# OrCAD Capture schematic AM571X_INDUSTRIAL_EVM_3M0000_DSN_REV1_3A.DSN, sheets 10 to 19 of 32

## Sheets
10 Pg22: JTAG Debug: size C
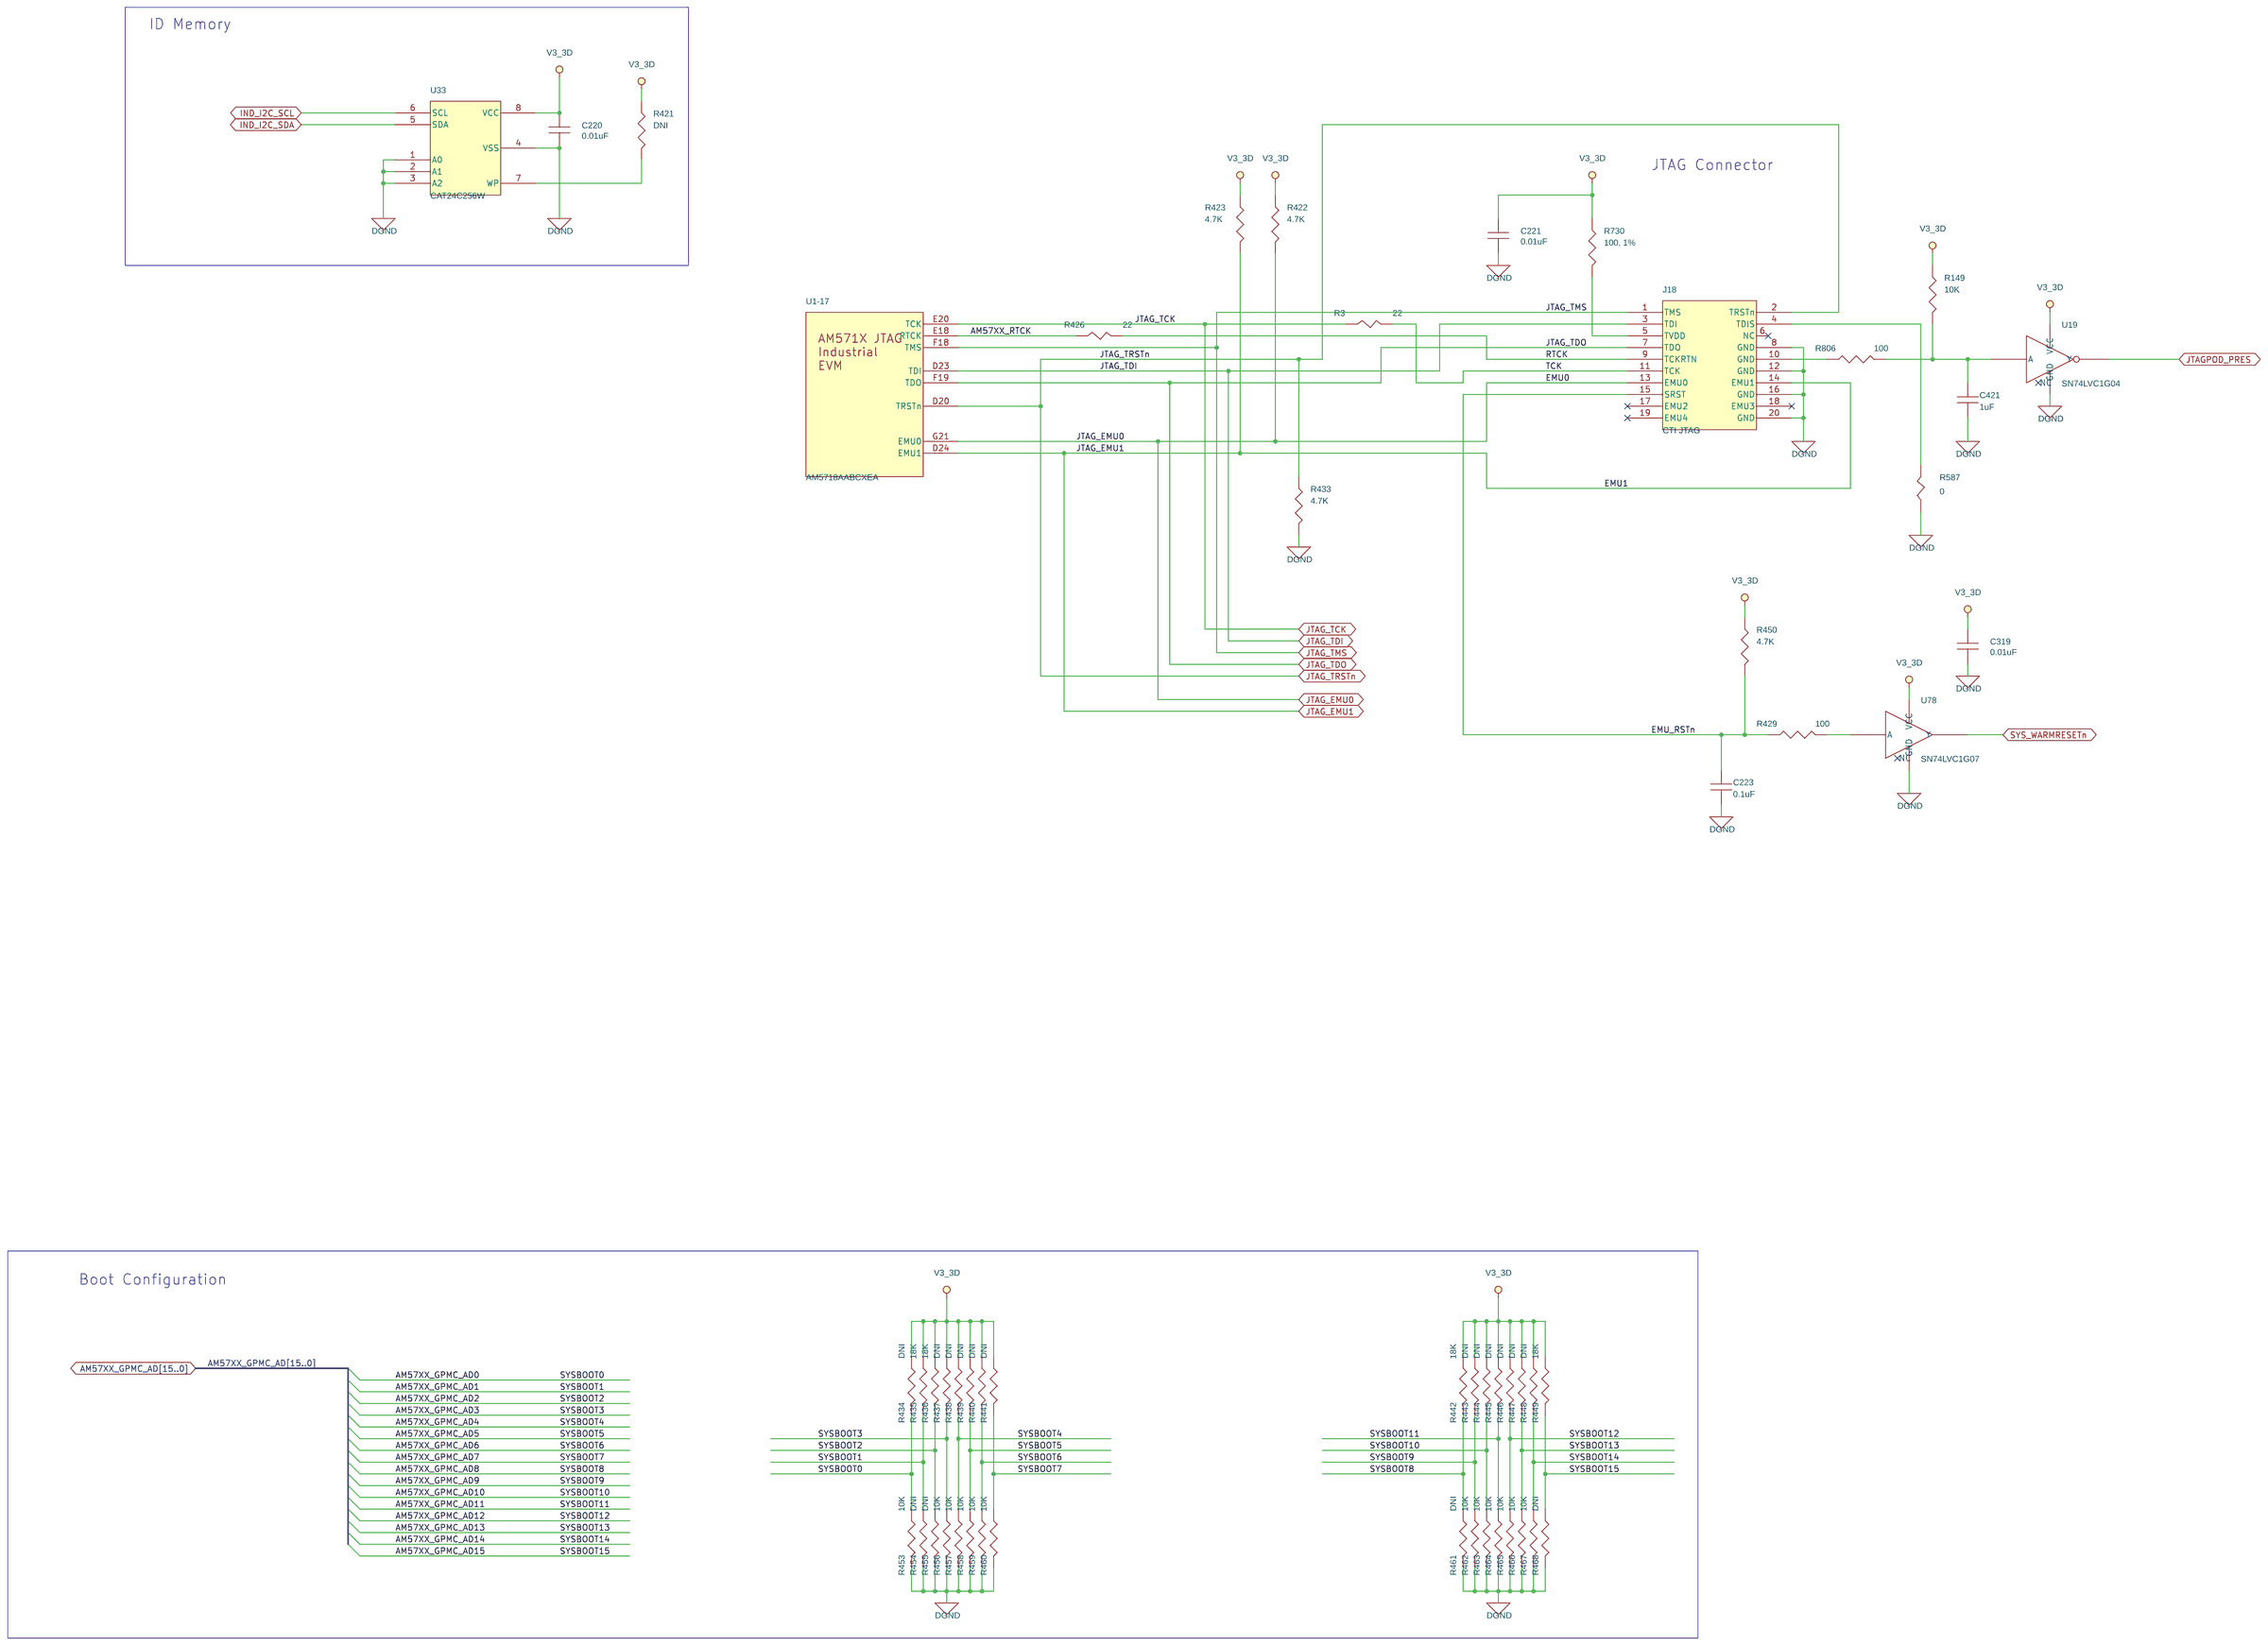
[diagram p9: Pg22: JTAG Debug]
11 Pg15: Camera #1: size C
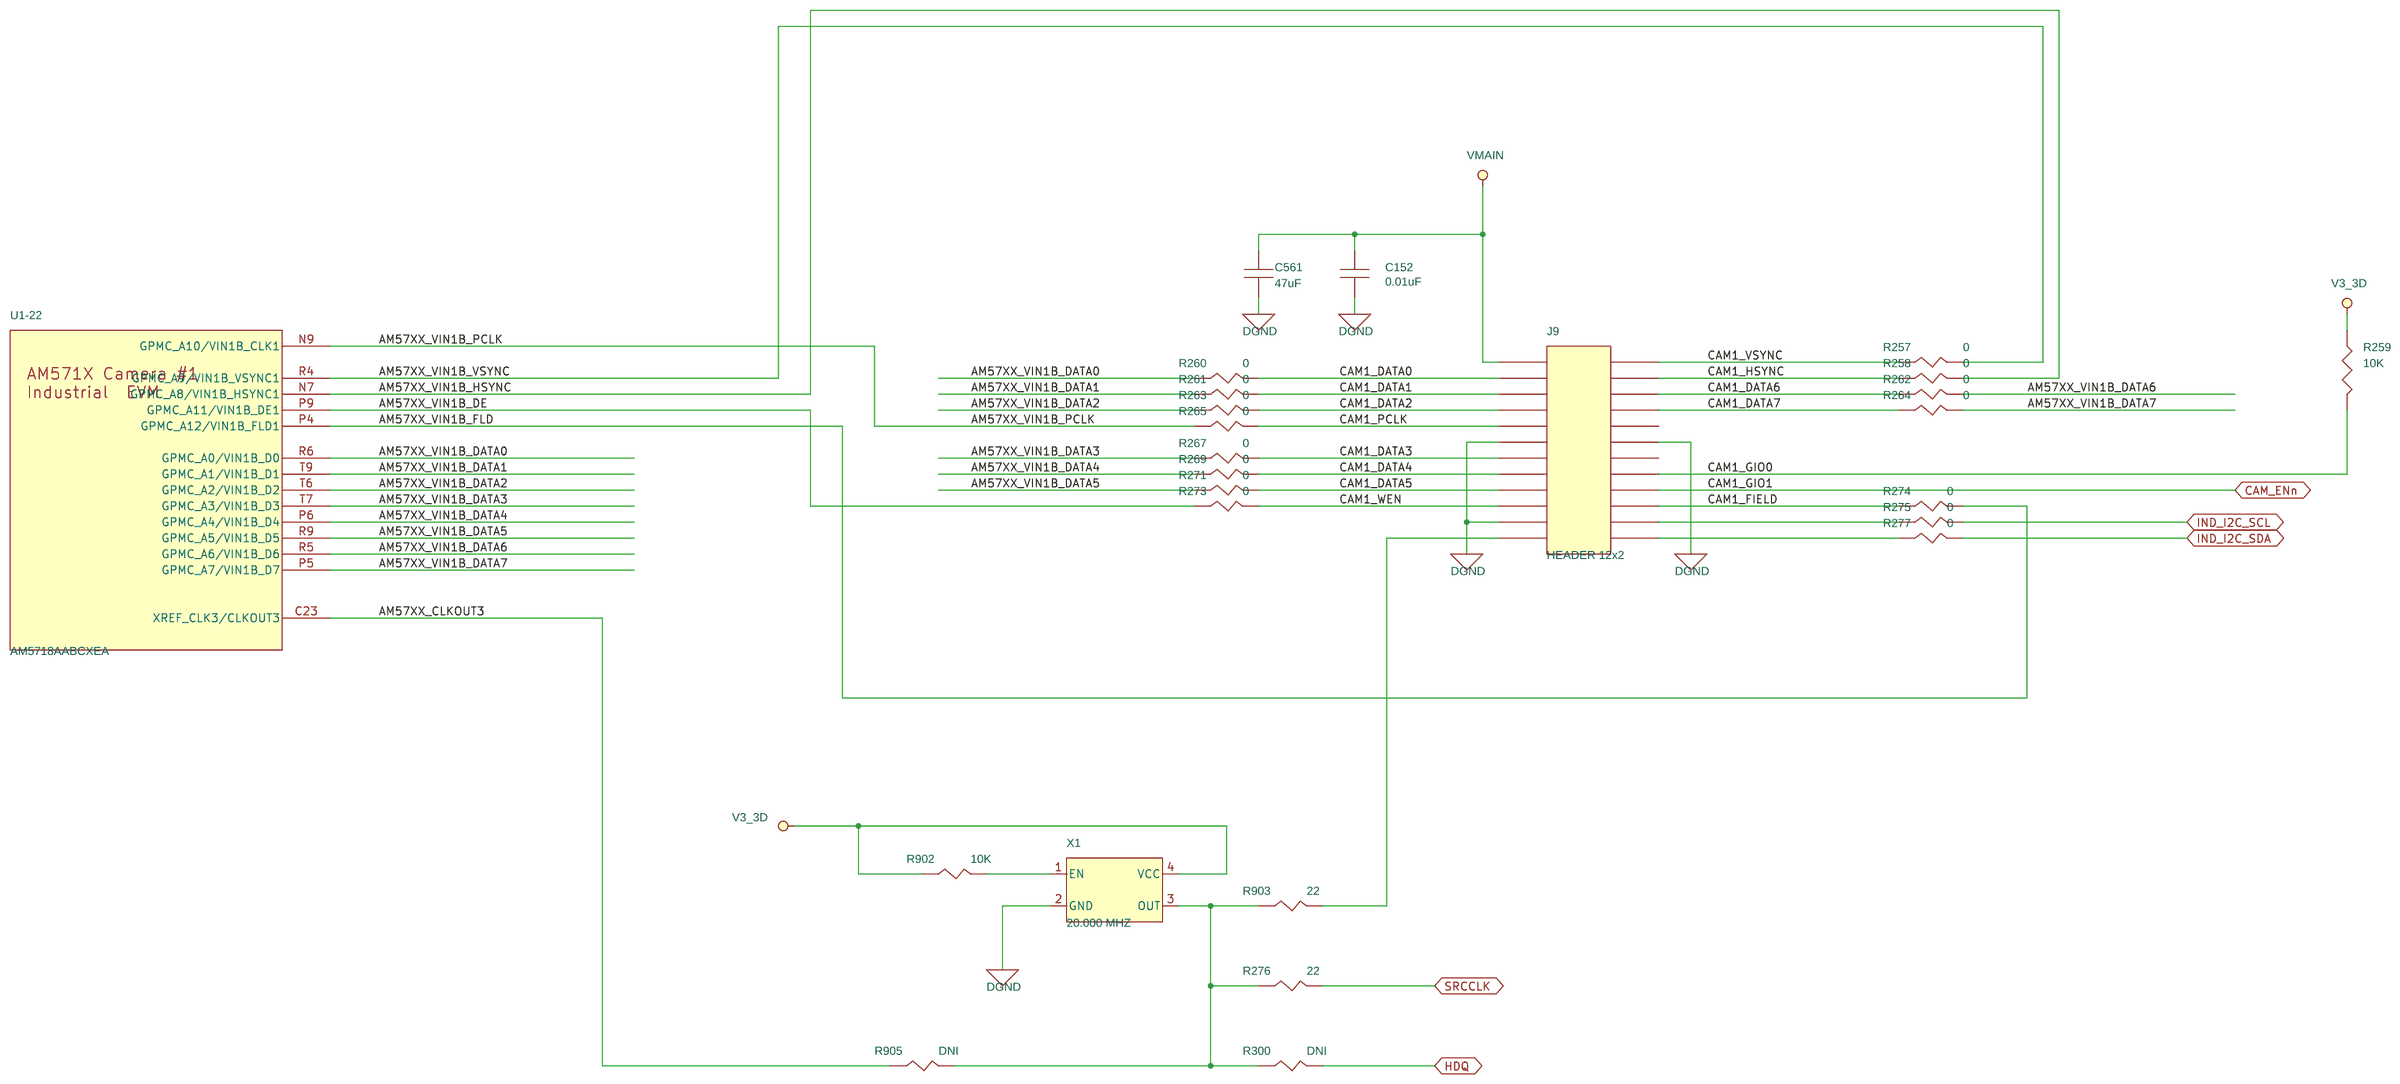
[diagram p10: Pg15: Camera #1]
12 Pg28: Profibus: size C
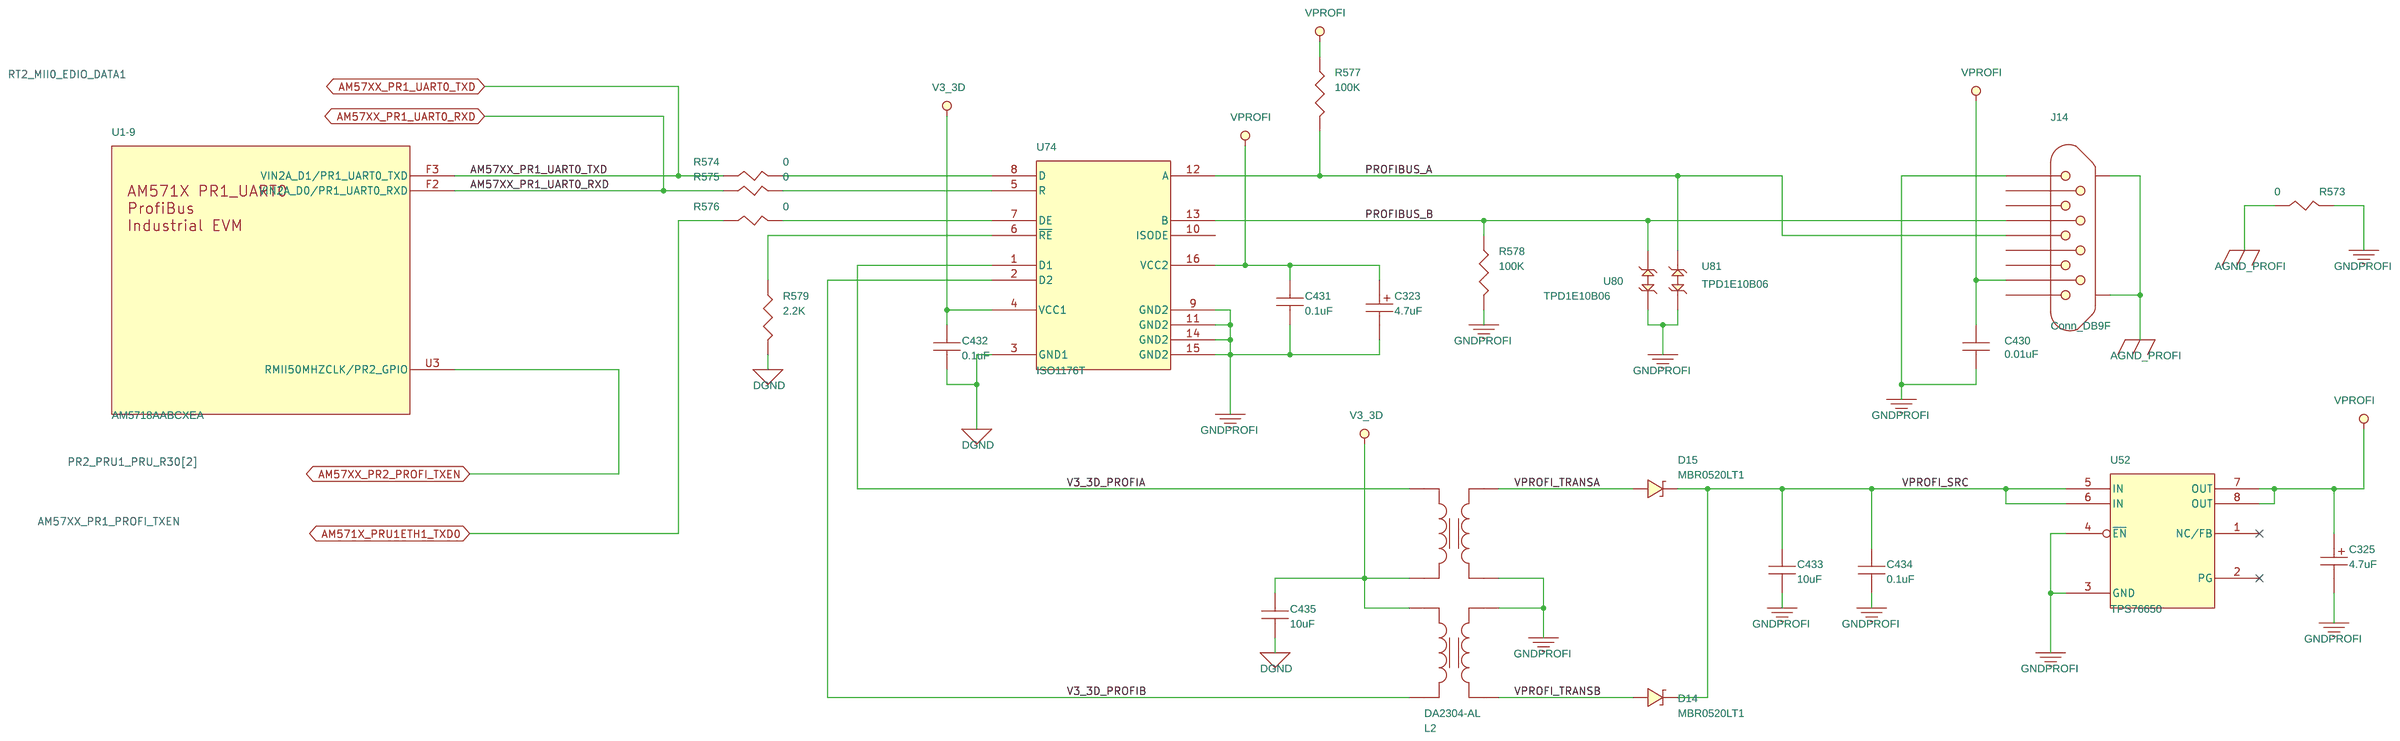
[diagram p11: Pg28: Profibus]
13 Pg01: Title Page
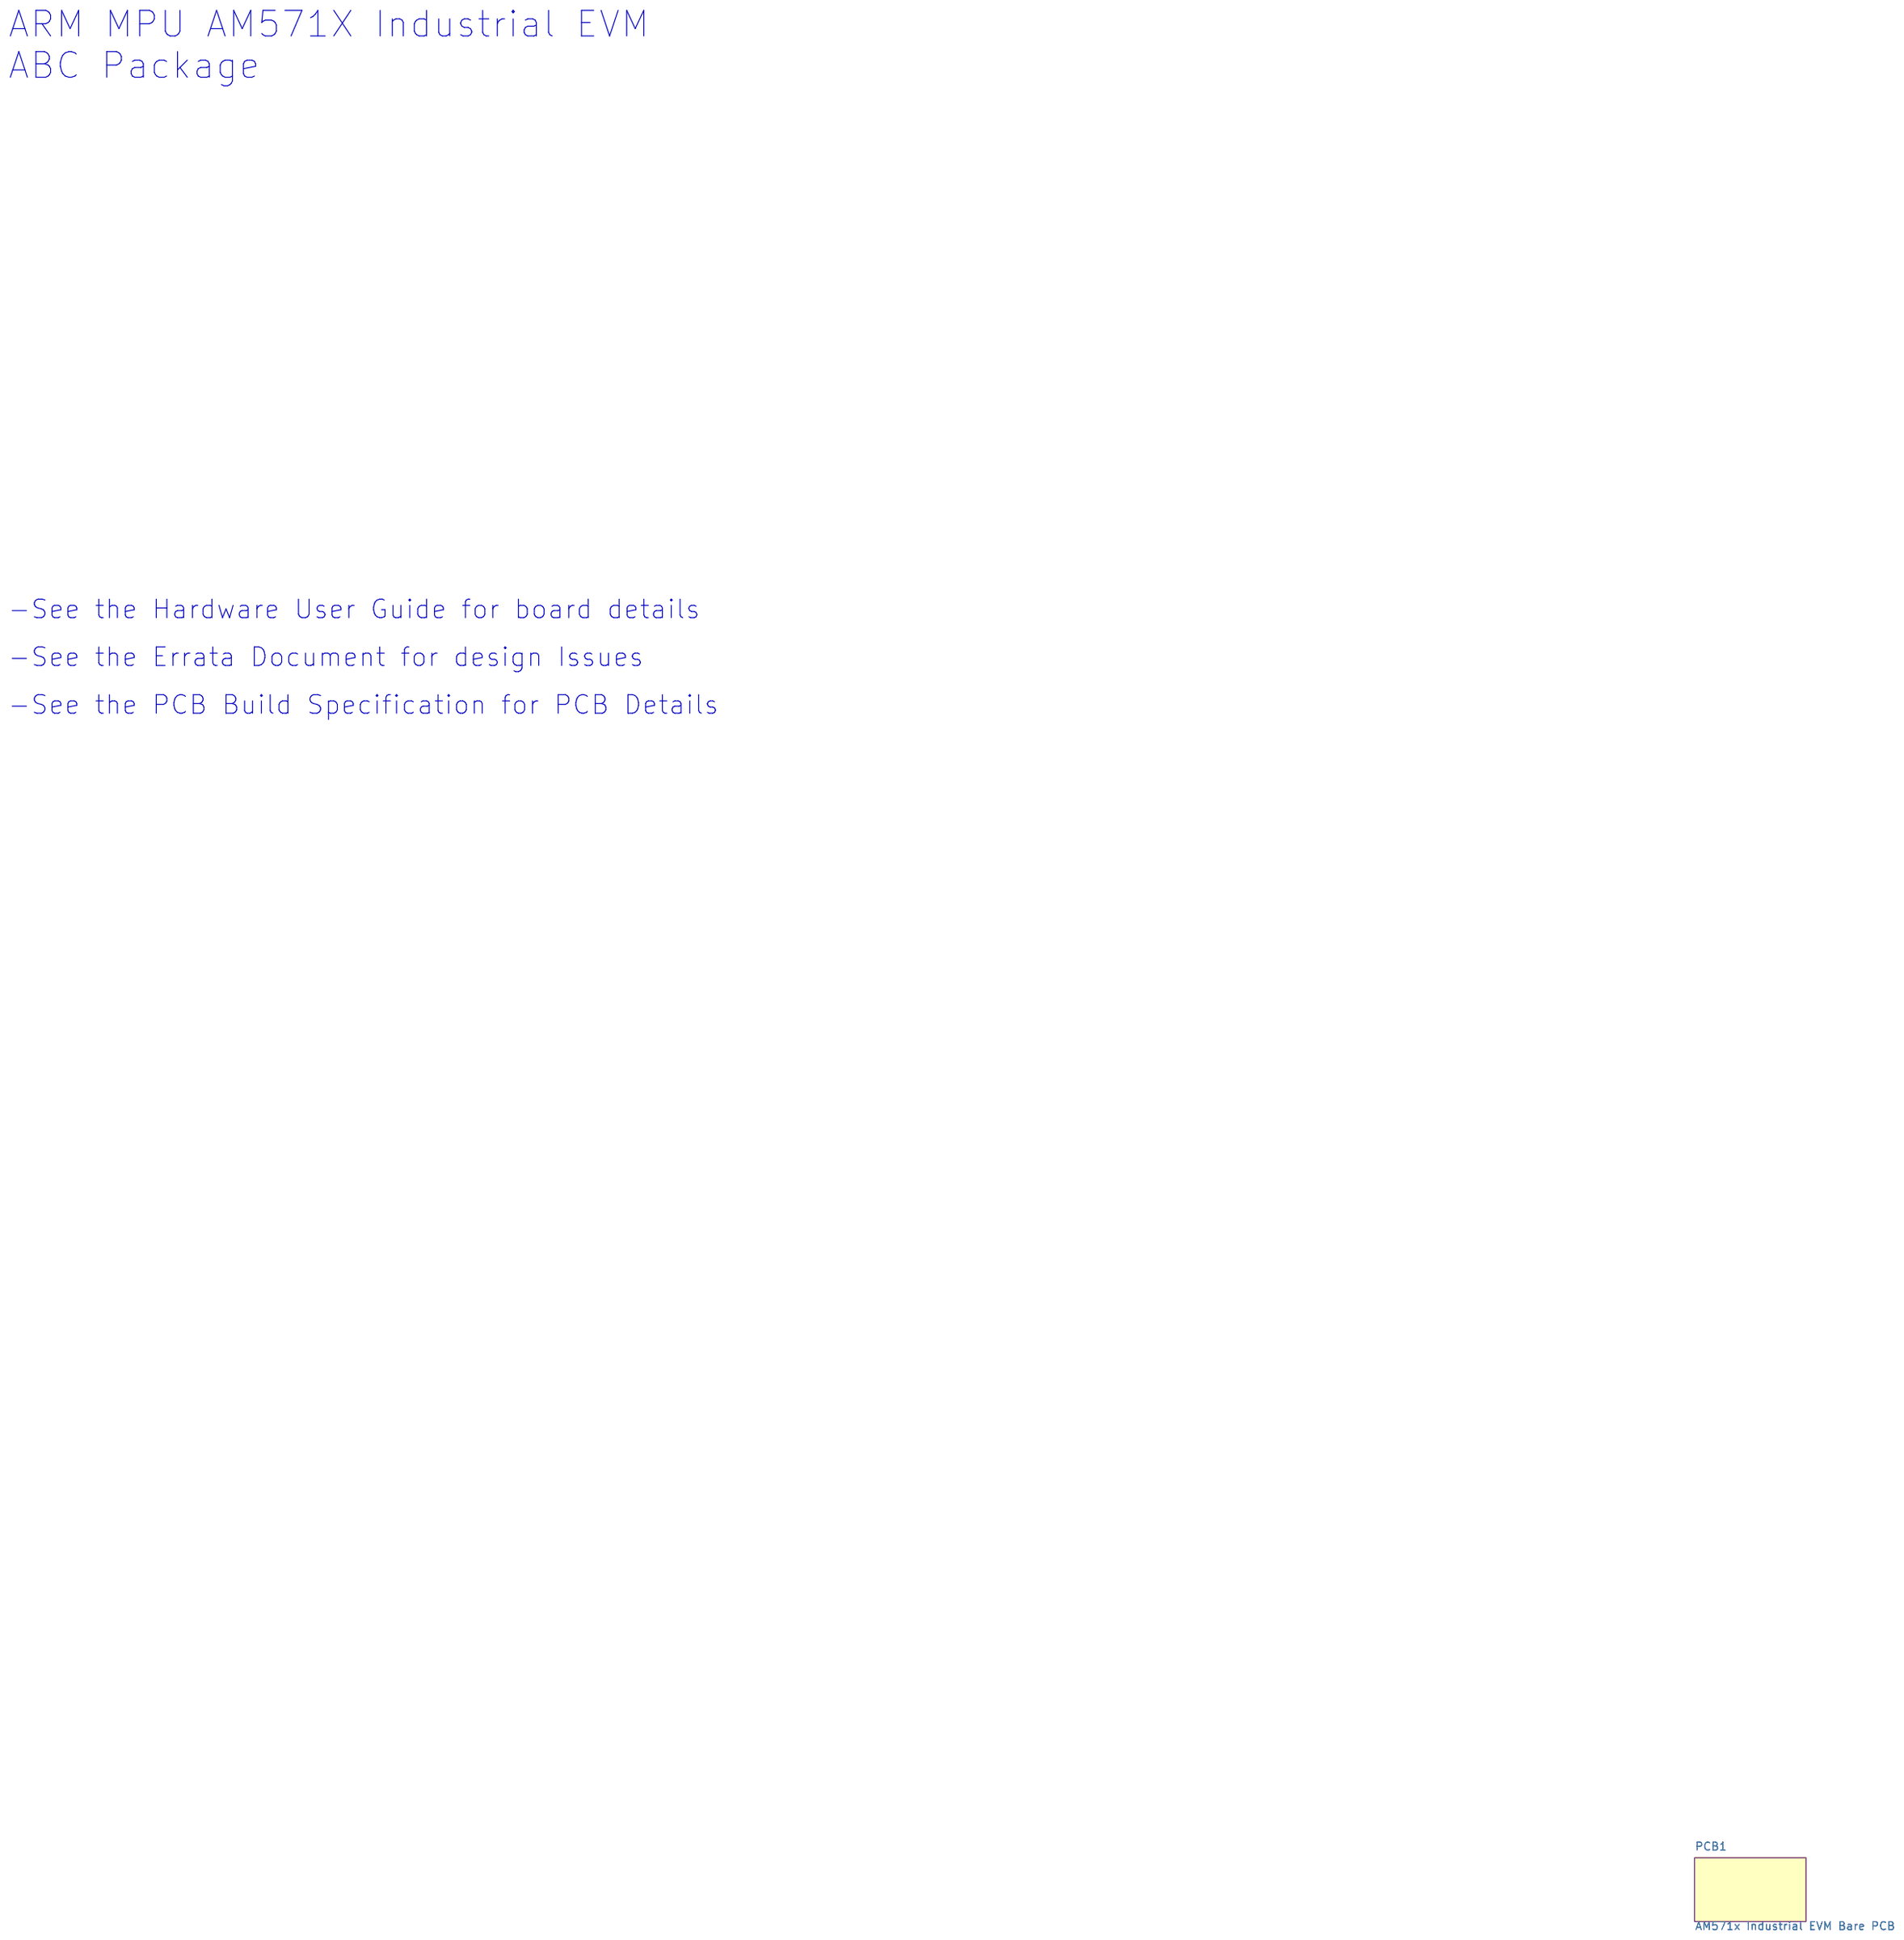
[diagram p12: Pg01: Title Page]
14 Pg26: USB #2 2.0: size C
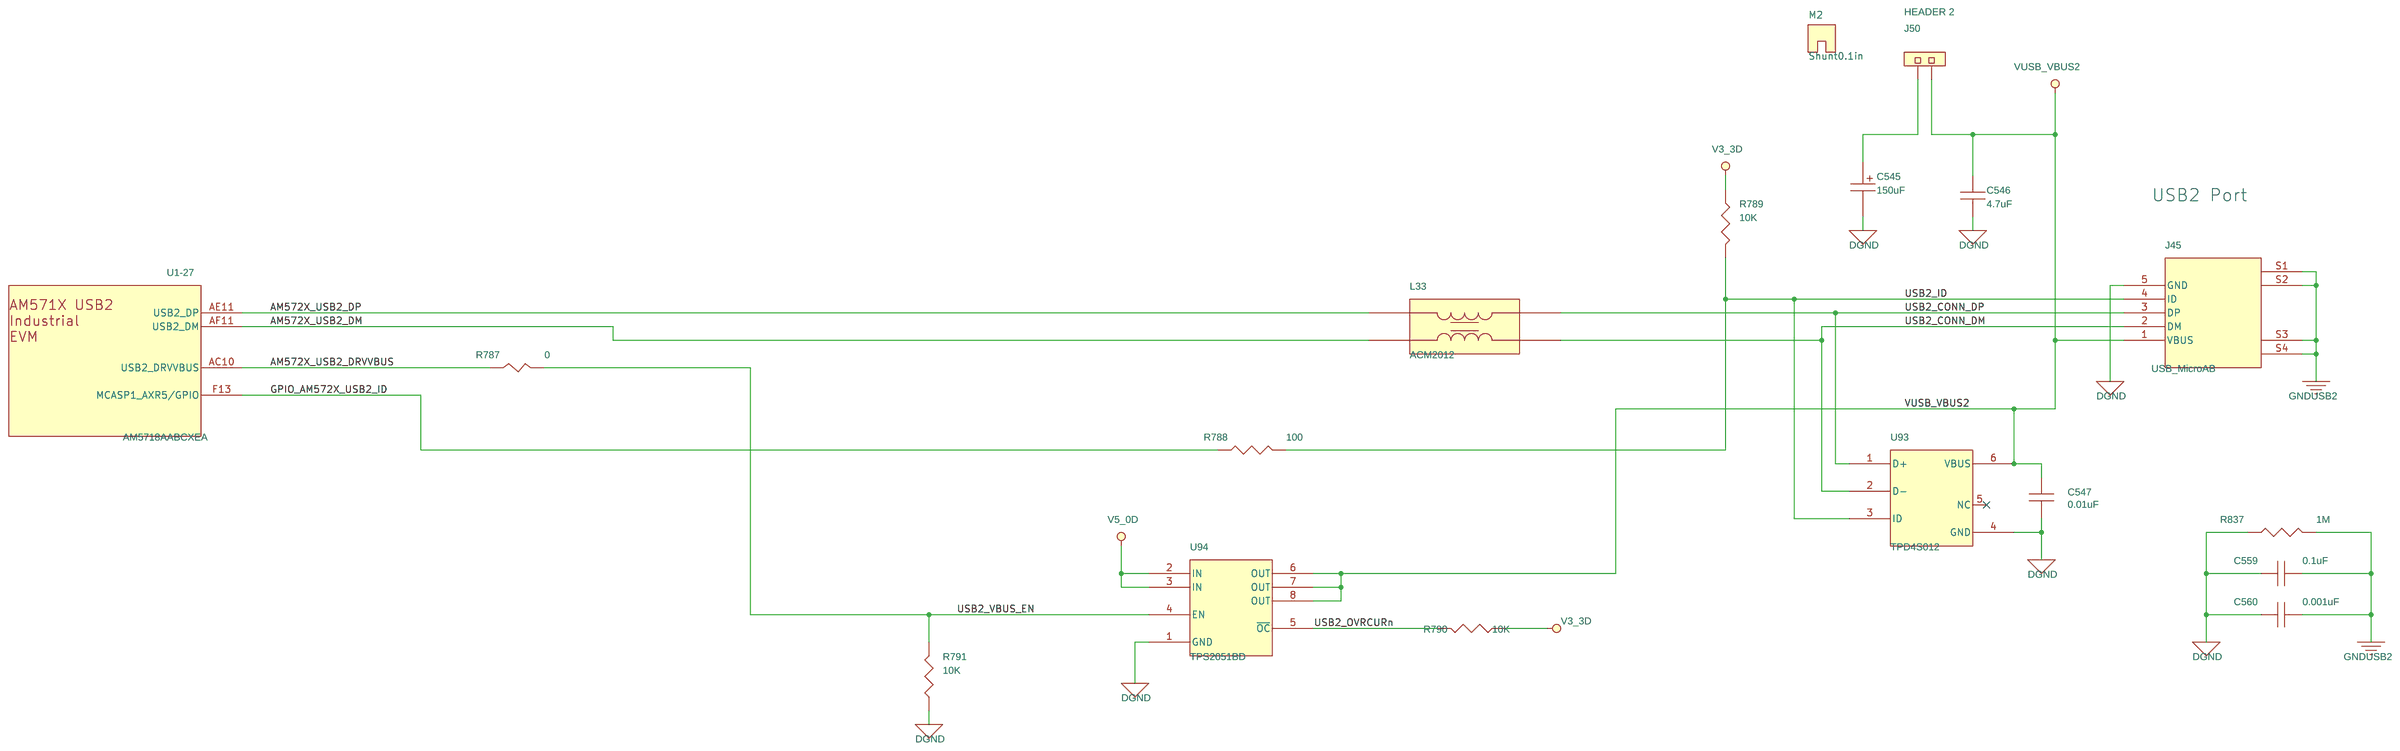
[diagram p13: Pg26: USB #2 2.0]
15 Pg25: USB #1 3.0: size C
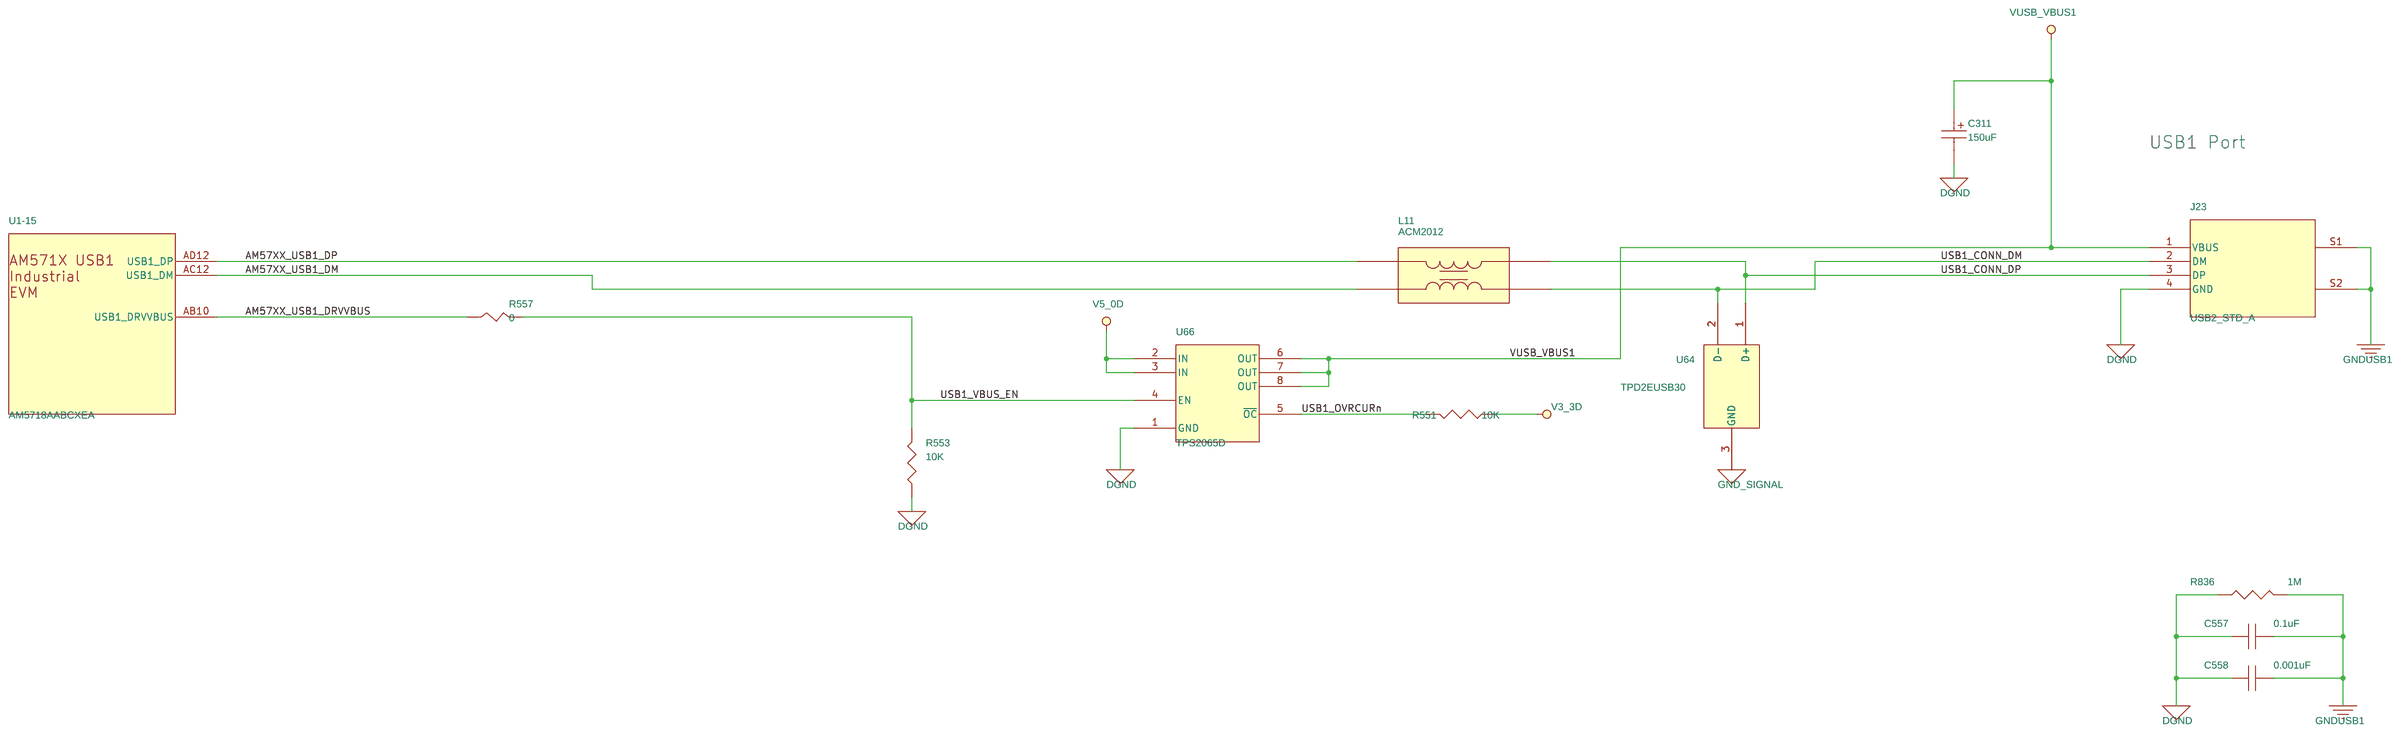
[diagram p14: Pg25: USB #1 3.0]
16 Pg08: DDR3 Memory 1: size C
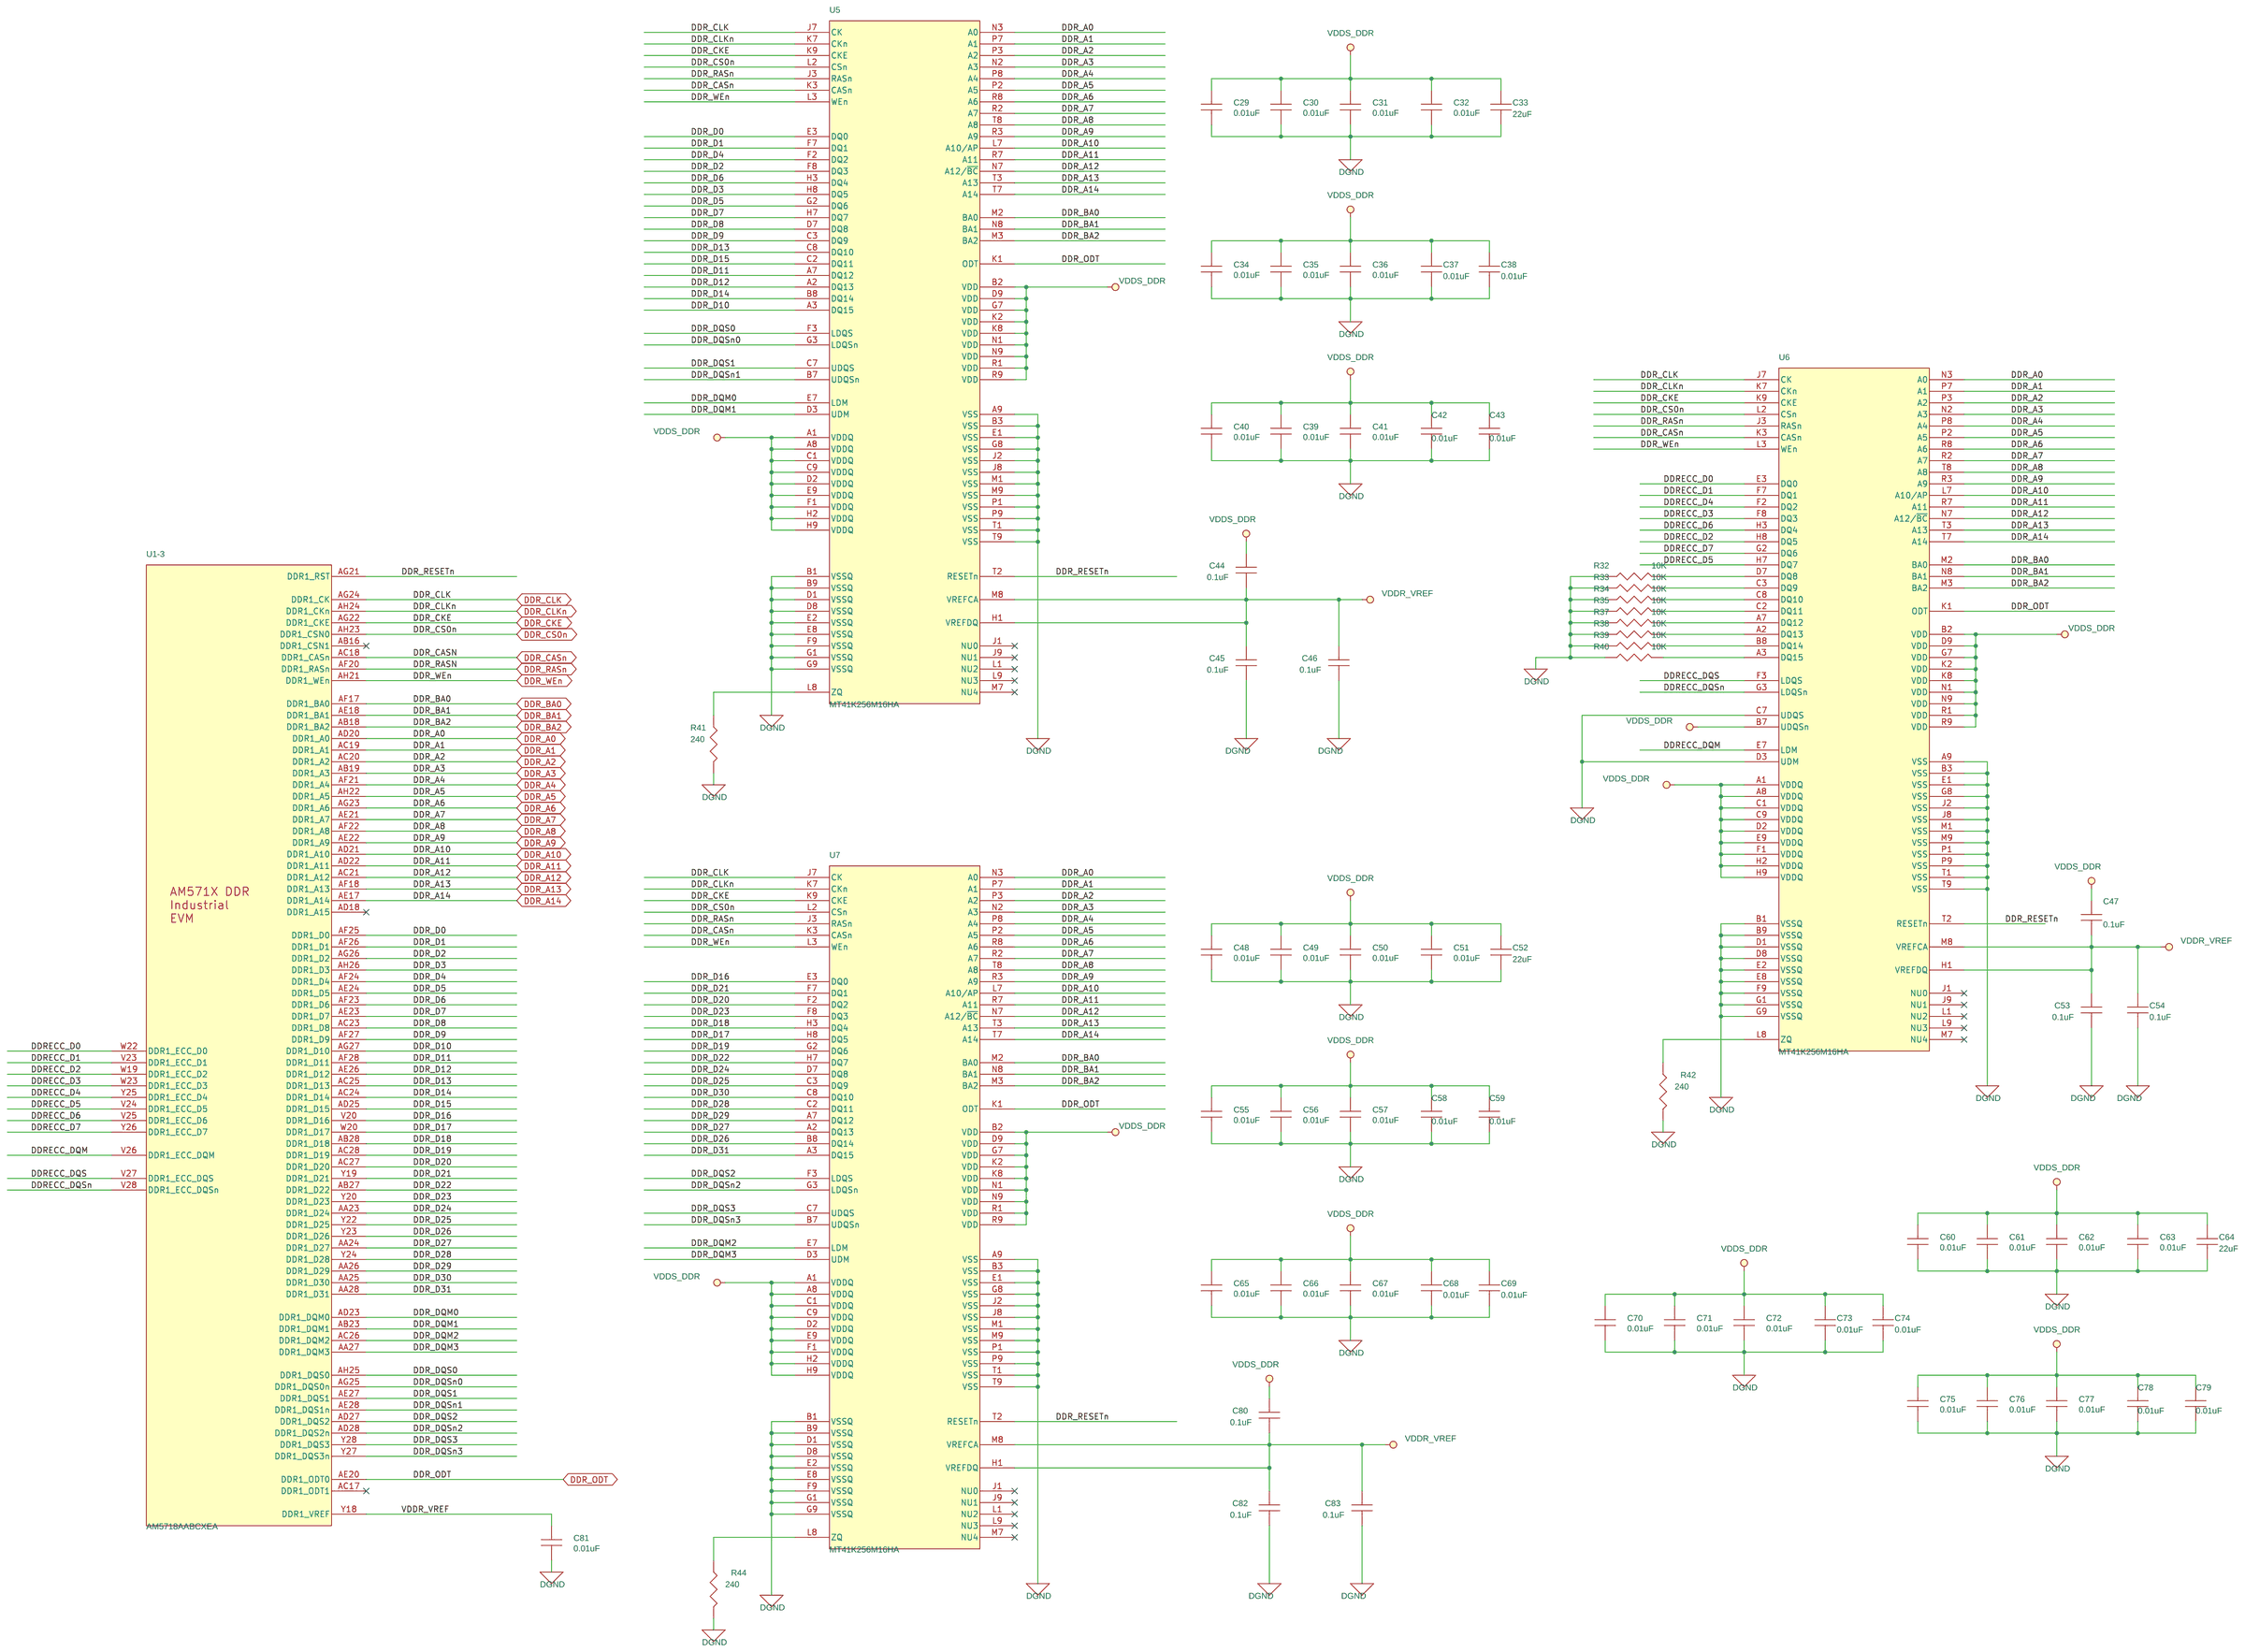
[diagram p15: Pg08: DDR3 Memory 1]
17 Pg03: Processor Power: size C
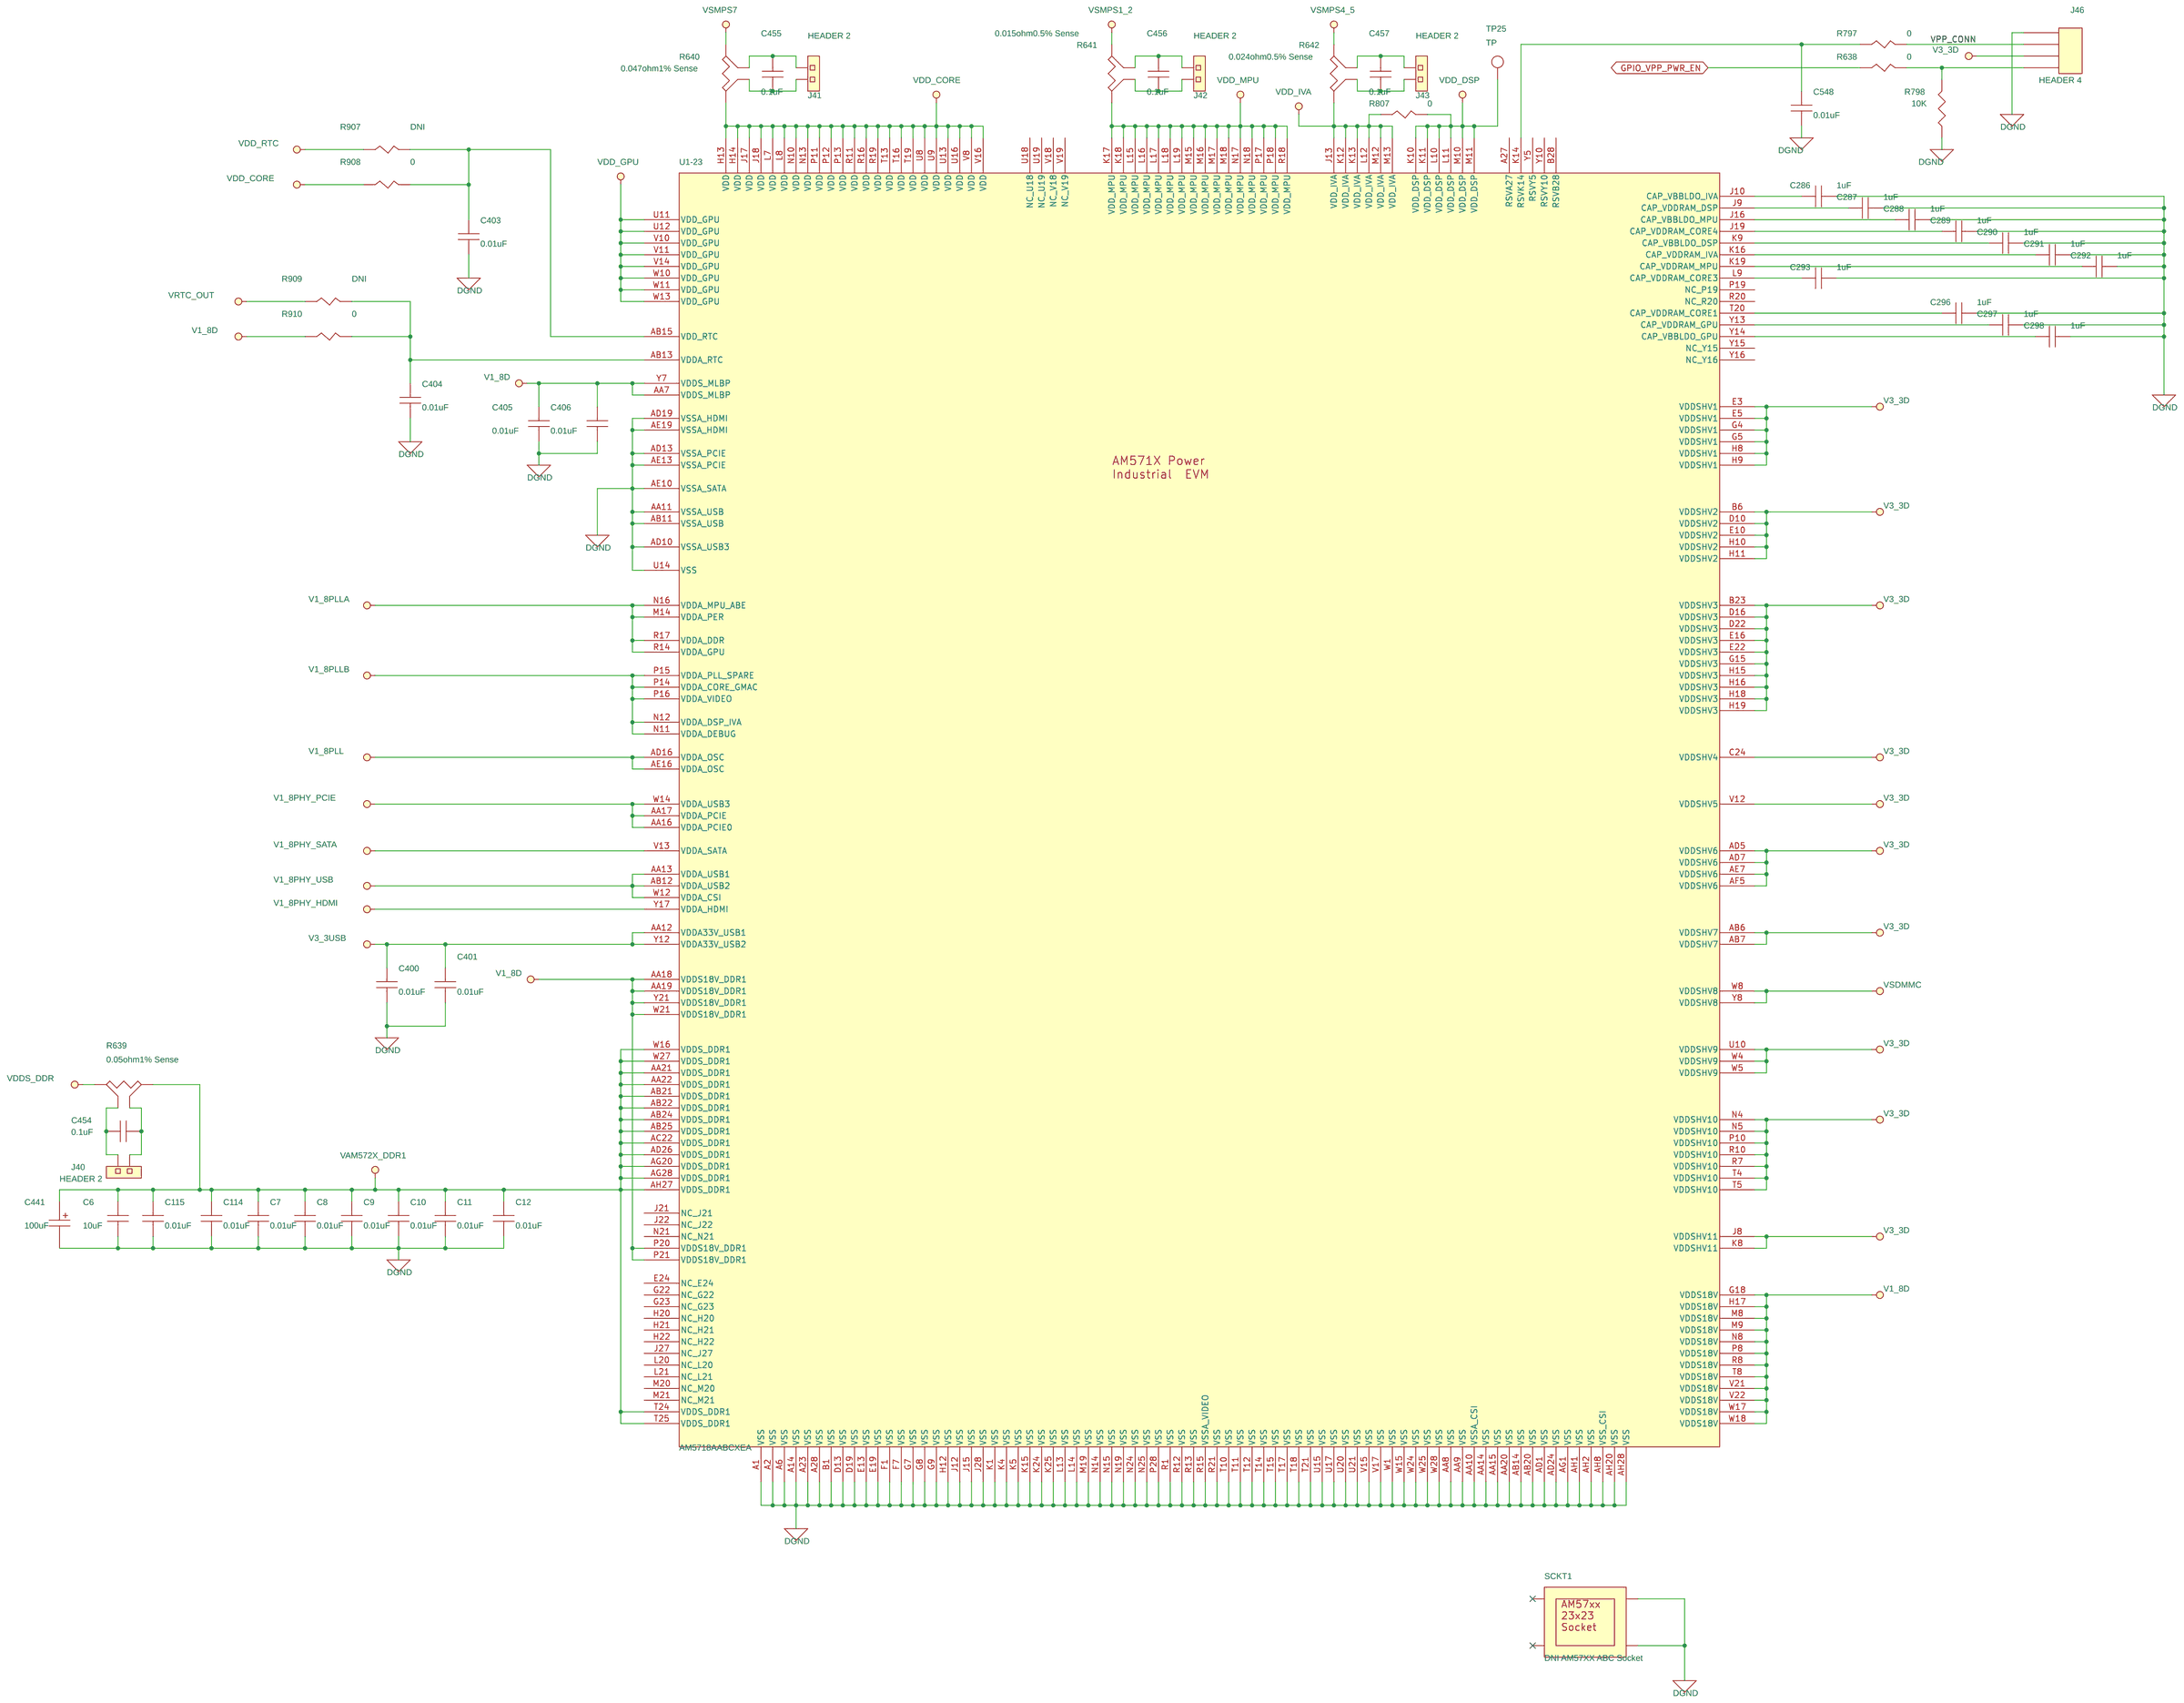
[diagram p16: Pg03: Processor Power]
18 Pg19: Industrial I/O: size C
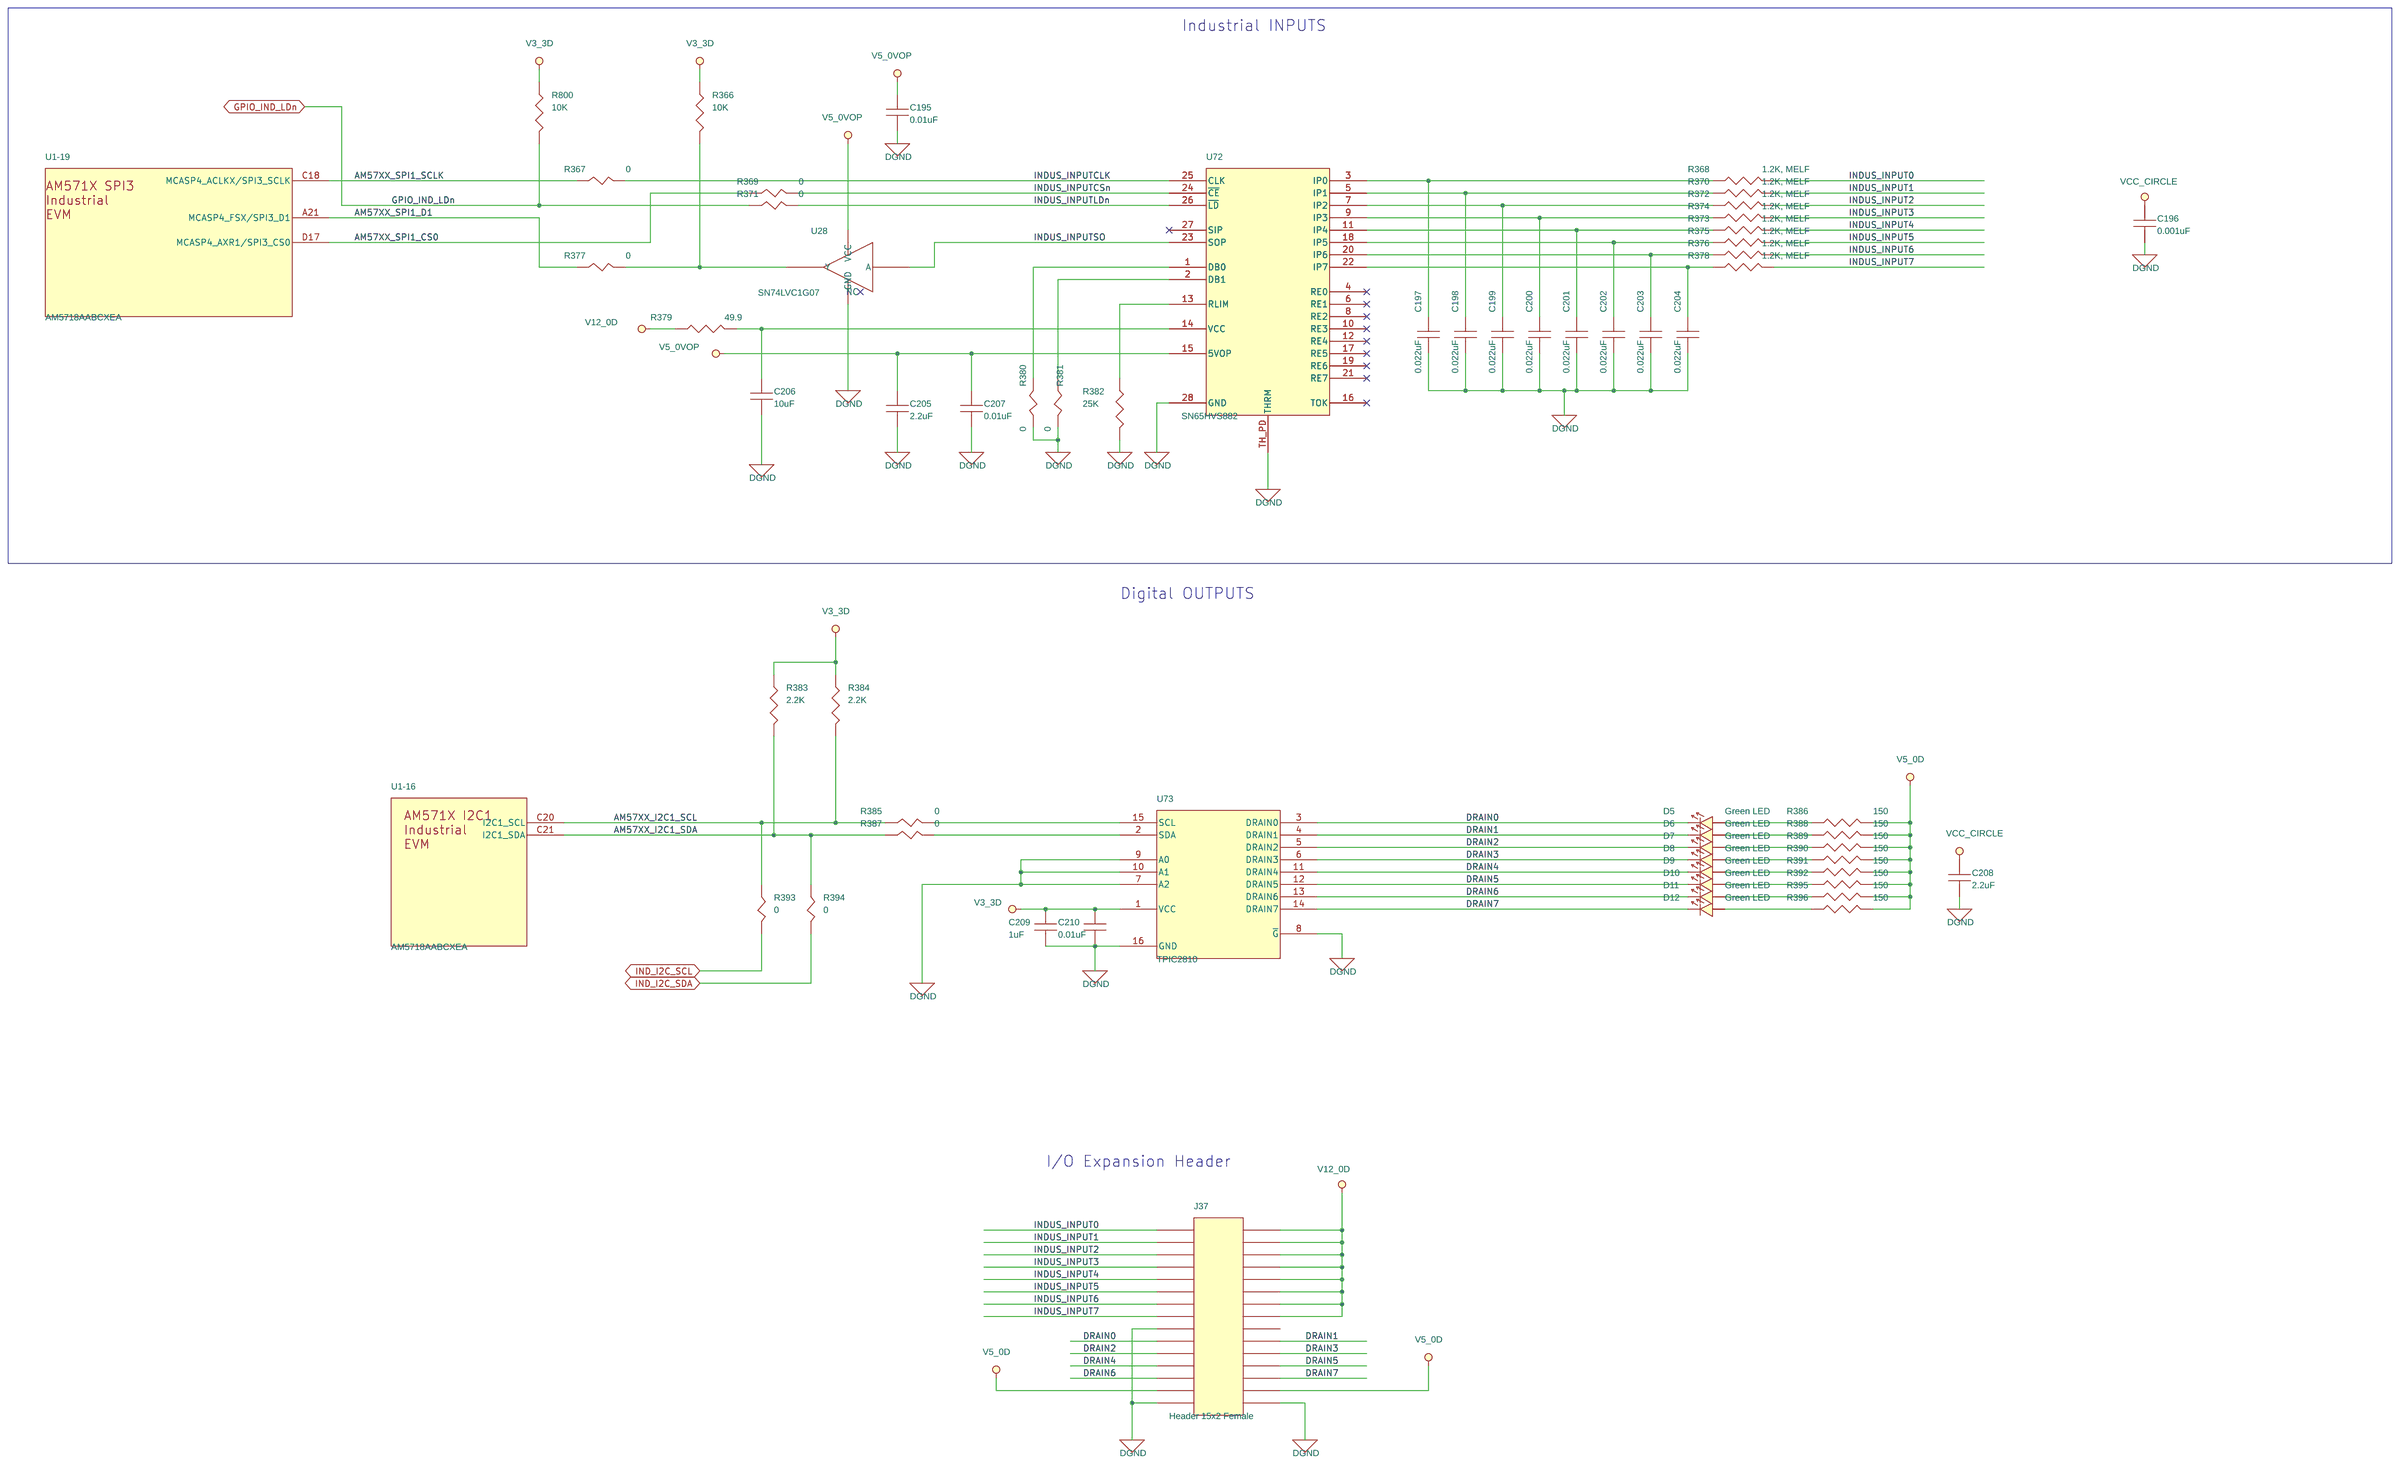
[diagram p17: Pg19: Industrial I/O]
19 Pg06: Power Supply 2: size C

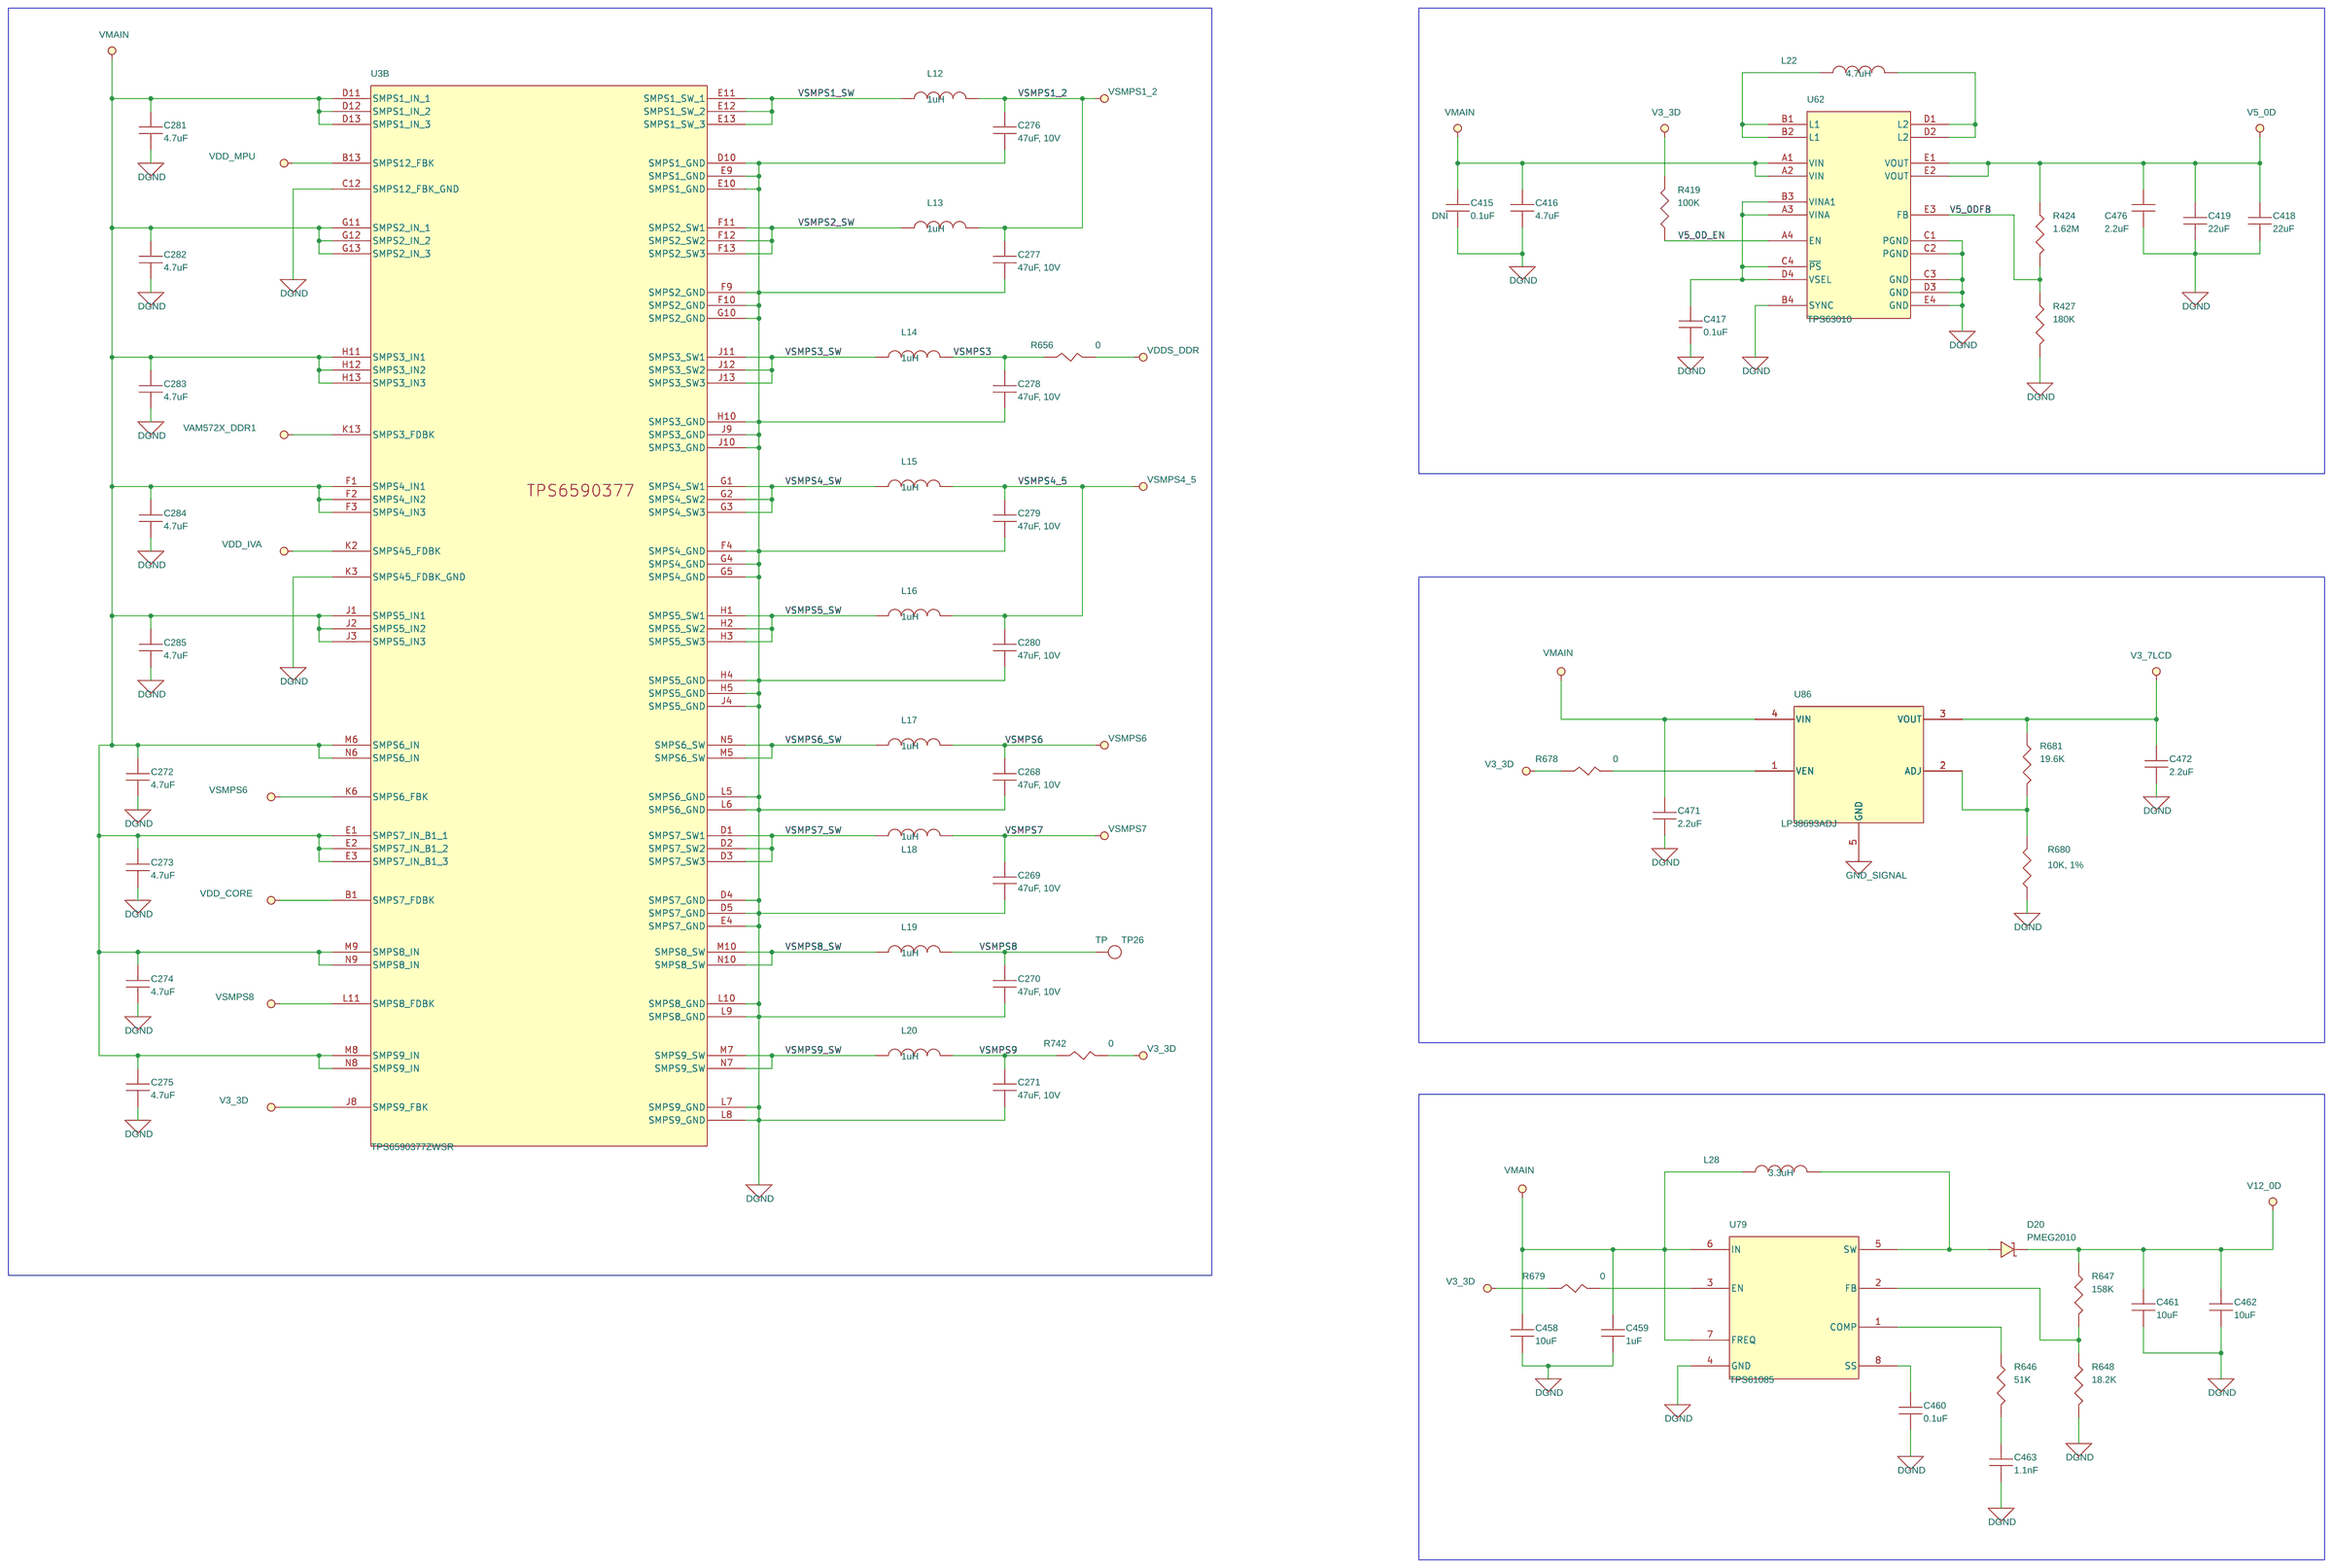
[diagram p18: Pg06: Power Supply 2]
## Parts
sheet Pg01: Title Page
PCB1  AM571x Industrial EVM Bare PCB  [DNP]
sheet Pg03: Processor Power
C6  10uF  [SM-7351-CAP-0805]
C7  0.01uF  [SM-7351-CAP-0402]
C8  0.01uF  [SM-7351-CAP-0402]
C9  0.01uF  [SM-7351-CAP-0402]
C10  0.01uF  [SM-7351-CAP-0402]
C11  0.01uF  [SM-7351-CAP-0402]
C12  0.01uF  [SM-7351-CAP-0402]
C114  0.01uF  [SM-7351-CAP-0402]
C115  0.01uF  [SM-7351-CAP-0402]
C286  1uF  [SM-7351-CAP-0402]
C287  1uF  [SM-7351-CAP-0402]
C288  1uF  [SM-7351-CAP-0402]
C289  1uF  [SM-7351-CAP-0402]
C290  1uF  [SM-7351-CAP-0402]
C291  1uF  [SM-7351-CAP-0402]
C292  1uF  [SM-7351-CAP-0402]
C293  1uF  [SM-7351-CAP-0402]
C296  1uF  [SM-7351-CAP-0402]
C297  1uF  [SM-7351-CAP-0402]
C298  1uF  [SM-7351-CAP-0402]
C400  0.01uF  [SM-7351-CAP-0402]
C401  0.01uF  [SM-7351-CAP-0402]
C403  0.01uF  [SM-7351-CAP-0402]
C404  0.01uF  [SM-7351-CAP-0402]
C405  0.01uF  [SM-7351-CAP-0402]
C406  0.01uF  [SM-7351-CAP-0402]
C441  100uF  [SM-7351-CAP-smdcan]
C454  0.1uF  [SM-7351-CAP-0402]
C455  0.1uF  [SM-7351-CAP-0402]
C456  0.1uF  [SM-7351-CAP-0402]
C457  0.1uF  [SM-7351-CAP-0402]
C548  0.01uF  [SM-7351-CAP-0402]
J40  HEADER 2  [header_2x1]
J41  HEADER 2  [header_2x1]
J42  HEADER 2  [header_2x1]
J43  HEADER 2  [header_2x1]
J46  HEADER 4  [HDR1x4-330M]
R638  0  [SM-7351-RES-0402]
R639  0.05ohm1% Sense  [SM_RES_LVK12]
R640  0.047ohm1% Sense  [SM_RES_LVK12]
R641  0.015ohm0.5% Sense  [SM_RES_LVK12]
R642  0.024ohm0.5% Sense  [SM_RES_LVK12]
R797  0  [SM-7351-RES-0402]
R798  10K  [SM-7351-RES-0402]
R807  0  [SM-7351-RES-0402]
R907  DNI  [SM-7351-RES-0402]
R908  0  [SM-7351-RES-0402]
R909  DNI  [SM-7351-RES-0402]
R910  0  [SM-7351-RES-0402]
SCKT1  DNI AM57XX ABC Socket  [SCK-SG-BGA-6334]
TP25  TP  [TH_TP_5002]
sheet Pg05: Power Supply 1
U3  TPS6590377ZWSR  [bga12x12-169-55m]  (sections A,B)
sheet Pg06: Power Supply 2
C268  47uF, 10V  [SM-7351-CAP-1206]
C269  47uF, 10V  [SM-7351-CAP-1206]
C270  47uF, 10V  [SM-7351-CAP-1206]
C271  47uF, 10V  [SM-7351-CAP-1206]
C272  4.7uF  [SM-7351-CAP-0603]
C273  4.7uF  [SM-7351-CAP-0603]
C274  4.7uF  [SM-7351-CAP-0603]
C275  4.7uF  [SM-7351-CAP-0603]
C276  47uF, 10V  [SM-7351-CAP-1206]
C277  47uF, 10V  [SM-7351-CAP-1206]
C278  47uF, 10V  [SM-7351-CAP-1206]
C279  47uF, 10V  [SM-7351-CAP-1206]
C280  47uF, 10V  [SM-7351-CAP-1206]
C281  4.7uF  [SM-7351-CAP-0603]
C282  4.7uF  [SM-7351-CAP-0603]
C283  4.7uF  [SM-7351-CAP-0603]
C284  4.7uF  [SM-7351-CAP-0603]
C285  4.7uF  [SM-7351-CAP-0603]
C415  0.1uF  [SM-7351-CAP-0402]
C416  4.7uF  [SM-7351-CAP-0603]
C417  0.1uF  [SM-7351-CAP-0402]
C418  22uF  [SM-7351-CAP-0805]
C419  22uF  [SM-7351-CAP-0805]
C458  10uF  [SM-7351-CAP-0805]
C459  1uF  [SM-7351-CAP-0603]
C460  0.1uF  [SM-7351-CAP-0402]
C461  10uF  [SM-7351-CAP-0805]
C462  10uF  [SM-7351-CAP-0805]
C463  1.1nF  [SM-7351-CAP-0603]
C471  2.2uF  [SM-7351-CAP-0805]
C472  2.2uF  [SM-7351-CAP-0805]
C476  2.2uF  [SM-7351-CAP-0402]
D20  PMEG2010  [DFN1006D-2]
L12  1uH  [ind_ihlp1616ab]
L13  1uH  [ind_ihlp1616ab]
L14  1uH  [ind_ihlp1616ab]
L15  1uH  [ind_ihlp1616ab]
L16  1uH  [ind_ihlp1616ab]
L17  1uH  [ind_ihlp1616ab]
L18  1uH  [ind_ihlp1616ab]
L19  1uH  [ind_ihlp1616ab]
L20  1uH  [ind_ihlp1616ab]
L22  4.7uH  [smd_slf7055t]
L28  3.3uH  [vlcf5020t]
R419  100K  [SM-7351-RES-0402]
R424  1.62M  [SM-7351-RES-0402]
R427  180K  [SM-7351-RES-0402]
R646  51K  [SM-7351-RES-0402]
R647  158K  [SM-7351-RES-0402]
R648  18.2K  [SM-7351-RES-0402]
R656  0  [SM-7351-RES-0603]
R678  0  [SM-7351-RES-0402]
R679  0  [SM-7351-RES-0402]
R680  10K, 1%  [SM-7351-RES-0402]
R681  19.6K  [SM-7351-RES-0402]
R742  0  [SM-7351-RES-0603]
TP26  TP  [TH_TP_5002]
U62  TPS63010  [u_20_dsbga]
U79  TPS61085  [MSOP3X3-8-43M]
U86  LP38693ADJ  [SOT-223-5]
sheet Pg08: DDR3 Memory 1
C29  0.01uF  [SM-7351-CAP-0402]
C30  0.01uF  [SM-7351-CAP-0402]
C31  0.01uF  [SM-7351-CAP-0402]
C32  0.01uF  [SM-7351-CAP-0402]
C33  22uF  [SM-7351-CAP-0805]
C34  0.01uF  [SM-7351-CAP-0402]
C35  0.01uF  [SM-7351-CAP-0402]
C36  0.01uF  [SM-7351-CAP-0402]
C37  0.01uF  [SM-7351-CAP-0402]
C38  0.01uF  [SM-7351-CAP-0402]
C39  0.01uF  [SM-7351-CAP-0402]
C40  0.01uF  [SM-7351-CAP-0402]
C41  0.01uF  [SM-7351-CAP-0402]
C42  0.01uF  [SM-7351-CAP-0402]
C43  0.01uF  [SM-7351-CAP-0402]
C44  0.1uF  [SM-7351-CAP-0402]
C45  0.1uF  [SM-7351-CAP-0402]
C46  0.1uF  [SM-7351-CAP-0402]
C47  0.1uF  [SM-7351-CAP-0402]
C48  0.01uF  [SM-7351-CAP-0402]
C49  0.01uF  [SM-7351-CAP-0402]
C50  0.01uF  [SM-7351-CAP-0402]
C51  0.01uF  [SM-7351-CAP-0402]
C52  22uF  [SM-7351-CAP-0805]
C53  0.1uF  [SM-7351-CAP-0402]
C54  0.1uF  [SM-7351-CAP-0402]
C55  0.01uF  [SM-7351-CAP-0402]
C56  0.01uF  [SM-7351-CAP-0402]
C57  0.01uF  [SM-7351-CAP-0402]
C58  0.01uF  [SM-7351-CAP-0402]
C59  0.01uF  [SM-7351-CAP-0402]
C60  0.01uF  [SM-7351-CAP-0402]
C61  0.01uF  [SM-7351-CAP-0402]
C62  0.01uF  [SM-7351-CAP-0402]
C63  0.01uF  [SM-7351-CAP-0402]
C64  22uF  [SM-7351-CAP-0805]
C65  0.01uF  [SM-7351-CAP-0402]
C66  0.01uF  [SM-7351-CAP-0402]
C67  0.01uF  [SM-7351-CAP-0402]
C68  0.01uF  [SM-7351-CAP-0402]
C69  0.01uF  [SM-7351-CAP-0402]
C70  0.01uF  [SM-7351-CAP-0402]
C71  0.01uF  [SM-7351-CAP-0402]
C72  0.01uF  [SM-7351-CAP-0402]
C73  0.01uF  [SM-7351-CAP-0402]
C74  0.01uF  [SM-7351-CAP-0402]
C75  0.01uF  [SM-7351-CAP-0402]
C76  0.01uF  [SM-7351-CAP-0402]
C77  0.01uF  [SM-7351-CAP-0402]
C78  0.01uF  [SM-7351-CAP-0402]
C79  0.01uF  [SM-7351-CAP-0402]
C80  0.1uF  [SM-7351-CAP-0402]
C81  0.01uF  [SM-7351-CAP-0402]
C82  0.1uF  [SM-7351-CAP-0402]
C83  0.1uF  [SM-7351-CAP-0402]
R32  10K  [SM-7351-RES-0402]
R33  10K  [SM-7351-RES-0402]
R34  10K  [SM-7351-RES-0402]
R35  10K  [SM-7351-RES-0402]
R37  10K  [SM-7351-RES-0402]
R38  10K  [SM-7351-RES-0402]
R39  10K  [SM-7351-RES-0402]
R40  10K  [SM-7351-RES-0402]
R41  240  [sm-7351-res-0402]
R42  240  [sm-7351-res-0402]
R44  240  [sm-7351-res-0402]
U5  MT41K256M16HA  [bga9x14-96]
U6  MT41K256M16HA  [bga9x14-96]
U7  MT41K256M16HA  [bga9x14-96]
sheet Pg15: Camera #1
C152  0.01uF  [SM-7351-CAP-0402]
C561  47uF  [SM-7351-CAP-1206]
J9  HEADER 12x2  [hdr2x12]
R257  0  [SM-7351-RES-0402]
R258  0  [SM-7351-RES-0402]
R259  10K  [SM-7351-RES-0402]
R260  0  [SM-7351-RES-0402]
R261  0  [SM-7351-RES-0402]
R262  0  [SM-7351-RES-0402]
R263  0  [SM-7351-RES-0402]
R264  0  [SM-7351-RES-0402]
R265  0  [SM-7351-RES-0402]
R267  0  [SM-7351-RES-0402]
R269  0  [SM-7351-RES-0402]
R271  0  [SM-7351-RES-0402]
R273  0  [SM-7351-RES-0402]
R274  0  [SM-7351-RES-0402]
R275  0  [SM-7351-RES-0402]
R276  22  [SM-7351-RES-0402]
R277  0  [SM-7351-RES-0402]
R300  DNI  [SM-7351-RES-0402]
R902  10K  [SM-7351-RES-0402]
R903  22  [SM-7351-RES-0402]
R905  DNI  [SM-7351-RES-0402]
X1  20.000 MHZ  [OSC7X5-71M]
sheet Pg19: Industrial I/O
C195  0.01uF  [SM-7351-CAP-0402]
C196  0.001uF  [SM-7351-CAP-0402]
C197  0.022uF  [SM-7351-CAP-0402]
C198  0.022uF  [SM-7351-CAP-0402]
C199  0.022uF  [SM-7351-CAP-0402]
C200  0.022uF  [SM-7351-CAP-0402]
C201  0.022uF  [SM-7351-CAP-0402]
C202  0.022uF  [SM-7351-CAP-0402]
C203  0.022uF  [SM-7351-CAP-0402]
C204  0.022uF  [SM-7351-CAP-0402]
C205  2.2uF  [SM-7351-CAP-0805]
C206  10uF  [SM-7351-CAP-1206]
C207  0.01uF  [SM-7351-CAP-0402]
C208  2.2uF  [SM-7351-CAP-0805]
C209  1uF  [SM-7351-CAP-0402]
C210  0.01uF  [SM-7351-CAP-0402]
D5  Green LED  [sm_led_0805]
D6  Green LED  [sm_led_0805]
D7  Green LED  [sm_led_0805]
D8  Green LED  [sm_led_0805]
D9  Green LED  [sm_led_0805]
D10  Green LED  [sm_led_0805]
D11  Green LED  [sm_led_0805]
D12  Green LED  [sm_led_0805]
J37  Header 15x2 Female  [HDR2X15-344M]
R366  10K  [SM-7351-RES-0402]
R367  0  [SM-7351-RES-0402]
R368  1.2K, MELF  [smd_melf0102]
R369  0  [SM-7351-RES-0402]
R370  1.2K, MELF  [smd_melf0102]
R371  0  [SM-7351-RES-0402]
R372  1.2K, MELF  [smd_melf0102]
R373  1.2K, MELF  [smd_melf0102]
R374  1.2K, MELF  [smd_melf0102]
R375  1.2K, MELF  [smd_melf0102]
R376  1.2K, MELF  [smd_melf0102]
R377  0  [SM-7351-RES-0402]
R378  1.2K, MELF  [smd_melf0102]
R379  49.9  [smd_melf0102]
R380  0  [SM-7351-RES-0402]
R381  0  [SM-7351-RES-0402]
R382  25K  [SM-7351-RES-0603]
R383  2.2K  [sm-7351-res-0402]
R384  2.2K  [sm-7351-res-0402]
R385  0  [SM-7351-RES-0402]
R386  150  [SM-7351-RES-0402]
R387  0  [SM-7351-RES-0402]
R388  150  [SM-7351-RES-0402]
R389  150  [SM-7351-RES-0402]
R390  150  [SM-7351-RES-0402]
R391  150  [SM-7351-RES-0402]
R392  150  [SM-7351-RES-0402]
R393  0  [SM-7351-RES-0402]
R394  0  [SM-7351-RES-0402]
R395  150  [SM-7351-RES-0402]
R396  150  [SM-7351-RES-0402]
R800  10K  [SM-7351-RES-0402]
U28  SN74LVC1G07  [SC70-5-43M]
U72  SN65HVS882  [u_28_pwp]
U73  TPIC2810  [u_16_d]
sheet Pg22: JTAG Debug
C220  0.01uF  [SM-7351-CAP-0402]
C221  0.01uF  [SM-7351-CAP-0402]
C223  0.1uF  [SM-7351-CAP-0402]
C319  0.01uF  [SM-7351-CAP-0402]
C421  1uF  [SM-7351-CAP-0603]
J18  CTI JTAG  [header10x2]
R3  22  [SM-7351-RES-0402]
R149  10K  [SM-7351-RES-0402]
R421  DNI  [SM-7351-RES-0402]
R422  4.7K  [SM-7351-RES-0402]
R423  4.7K  [SM-7351-RES-0402]
R426  22  [SM-7351-RES-0402]
R429  100  [SM-7351-RES-0402]
R433  4.7K  [SM-7351-RES-0402]
R434  DNI  [SM-7351-RES-0402]
R435  18K  [SM-7351-RES-0402]
R436  18K  [SM-7351-RES-0402]
R437  DNI  [SM-7351-RES-0402]
R438  DNI  [SM-7351-RES-0402]
R439  DNI  [SM-7351-RES-0402]
R440  DNI  [SM-7351-RES-0402]
R441  DNI  [SM-7351-RES-0402]
R442  18K  [SM-7351-RES-0402]
R443  DNI  [SM-7351-RES-0402]
R444  DNI  [SM-7351-RES-0402]
R445  DNI  [SM-7351-RES-0402]
R446  DNI  [SM-7351-RES-0402]
R447  DNI  [SM-7351-RES-0402]
R448  DNI  [SM-7351-RES-0402]
R449  18K  [SM-7351-RES-0402]
R450  4.7K  [SM-7351-RES-0402]
R453  10K  [SM-7351-RES-0402]
R454  DNI  [SM-7351-RES-0402]
R455  DNI  [SM-7351-RES-0402]
R456  10K  [SM-7351-RES-0402]
R457  10K  [SM-7351-RES-0402]
R458  10K  [SM-7351-RES-0402]
R459  10K  [SM-7351-RES-0402]
R460  10K  [SM-7351-RES-0402]
R461  DNI  [SM-7351-RES-0402]
R462  10K  [SM-7351-RES-0402]
R463  10K  [SM-7351-RES-0402]
R464  10K  [SM-7351-RES-0402]
R465  10K  [SM-7351-RES-0402]
R466  10K  [SM-7351-RES-0402]
R467  10K  [SM-7351-RES-0402]
R468  DNI  [SM-7351-RES-0402]
R587  0  [SM-7351-RES-0402]
R730  100, 1%  [SM-7351-RES-0402]
R806  100  [SM-7351-RES-0402]
U19  SN74LVC1G04  [SC70-5-43M]
U33  CAT24C256W  [SOIC_8]
U78  SN74LVC1G07  [SC70-5-43M]
sheet Pg25: USB #1 3.0
C311  150uF  [SM-7351-CAP-2917]
C557  0.1uF  [SM-7351-CAP-0402]
C558  0.001uF  [SM-7351-CAP-0402]
J23  USB2_STD_A  [USB_STD_A_TH]
L11  ACM2012  [ACM2012H]
R551  10K  [SM-7351-RES-0402]
R553  10K  [SM-7351-RES-0402]
R557  0  [SM-7351-RES-0402]
R836  1M  [SM-7351-RES-0402]
U64  TPD2EUSB30  [SOT1X1-3-20M]
U66  TPS2065D  [U_8_D]
sheet Pg26: USB #2 2.0
C545  150uF  [SM-7351-CAP-2917]
C546  4.7uF  [SM-7351-CAP-0603]
C547  0.01uF  [SM-7351-CAP-0402]
C559  0.1uF  [SM-7351-CAP-0402]
C560  0.001uF  [SM-7351-CAP-0402]
J45  USB_MicroAB  [ZX62-AB-5PA]
J50  HEADER 2  [header_2x1]
L33  ACM2012  [ACM2012H]
M2  Shunt0.1in  [DNP]
R787  0  [SM-7351-RES-0402]
R788  100  [SM-7351-RES-0402]
R789  10K  [SM-7351-RES-0402]
R790  10K  [SM-7351-RES-0402]
R791  10K  [SM-7351-RES-0402]
R837  1M  [SM-7351-RES-0402]
U93  TPD4S012  [U_6_DRY]
U94  TPS2051BD  [U_8_D]
sheet Pg28: Profibus
C323  4.7uF  [sm-7351-cap-0805]
C325  4.7uF  [sm-7351-cap-0805]
C430  0.01uF  [SM-7351-CAP-0402]
C431  0.1uF  [SM-7351-CAP-0402]
C432  0.1uF  [SM-7351-CAP-0402]
C433  10uF  [SM-7351-CAP-0805]
C434  0.1uF  [SM-7351-CAP-0402]
C435  10uF  [SM-7351-CAP-1206]
D14  MBR0520LT1  [mbr0520L]
D15  MBR0520LT1  [mbr0520L]
J14  Conn_DB9F  [NorComp_db9F_SMD]
L2  DA2304-AL  [DA2304]
R573  0  [SM-7351-RES-0402]
R574  0  [SM-7351-RES-0402]
R575  0  [SM-7351-RES-0402]
R576  0  [SM-7351-RES-0402]
R577  100K  [SM-7351-RES-0402]
R578  100K  [SM-7351-RES-0402]
R579  2.2K  [sm-7351-res-0402]
U52  TPS76650  [soic_8]
U74  ISO1176T  [u_16_dw]
U80  TPD1E10B06  [tpd1e10b06-2l]
U81  TPD1E10B06  [tpd1e10b06-2l]
sheet Pg29: RS-485
U1  AM5718AABCXEA  [BGA23X23-760-117M]  (sections -1,-10,-11,-12,-13,-14,-15,-16,-17,-18,-19,-2,-20,-21,-22,-23,-24,-25,-26,-27,-3,-4,-5,-6,-7,-8,-9)

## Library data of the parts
PCB1 = 3M_AM571xIDKEVMBarePCBv1_2
C6 C433 C458 = 1C_10uFCapacitor16V10%0805
C7-C12 C29-C32 C34-C43 C48-C51 C55-C63 C65-C79 C81 C114 C115 C152 C195 C207 C210 C220 C221 C319 C400 C401 C403-C406 C430 C547 C548 = 1C_0.01uFCapacitor16V10%0402
C209 C286-C293 C296-C298 = 1C_1uFCapacitor10V10%0402
C441 = 1C_100uFCapacitor16V20%ElecPoly
C44-C47 C53 C54 C80 C82 C83 C223 C417 C454-C457 C460 C557 C559 = 1C_0.1uFCapacitor16V10%0402
J40-J43 J50 = 2H_Header_2x1
J46 = 2H_Header_4x1
R257 R258 R260-R265 R267 R269 R271 R273-R275 R277 R300 R367 R369 R371 R377 R380 R381 R385 R387 R393 R394 R557 R573-R576 R587 R638 R678 R679 R787 R797 R807 R905 R907-R910 = 1R_ZeroOhmResistor1_16W0402
R639 = 1R_0.05ohm0.5W1%Sense1206
R640 = 1R_0.047ohm0.5W1%Sense1206
R641 = 1R_0.015ohm0.5W0.5%Sense1206
R642 = 1R_0.024ohm0.5W1%Sense1206
R32-R35 R37-R40 R149 R259 R366 R421 R453-R468 R551 R553 R789-R791 R798 R800 = 1R_10KOhmResistor1_16W0402
SCKT1 = AM57XX_SOCKET
TP25 TP26 = 2H_TestPointThroughHole
U3 = 1A_TPS659040_Indus_2: PartName: TPS6590377
C268-C271 C276-C280 = 1C_47uFCapacitor10V20%SMD1206
C272-C275 C281-C285 C416 C546 = 1C_4.7uFCapacitor16V10%0603
C415 = 1C_0.1uFCapacitor16V10%0402: Installed: DNI
C33 C52 C64 C418 C419 = 1C_22uFCapacitor16V10%0805
C421 C459 = 1C_1uFCapacitor50V10%0603
C461 C462 = 1C_10uFCapacitor35V10%0805
C463 = 1C_1.1nFCapacitor50V5%0603
C205 C208 C471 C472 = 1C_2.2uF16V10%SMD0805
C476 = 1C_2.2uFCapacitor10V20%smd0402
D20 = 1E_Diode_1ARect_Rev20V: TIIntPartnumber: _1E0027
L12-L20 = 1L_1uHInductor20%4.5Alowprof
L22 = 1L_4.7uHInductor30%3.1Asmd
L28 = 1L_3.3uHInductor20%1.5Asmd
R419 R577 R578 = 1R_100KOhmResistor1_16W0402
R424 = 1R_1.62MOhmResistor1_16W0402
R427 = 1R_180KOhmResistor1_16W0402
R646 = 1R_51Kohm1_16W1%smd0402
R647 = 1R_158Kohm1_16W1%smd0402
R648 = 1R_18.2Kohm1_16W1%smd0402
R656 R742 = 1R_ZeroOhmResistor1_16W0603
R680 = 1R_10KOhmResistor1_10W1%0402
R681 = 1R_19.6KohmResistor1_16W1%0402
U62 = 1A_TPS63010YFF
U79 = 1A_TPS61085
U86 = 1A_LP38693ADJ
R41 R42 R44 = 1R_240OhmResistor1_16W0402
U5-U7 = 1A_MT41K256M16HA: MfrNum: MT41K256M16TW-107:P
C561 = 1C_47uFCapacitor16V20%1206
J9 = 2H_Header12x2
R276 R903 = 1R_ZeroOhmResistor1_16W0402: Cost100: 0.069; Cost10K: 0.00529; DescriptiveText: Resistor 22 ohm 1/16W 1% 0402; Mfr: ROHM; MfrNum: MCR01MZPF22R0; PartName: 22ohm1/161%smd0402; TIIntPartnumber: 1R0175
R902 = 1R_ZeroOhmResistor1_16W0402: DescriptiveText: Resistor 10Kohm 1/16W 5% 0402; Mfr: Rohm; MfrNum: MCR01MZPJ103; PartName: 10Kohm 1/16W 5%; TIIntPartnumber: 1R0168
X1 = OSC: DescriptiveText: Oscillator 20MHz 50ppm SMD7x5 3.3V; Mfr: CTS; MfrNum: CB3LV-3C-20M000; Vendor: Digikey
C196 C558 C560 = 1C_0.001uFCapacitor50V5%0402
C197-C204 = 1C_0.022uFCapacitor16Vsmd0402
C206 C435 = 1C_10uFCapacitor50V10%1206
D5-D12 = 1F_LED_Green
J37 = 2H_Header15x2_0.1in_Female
R368 R370 R372-R376 R378 = 1R_1.2Kohm1_3W1%SMDMELF0102
R379 = 49.9ohm1_3W1%SMDMELF0102
R382 = 1R_25Kohm1_10W0.1%smd0603
R383 R384 R579 = 1R_2.2KOhmResistor1_16W0402
R386 R388-R392 R395 R396 = 1R_150ohm1_16W1%SMD0402
U28 U78 = 1A_SN74LVC1G07
U72 = 1A_SN65HVS882
U73 = 1A_TPIC2810
J18 = 2H_Header10x2_CJTAG
R3 R426 = 1R_22OhmResistor1_16W1%0402
R422 R423 R433 R450 = 1R_4.7KOhmResistor1_16W0402
R429 R788 R806 = 1R_100ohm1_16W1%SMD0402
R434-R449 = 1R_18KohmResistor1_10W1%smd0402
R730 = 1R_100ohm1_10W1%SMD0402
U19 = 1A_SN74LVC1G04
U33 = 1A_CAT24C256W
C311 C545 = 1C_150uFCapacitor10V10%2917
J23 = 2C_Connector_USB3_0_A_0: DescriptiveText: Connector USB2 Standard A RA; Mfr: FCI; MfrNum: 87520-0010BLF; PartName: Connector_USB2_STD_A; TIIntPartnumber: 2C0017
L11 L33 = 1M_ACM2012
R836 R837 = 1R_1MOhmResistor1_16W0402
U64 = 1A_TPD2EUSB30DRT
U66 = 1A_TPS2065D
J45 = 2C_MicroUSBAB
M2 = 2H_Shunt0.1in
U93 = 1A_TPD4S012
U94 = 1A_TPS2051BD
C323 C325 = 4.7uFCapacitor16V20%Tant
C431 C432 C434 = 1C_0.1uFCapacitor50V10%0402
D14 D15 = Diode_500mA20V: TIIntPartnumber: _1E0007
J14 = 2C_Conn_DSUB9F
L2 = DA2304-ALB
U52 = TPS76650
U74 = 1A_ISO1176T
U80 U81 = 1A_TPD1E10B06
U1 = AM571X_ABCpkg_Industrial_10

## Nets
AGND_PROFI: J14.10 J14.11 R573.2(P2)
DGND: C6.2 C7.2 C8.2 C9.2 C10.2 C11.2 C12.2 C29.2 C30.2 C31.2 C32.2 C33.2 C34.2 C35.2 C36.2 C37.2 C38.2 C39.2 C40.2 C41.2 C42.2 C43.2 C45.2 C46.2 C48.2 C49.2 C50.2 C51.2 C52.2 C53.2 C54.2 C55.2 C56.2 C57.2 C58.2 C59.2 C60.2 C61.2 C62.2 C63.2 C64.2 C65.2 C66.2 C67.2 C68.2 C69.2 C70.2 C71.2 C72.2 C73.2 C74.2 C75.2 C76.2 C77.2 C78.2 C79.2 C81.2 C82.2 C83.2 C114.2 C115.2 C152.2 C195.2 C196.2 C197.2 C198.2 C199.2 C200.2 C201.2 C202.2 C203.2 C204.2 C205.2 C206.2 C207.2 C208.2 C209.2 C210.2 C220.2 C221.2 C223.2 C268.2 C269.2 C270.2 C271.2 C272.2 C273.2 C274.2 C275.2 C276.2 C277.2 C278.2 C279.2 C280.2 C281.2 C282.2 C283.2 C284.2 C285.2 C286.2 C287.2 C288.2 C289.2 C290.2 C291.2 C292.2 C293.2 C296.2 C297.2 C298.2 C311.2(NEG) C319.2 C400.2 C401.2 C403.2 C404.2 C405.2 C406.2 C415.2 C416.2 C417.2 C418.2 C419.2 C421.2 C432.2 C435.2 C441.2(NEG) C458.2 C459.2 C460.2 C461.2 C462.2 C463.2 C471.2 C472.2 C476.2 C545.2(NEG) C546.2 C547.2 C548.2 C557.1 C558.1 C559.1 C560.1 C561.2 J9.11 J9.12 J9.21 J18.8(GND) J18.12(GND) J18.16(GND) J18.20(GND) J23.4(GND) J37.17 J37.29 J37.30 J45.5(GND) J46.1 R32.2(P2) R33.2(P2) R34.2(P2) R35.2(P2) R37.2(P2) R38.2(P2) R39.2(P2) R40.2(P2) R41.1(P1) R42.1(P1) R44.1(P1) R380.1(P1) R381.1(P1) R382.1(P1) R427.1(P1) R433.1(P1) R453.1(P1) R454.1(P1) R455.1(P1) R456.1(P1) R457.1(P1) R458.1(P1) R459.1(P1) R460.1(P1) R461.1(P1) R462.1(P1) R463.1(P1) R464.1(P1) R465.1(P1) R466.1(P1) R467.1(P1) R468.1(P1) R553.2(P2) R579.1(P1) R587.2(P2) R648.1(P1) R680.1 R791.2(P2) R798.1(P1) R836.2(P2) R837.2(P2) SCKT1.MCH2 SCKT1.MCH4 U1.A1(VSS) U1.A2(VSS) U1.A6(VSS) U1.A14(VSS) U1.A23(VSS) U1.A28(VSS) U1.AA8(VSS) U1.AA9(VSS) U1.AA10(VSSA_CSI) U1.AA11(VSSA_USB) U1.AA14(VSS) U1.AA15(VSS) U1.AA20(VSS) U1.AB11(VSSA_USB) U1.AB14(VSS) U1.AB20(VSS) U1.AD1(VSS) U1.AD10(VSSA_USB3) U1.AD13(VSSA_PCIE) U1.AD19(VSSA_HDMI) U1.AD24(VSS) U1.AE10(VSSA_SATA) U1.AE13(VSSA_PCIE) U1.AE19(VSSA_HDMI) U1.AG1(VSS) U1.AH1(VSS) U1.AH2(VSS) U1.AH8(VSS_CSI) U1.AH20(VSS) U1.AH28(VSS) U1.B1(VSS) U1.D13(VSS) U1.D19(VSS) U1.E13(VSS) U1.E19(VSS) U1.F1(VSS) U1.F7(VSS) U1.G7(VSS) U1.G8(VSS) U1.G9(VSS) U1.H12(VSS) U1.J12(VSS) U1.J15(VSS) U1.J28(VSS) U1.K1(VSS) U1.K4(VSS) U1.K5(VSS) U1.K15(VSS) U1.K24(VSS) U1.K25(VSS) U1.L13(VSS) U1.L14(VSS) U1.M19(VSS) U1.N14(VSS) U1.N15(VSS) U1.N19(VSS) U1.N24(VSS) U1.N25(VSS) U1.P28(VSS) U1.R1(VSS) U1.R12(VSS) U1.R13(VSS) U1.R15(VSSA_VIDEO) U1.R21(VSS) U1.T10(VSS) U1.T11(VSS) U1.T12(VSS) U1.T14(VSS) U1.T15(VSS) U1.T17(VSS) U1.T18(VSS) U1.T21(VSS) U1.U14(VSS) U1.U15(VSS) U1.U17(VSS) U1.U20(VSS) U1.U21(VSS) U1.V15(VSS) U1.V17(VSS) U1.W1(VSS) U1.W15(VSS) U1.W24(VSS) U1.W25(VSS) U1.W28(VSS) U3.C12(SMPS12_FBK_GND) U3.D4(SMPS7_GND) U3.D5(SMPS7_GND) U3.D10(SMPS1_GND) U3.E4(SMPS7_GND) U3.E9(SMPS1_GND) U3.E10(SMPS1_GND) U3.F4(SMPS4_GND) U3.F9(SMPS2_GND) U3.F10(SMPS2_GND) U3.G4(SMPS4_GND) U3.G5(SMPS4_GND) U3.G10(SMPS2_GND) U3.H4(SMPS5_GND) U3.H5(SMPS5_GND) U3.H10(SMPS3_GND) U3.J4(SMPS5_GND) U3.J9(SMPS3_GND) U3.J10(SMPS3_GND) U3.K3(SMPS45_FDBK_GND) U3.L5(SMPS6_GND) U3.L6(SMPS6_GND) U3.L7(SMPS9_GND) U3.L8(SMPS9_GND) U3.L9(SMPS8_GND) U3.L10(SMPS8_GND) U5.A9(VSS) U5.B1(VSSQ) U5.B3(VSS) U5.B9(VSSQ) U5.D1(VSSQ) U5.D8(VSSQ) U5.E1(VSS) U5.E2(VSSQ) U5.E8(VSSQ) U5.F9(VSSQ) U5.G1(VSSQ) U5.G8(VSS) U5.G9(VSSQ) U5.J2(VSS) U5.J8(VSS) U5.M1(VSS) U5.M9(VSS) U5.P1(VSS) U5.P9(VSS) U5.T1(VSS) U5.T9(VSS) U6.A9(VSS) U6.B1(VSSQ) U6.B3(VSS) U6.B9(VSSQ) U6.C7(UDQS) U6.D1(VSSQ) U6.D3(UDM) U6.D8(VSSQ) U6.E1(VSS) U6.E2(VSSQ) U6.E8(VSSQ) U6.F9(VSSQ) U6.G1(VSSQ) U6.G8(VSS) U6.G9(VSSQ) U6.J2(VSS) U6.J8(VSS) U6.M1(VSS) U6.M9(VSS) U6.P1(VSS) U6.P9(VSS) U6.T1(VSS) U6.T9(VSS) U7.A9(VSS) U7.B1(VSSQ) U7.B3(VSS) U7.B9(VSSQ) U7.D1(VSSQ) U7.D8(VSSQ) U7.E1(VSS) U7.E2(VSSQ) U7.E8(VSSQ) U7.F9(VSSQ) U7.G1(VSSQ) U7.G8(VSS) U7.G9(VSSQ) U7.J2(VSS) U7.J8(VSS) U7.M1(VSS) U7.M9(VSS) U7.P1(VSS) U7.P9(VSS) U7.T1(VSS) U7.T9(VSS) U19.3(GND) U28.3(GND) U33.1(A0) U33.2(A1) U33.3(A2) U33.4(VSS) U62.B4(SYNC) U62.C1(PGND) U62.C2(PGND) U62.C3(GND) U62.D3(GND) U62.E4(GND) U64.3(GND) U66.1(GND) U72.28(GND) U72.TH_PD(THRM) U73.7(A2) U73.8(~{G}) U73.9(A0) U73.10(A1) U73.16(GND) U74.3(GND1) U78.3(GND) U79.4(GND) U86.5(GND) U93.4(GND) U94.1(GND) X1.2(GND) ; also on sheet 1 2 3 4 5 6 7 8 9 20 21 22 23 24 25 26 27 28 29 30 31 32
GNDPROFI: C323.2(NEG) C325.2(NEG) C430.2 C431.2 C433.2 C434.2 J14.5 L2.6 L2.7 R573.1(P1) R578.1(P1) U52.3(GND) U52.4(~{EN}) U74.9(GND2) U74.11(GND2) U74.14(GND2) U74.15(GND2) U80.2 U81.2
GNDUSB1: C557.2 C558.2 J23.S1 J23.S2 R836.1(P1)
GNDUSB2: C559.2 C560.2 J45.S1 J45.S2 J45.S3 J45.S4 R837.1(P1)
V1_8D: C405.1 C406.1 R910.2(P2) U1.AA7(VDDS_MLBP) U1.AA18(VDDS18V_DDR1) U1.AA19(VDDS18V_DDR1) U1.G18(VDDS18V) U1.H17(VDDS18V) U1.M8(VDDS18V) U1.M9(VDDS18V) U1.N8(VDDS18V) U1.P8(VDDS18V) U1.P20(VDDS18V_DDR1) U1.P21(VDDS18V_DDR1) U1.R8(VDDS18V) U1.T8(VDDS18V) U1.V21(VDDS18V) U1.V22(VDDS18V) U1.W17(VDDS18V) U1.W18(VDDS18V) U1.W21(VDDS18V_DDR1) U1.Y7(VDDS_MLBP) U1.Y21(VDDS18V_DDR1) ; also on sheet 4 9 26 27 31
V1_8PHY_HDMI: U1.Y17(VDDA_HDMI) ; also on sheet 31
V1_8PHY_PCIE: U1.AA16(VDDA_PCIE0) U1.AA17(VDDA_PCIE) U1.W14(VDDA_USB3) ; also on sheet 31
V1_8PHY_SATA: U1.V13(VDDA_SATA) ; also on sheet 31
V1_8PHY_USB: U1.AA13(VDDA_USB1) U1.AB12(VDDA_USB2) U1.W12(VDDA_CSI) ; also on sheet 31
V1_8PLL: U1.AD16(VDDA_OSC) U1.AE16(VDDA_OSC) ; also on sheet 9 31
V1_8PLLA: U1.M14(VDDA_PER) U1.N16(VDDA_MPU_ABE) U1.R14(VDDA_GPU) U1.R17(VDDA_DDR) ; also on sheet 31
V1_8PLLB: U1.N11(VDDA_DEBUG) U1.N12(VDDA_DSP_IVA) U1.P14(VDDA_CORE_GMAC) U1.P15(VDDA_PLL_SPARE) U1.P16(VDDA_VIDEO) ; also on sheet 31
V3_3D: C209.1 C210.1 C220.1 C221.1 C319.1 C432.1 C435.1 J46.3 L2.2 L2.3 R149.2(P2) R259.2(P2) R366.2(P2) R383.2(P2) R384.2(P2) R419.2(P2) R421.2(P2) R422.2(P2) R423.2(P2) R434.2(P2) R435.2(P2) R436.2(P2) R437.2(P2) R438.2(P2) R439.2(P2) R440.2(P2) R441.2(P2) R442.2(P2) R443.2(P2) R444.2(P2) R445.2(P2) R446.2(P2) R447.2(P2) R448.2(P2) R449.2(P2) R450.2(P2) R551.2(P2) R678.2(P2) R679.2(P2) R730.2(P2) R742.1(P1) R789.2(P2) R790.2(P2) R800.2(P2) R902.2(P2) U1.AB6(VDDSHV7) U1.AB7(VDDSHV7) U1.AD5(VDDSHV6) U1.AD7(VDDSHV6) U1.AE7(VDDSHV6) U1.AF5(VDDSHV6) U1.B6(VDDSHV2) U1.B23(VDDSHV3) U1.C24(VDDSHV4) U1.D10(VDDSHV2) U1.D16(VDDSHV3) U1.D22(VDDSHV3) U1.E3(VDDSHV1) U1.E5(VDDSHV1) U1.E10(VDDSHV2) U1.E16(VDDSHV3) U1.E22(VDDSHV3) U1.G4(VDDSHV1) U1.G5(VDDSHV1) U1.G15(VDDSHV3) U1.H8(VDDSHV1) U1.H9(VDDSHV1) U1.H10(VDDSHV2) U1.H11(VDDSHV2) U1.H15(VDDSHV3) U1.H16(VDDSHV3) U1.H18(VDDSHV3) U1.H19(VDDSHV3) U1.J8(VDDSHV11) U1.K8(VDDSHV11) U1.N4(VDDSHV10) U1.N5(VDDSHV10) U1.P10(VDDSHV10) U1.R7(VDDSHV10) U1.R10(VDDSHV10) U1.T4(VDDSHV10) U1.T5(VDDSHV10) U1.U10(VDDSHV9) U1.V12(VDDSHV5) U1.W4(VDDSHV9) U1.W5(VDDSHV9) U3.J8(SMPS9_FBK) U19.5(VCC) U33.8(VCC) U73.1(VCC) U74.4(VCC1) U78.5(VCC) X1.4(VCC) ; also on sheet 1 2 3 4 5 6 7 8 9 20 21 22 23 24 25 26 27 28 29 30 31 32
V3_3D_PROFIA: L2.4 U74.1(D1)
V3_3D_PROFIB: L2.1 U74.2(D2)
V3_3USB: C400.1 C401.1 U1.AA12(VDDA33V_USB1) U1.Y12(VDDA33V_USB2) ; also on sheet 9
V3_7LCD: C472.1 R681.1 U86.3(VOUT) ; also on sheet 4
V5_0D: C208.1 C418.1 C419.1 C476.1 J37.27 J37.28 R386.1(P1) R388.1(P1) R389.1(P1) R390.1(P1) R391.1(P1) R392.1(P1) R395.1(P1) R396.1(P1) R424.2(P2) U62.E1(VOUT) U62.E2(VOUT) U66.2(IN) U66.3(IN) U94.2(IN) U94.3(IN) ; also on sheet 5 29
V5_0D_EN: R419.1(P1) U62.A4(EN)
V5_0DFB: R424.1(P1) R427.2(P2) U62.E3(FB)
V5_0VOP: C195.1 C205.1 C207.1 U28.5(VCC) U72.15(5VOP)
V12_0D: C196.1 C461.1 C462.1 D20.1(CATHODE) J37.2 J37.4 J37.6 J37.8 J37.10 J37.12 J37.14 J37.16 R379.2(P2) R647.2(P2) ; also on sheet 20
VDD_CORE: R640.2(I2) R908.2(P2) U1.H13(VDD) U1.H14(VDD) U1.J17(VDD) U1.J18(VDD) U1.L7(VDD) U1.L8(VDD) U1.N10(VDD) U1.N13(VDD) U1.P11(VDD) U1.P12(VDD) U1.P13(VDD) U1.R11(VDD) U1.R16(VDD) U1.R19(VDD) U1.T13(VDD) U1.T16(VDD) U1.T19(VDD) U1.U8(VDD) U1.U9(VDD) U1.U13(VDD) U1.U16(VDD) U1.V8(VDD) U1.V16(VDD) U3.B1(SMPS7_FDBK) ; also on sheet 31
VDD_DSP: R807.1(P1) TP25.1 U1.K10(VDD_DSP) U1.K11(VDD_DSP) U1.L10(VDD_DSP) U1.L11(VDD_DSP) U1.M10(VDD_DSP) U1.M11(VDD_DSP) ; also on sheet 31
VDD_GPU: C268.1 L17.2 U1.U11(VDD_GPU) U1.U12(VDD_GPU) U1.V10(VDD_GPU) U1.V11(VDD_GPU) U1.V14(VDD_GPU) U1.W10(VDD_GPU) U1.W11(VDD_GPU) U1.W13(VDD_GPU) U3.K6(SMPS6_FBK) ; also on sheet 31
VDD_IVA: R642.2(I2) R807.2(P2) U1.J13(VDD_IVA) U1.K12(VDD_IVA) U1.K13(VDD_IVA) U1.L12(VDD_IVA) U1.M12(VDD_IVA) U1.M13(VDD_IVA) U3.K2(SMPS45_FDBK) ; also on sheet 31
VDD_MPU: R641.2(I2) U1.K17(VDD_MPU) U1.K18(VDD_MPU) U1.L15(VDD_MPU) U1.L16(VDD_MPU) U1.L17(VDD_MPU) U1.L18(VDD_MPU) U1.L19(VDD_MPU) U1.M15(VDD_MPU) U1.M16(VDD_MPU) U1.M17(VDD_MPU) U1.M18(VDD_MPU) U1.N17(VDD_MPU) U1.N18(VDD_MPU) U1.P17(VDD_MPU) U1.P18(VDD_MPU) U1.R18(VDD_MPU) U3.B13(SMPS12_FBK) ; also on sheet 31
VDD_RTC: R907.2(P2) ; also on sheet 9
VDDR_VREF: C44.2 C45.1 C46.1 C47.2 C53.1 C54.1 C80.2 C81.1 C82.1 C83.1 U1.Y18(DDR1_VREF) U5.H1(VREFDQ) U5.M8(VREFCA) U6.H1(VREFDQ) U6.M8(VREFCA) U7.H1(VREFDQ) U7.M8(VREFCA) ; also on sheet 8
VDDS_DDR: C29.1 C30.1 C31.1 C32.1 C33.1 C34.1 C35.1 C36.1 C37.1 C38.1 C39.1 C40.1 C41.1 C42.1 C43.1 C44.1 C47.1 C48.1 C49.1 C50.1 C51.1 C52.1 C55.1 C56.1 C57.1 C58.1 C59.1 C60.1 C61.1 C62.1 C63.1 C64.1 C65.1 C66.1 C67.1 C68.1 C69.1 C70.1 C71.1 C72.1 C73.1 C74.1 C75.1 C76.1 C77.1 C78.1 C79.1 C80.1 R639.1(I1) R656.1(P1) U5.A1(VDDQ) U5.A8(VDDQ) U5.B2(VDD) U5.C1(VDDQ) U5.C9(VDDQ) U5.D2(VDDQ) U5.D9(VDD) U5.E9(VDDQ) U5.F1(VDDQ) U5.G7(VDD) U5.H2(VDDQ) U5.H9(VDDQ) U5.K2(VDD) U5.K8(VDD) U5.N1(VDD) U5.N9(VDD) U5.R1(VDD) U5.R9(VDD) U6.A1(VDDQ) U6.A8(VDDQ) U6.B2(VDD) U6.B7(UDQSn) U6.C1(VDDQ) U6.C9(VDDQ) U6.D2(VDDQ) U6.D9(VDD) U6.E9(VDDQ) U6.F1(VDDQ) U6.G7(VDD) U6.H2(VDDQ) U6.H9(VDDQ) U6.K2(VDD) U6.K8(VDD) U6.N1(VDD) U6.N9(VDD) U6.R1(VDD) U6.R9(VDD) U7.A1(VDDQ) U7.A8(VDDQ) U7.B2(VDD) U7.C1(VDDQ) U7.C9(VDDQ) U7.D2(VDDQ) U7.D9(VDD) U7.E9(VDDQ) U7.F1(VDDQ) U7.G7(VDD) U7.H2(VDDQ) U7.H9(VDDQ) U7.K2(VDD) U7.K8(VDD) U7.N1(VDD) U7.N9(VDD) U7.R1(VDD) U7.R9(VDD) ; also on sheet 8
AM57XX_CLKOUT3: R905.2(P2) U1.C23(XREF_CLK3/CLKOUT3)
AM57XX_GPMC_AD0: R434.1(P1) R453.2(P2) ; also on sheet 29
AM57XX_GPMC_AD1: R435.1(P1) R454.2(P2) ; also on sheet 29
AM57XX_GPMC_AD2: R436.1(P1) R455.2(P2) ; also on sheet 29
AM57XX_GPMC_AD3: R437.1(P1) R456.2(P2) ; also on sheet 29
AM57XX_GPMC_AD4: R438.1(P1) R457.2(P2) ; also on sheet 29
AM57XX_GPMC_AD5: R439.1(P1) R458.2(P2) ; also on sheet 29
AM57XX_GPMC_AD6: R440.1(P1) R459.2(P2) ; also on sheet 29
AM57XX_GPMC_AD7: R441.1(P1) R460.2(P2) ; also on sheet 29
AM57XX_GPMC_AD8: R442.1(P1) R461.2(P2) ; also on sheet 29
AM57XX_GPMC_AD9: R443.1(P1) R462.2(P2) ; also on sheet 29
AM57XX_GPMC_AD10: R444.1(P1) R463.2(P2) ; also on sheet 29
AM57XX_GPMC_AD11: R445.1(P1) R464.2(P2) ; also on sheet 29
AM57XX_GPMC_AD12: R446.1(P1) R465.2(P2) ; also on sheet 29
AM57XX_GPMC_AD13: R447.1(P1) R466.2(P2) ; also on sheet 29
AM57XX_GPMC_AD14: R448.1(P1) R467.2(P2) ; also on sheet 29
AM57XX_GPMC_AD15: R449.1(P1) R468.2(P2) ; also on sheet 29
AM57XX_I2C1_SCL: R384.1(P1) R385.2(P2) R393.2(P2) U1.C20(I2C1_SCL)
AM57XX_I2C1_SDA: R383.1(P1) R387.2(P2) R394.2(P2) U1.C21(I2C1_SDA)
AM57XX_PR1_UART0_RXD: R575.2(P2) U1.F2(VIN2A_D0/PR1_UART0_RXD) ; also on sheet 29
AM57XX_PR1_UART0_TXD: R574.2(P2) U1.F3(VIN2A_D1/PR1_UART0_TXD) ; also on sheet 24 29
AM57XX_PR2_PROFI_TXEN: U1.U3(RMII50MHZCLK/PR2_GPIO) ; also on sheet 29
AM57XX_RTCK: R426.2(P2) U1.E18(RTCK)
AM57XX_SPI1_CS0: R369.2(P2) U1.D17(MCASP4_AXR1/SPI3_CS0)
AM57XX_SPI1_D1: R377.2(P2) U1.A21(MCASP4_FSX/SPI3_D1)
AM57XX_SPI1_SCLK: R367.2(P2) U1.C18(MCASP4_ACLKX/SPI3_SCLK)
AM57XX_USB1_DM: L11.1 U1.AC12(USB1_DM)
AM57XX_USB1_DP: L11.2 U1.AD12(USB1_DP)
AM57XX_USB1_DRVVBUS: R557.2(P2) U1.AB10(USB1_DRVVBUS)
AM57XX_VIN1B_DATA0: R260.2(P2) U1.R6(GPMC_A0/VIN1B_D0)
AM57XX_VIN1B_DATA1: R261.2(P2) U1.T9(GPMC_A1/VIN1B_D1)
AM57XX_VIN1B_DATA2: R263.2(P2) U1.T6(GPMC_A2/VIN1B_D2)
AM57XX_VIN1B_DATA3: R267.2(P2) U1.T7(GPMC_A3/VIN1B_D3)
AM57XX_VIN1B_DATA4: R269.2(P2) U1.P6(GPMC_A4/VIN1B_D4)
AM57XX_VIN1B_DATA5: R271.2(P2) U1.R9(GPMC_A5/VIN1B_D5)
AM57XX_VIN1B_DATA6: R262.1(P1) U1.R5(GPMC_A6/VIN1B_D6)
AM57XX_VIN1B_DATA7: R264.1(P1) U1.P5(GPMC_A7/VIN1B_D7)
AM57XX_VIN1B_DE: R273.2(P2) U1.P9(GPMC_A11/VIN1B_DE1)
AM57XX_VIN1B_FLD: R274.1(P1) U1.P4(GPMC_A12/VIN1B_FLD1)
AM57XX_VIN1B_HSYNC: R258.1(P1) U1.N7(GPMC_A8/VIN1B_HSYNC1)
AM57XX_VIN1B_PCLK: R265.2(P2) U1.N9(GPMC_A10/VIN1B_CLK1)
AM57XX_VIN1B_VSYNC: R257.1(P1) U1.R4(GPMC_A9/VIN1B_VSYNC1)
AM571X_PRU1ETH1_TXD0: R576.2(P2) ; also on sheet 22 29
AM572X_USB2_DM: L33.2 U1.AF11(USB2_DM)
AM572X_USB2_DP: L33.1 U1.AE11(USB2_DP)
AM572X_USB2_DRVVBUS: R787.2(P2) U1.AC10(USB2_DRVVBUS)
CAM1_DATA0: J9.3 R260.1(P1)
CAM1_DATA1: J9.5 R261.1(P1)
CAM1_DATA2: J9.7 R263.1(P1)
CAM1_DATA3: J9.13 R267.1(P1)
CAM1_DATA4: J9.15 R269.1(P1)
CAM1_DATA5: J9.17 R271.1(P1)
CAM1_DATA6: J9.6 R262.2(P2)
CAM1_DATA7: J9.8 R264.2(P2)
CAM1_FIELD: J9.20 R274.2(P2)
CAM1_GIO0: J9.16 R259.1(P1)
CAM1_HSYNC: J9.4 R258.2(P2)
CAM1_PCLK: J9.9 R265.1(P1)
CAM1_VSYNC: J9.2 R257.2(P2)
CAM1_WEN: J9.19 R273.1(P1)
CAM_ENn: J9.18 ; also on sheet 29
DDR_A0: U1.AD20(DDR1_A0) U5.N3(A0) U6.N3(A0) U7.N3(A0) ; also on sheet 8
DDR_A1: U1.AC19(DDR1_A1) U5.P7(A1) U6.P7(A1) U7.P7(A1) ; also on sheet 8
DDR_A2: U1.AC20(DDR1_A2) U5.P3(A2) U6.P3(A2) U7.P3(A2) ; also on sheet 8
DDR_A3: U1.AB19(DDR1_A3) U5.N2(A3) U6.N2(A3) U7.N2(A3) ; also on sheet 8
DDR_A4: U1.AF21(DDR1_A4) U5.P8(A4) U6.P8(A4) U7.P8(A4) ; also on sheet 8
DDR_A5: U1.AH22(DDR1_A5) U5.P2(A5) U6.P2(A5) U7.P2(A5) ; also on sheet 8
DDR_A6: U1.AG23(DDR1_A6) U5.R8(A6) U6.R8(A6) U7.R8(A6) ; also on sheet 8
DDR_A7: U1.AE21(DDR1_A7) U5.R2(A7) U6.R2(A7) U7.R2(A7) ; also on sheet 8
DDR_A8: U1.AF22(DDR1_A8) U5.T8(A8) U6.T8(A8) U7.T8(A8) ; also on sheet 8
DDR_A9: U1.AE22(DDR1_A9) U5.R3(A9) U6.R3(A9) U7.R3(A9) ; also on sheet 8
DDR_A10: U1.AD21(DDR1_A10) U5.L7(A10/AP) U6.L7(A10/AP) U7.L7(A10/AP) ; also on sheet 8
DDR_A11: U1.AD22(DDR1_A11) U5.R7(A11) U6.R7(A11) U7.R7(A11) ; also on sheet 8
DDR_A12: U1.AC21(DDR1_A12) U5.N7(A12/~{BC}) U6.N7(A12/~{BC}) U7.N7(A12/~{BC}) ; also on sheet 8
DDR_A13: U1.AF18(DDR1_A13) U5.T3(A13) U6.T3(A13) U7.T3(A13) ; also on sheet 8
DDR_A14: U1.AE17(DDR1_A14) U5.T7(A14) U6.T7(A14) U7.T7(A14) ; also on sheet 8
DDR_BA0: U1.AF17(DDR1_BA0) U5.M2(BA0) U6.M2(BA0) U7.M2(BA0) ; also on sheet 8
DDR_BA1: U1.AE18(DDR1_BA1) U5.N8(BA1) U6.N8(BA1) U7.N8(BA1) ; also on sheet 8
DDR_BA2: U1.AB18(DDR1_BA2) U5.M3(BA2) U6.M3(BA2) U7.M3(BA2) ; also on sheet 8
DDR_CASn: U1.AC18(DDR1_CASn) U5.K3(CASn) U6.K3(CASn) U7.K3(CASn) ; also on sheet 8
DDR_CKE: U1.AG22(DDR1_CKE) U5.K9(CKE) U6.K9(CKE) U7.K9(CKE) ; also on sheet 8
DDR_CLK: U1.AG24(DDR1_CK) U5.J7(CK) U6.J7(CK) U7.J7(CK) ; also on sheet 8
DDR_CLKn: U1.AH24(DDR1_CKn) U5.K7(CKn) U6.K7(CKn) U7.K7(CKn) ; also on sheet 8
DDR_CS0n: U1.AH23(DDR1_CSN0) U5.L2(CSn) U6.L2(CSn) U7.L2(CSn) ; also on sheet 8
DDR_D0: U1.AF25(DDR1_D0) U5.E3(DQ0)
DDR_D1: U1.AF26(DDR1_D1) U5.F7(DQ1)
DDR_D2: U1.AG26(DDR1_D2) U5.F8(DQ3)
DDR_D3: U1.AH26(DDR1_D3) U5.H8(DQ5)
DDR_D4: U1.AF24(DDR1_D4) U5.F2(DQ2)
DDR_D5: U1.AE24(DDR1_D5) U5.G2(DQ6)
DDR_D6: U1.AF23(DDR1_D6) U5.H3(DQ4)
DDR_D7: U1.AE23(DDR1_D7) U5.H7(DQ7)
DDR_D8: U1.AC23(DDR1_D8) U5.D7(DQ8)
DDR_D9: U1.AF27(DDR1_D9) U5.C3(DQ9)
DDR_D10: U1.AG27(DDR1_D10) U5.A3(DQ15)
DDR_D11: U1.AF28(DDR1_D11) U5.A7(DQ12)
DDR_D12: U1.AE26(DDR1_D12) U5.A2(DQ13)
DDR_D13: U1.AC25(DDR1_D13) U5.C8(DQ10)
DDR_D14: U1.AC24(DDR1_D14) U5.B8(DQ14)
DDR_D15: U1.AD25(DDR1_D15) U5.C2(DQ11)
DDR_D16: U1.V20(DDR1_D16) U7.E3(DQ0)
DDR_D17: U1.W20(DDR1_D17) U7.H8(DQ5)
DDR_D18: U1.AB28(DDR1_D18) U7.H3(DQ4)
DDR_D19: U1.AC28(DDR1_D19) U7.G2(DQ6)
DDR_D20: U1.AC27(DDR1_D20) U7.F2(DQ2)
DDR_D21: U1.Y19(DDR1_D21) U7.F7(DQ1)
DDR_D22: U1.AB27(DDR1_D22) U7.H7(DQ7)
DDR_D23: U1.Y20(DDR1_D23) U7.F8(DQ3)
DDR_D24: U1.AA23(DDR1_D24) U7.D7(DQ8)
DDR_D25: U1.Y22(DDR1_D25) U7.C3(DQ9)
DDR_D26: U1.Y23(DDR1_D26) U7.B8(DQ14)
DDR_D27: U1.AA24(DDR1_D27) U7.A2(DQ13)
DDR_D28: U1.Y24(DDR1_D28) U7.C2(DQ11)
DDR_D29: U1.AA26(DDR1_D29) U7.A7(DQ12)
DDR_D30: U1.AA25(DDR1_D30) U7.C8(DQ10)
DDR_D31: U1.AA28(DDR1_D31) U7.A3(DQ15)
DDR_DQM0: U1.AD23(DDR1_DQM0) U5.E7(LDM)
DDR_DQM1: U1.AB23(DDR1_DQM1) U5.D3(UDM)
DDR_DQM2: U1.AC26(DDR1_DQM2) U7.E7(LDM)
DDR_DQM3: U1.AA27(DDR1_DQM3) U7.D3(UDM)
DDR_DQS0: U1.AH25(DDR1_DQS0) U5.F3(LDQS)
DDR_DQS1: U1.AE27(DDR1_DQS1) U5.C7(UDQS)
DDR_DQS2: U1.AD27(DDR1_DQS2) U7.F3(LDQS)
DDR_DQS3: U1.Y28(DDR1_DQS3) U7.C7(UDQS)
DDR_DQSn0: U1.AG25(DDR1_DQS0n) U5.G3(LDQSn)
DDR_DQSn1: U1.AE28(DDR1_DQS1n) U5.B7(UDQSn)
DDR_DQSn2: U1.AD28(DDR1_DQS2n) U7.G3(LDQSn)
DDR_DQSn3: U1.Y27(DDR1_DQS3n) U7.B7(UDQSn)
DDR_ODT: U1.AE20(DDR1_ODT0) U5.K1(ODT) U6.K1(ODT) U7.K1(ODT) ; also on sheet 8
DDR_RASn: U1.AF20(DDR1_RASn) U5.J3(RASn) U6.J3(RASn) U7.J3(RASn) ; also on sheet 8
DDR_RESETn: U1.AG21(DDR1_RST) U5.T2(RESETn) U6.T2(RESETn) U7.T2(RESETn)
DDR_WEn: U1.AH21(DDR1_WEn) U5.L3(WEn) U6.L3(WEn) U7.L3(WEn) ; also on sheet 8
DDRECC_D0: U1.W22(DDR1_ECC_D0) U6.E3(DQ0)
DDRECC_D1: U1.V23(DDR1_ECC_D1) U6.F7(DQ1)
DDRECC_D2: U1.W19(DDR1_ECC_D2) U6.H8(DQ5)
DDRECC_D3: U1.W23(DDR1_ECC_D3) U6.F8(DQ3)
DDRECC_D4: U1.Y25(DDR1_ECC_D4) U6.F2(DQ2)
DDRECC_D5: U1.V24(DDR1_ECC_D5) U6.H7(DQ7)
DDRECC_D6: U1.V25(DDR1_ECC_D6) U6.H3(DQ4)
DDRECC_D7: U1.Y26(DDR1_ECC_D7) U6.G2(DQ6)
DDRECC_DQM: U1.V26(DDR1_ECC_DQM) U6.E7(LDM)
DDRECC_DQS: U1.V27(DDR1_ECC_DQS) U6.F3(LDQS)
DDRECC_DQSn: U1.V28(DDR1_ECC_DQSn) U6.G3(LDQSn)
DRAIN0: D5.1(Cathode) J37.19 U73.3(DRAIN0)
DRAIN1: D6.1(Cathode) J37.20 U73.4(DRAIN1)
DRAIN2: D7.1(Cathode) J37.21 U73.5(DRAIN2)
DRAIN3: D8.1(Cathode) J37.22 U73.6(DRAIN3)
DRAIN4: D9.1(Cathode) J37.23 U73.11(DRAIN4)
DRAIN5: D10.1(Cathode) J37.24 U73.12(DRAIN5)
DRAIN6: D11.1(Cathode) J37.25 U73.13(DRAIN6)
DRAIN7: D12.1(Cathode) J37.26 U73.14(DRAIN7)
EMU_RSTn: C223.1 J18.15(SRST) R429.2(P2) R450.1(P1)
GPIO_AM572X_USB2_ID: R788.2(P2) U1.F13(MCASP1_AXR5/GPIO)
GPIO_IND_LDn: R371.2(P2) R800.1(P1) ; also on sheet 29
GPIO_VPP_PWR_EN: R638.2(P2) ; also on sheet 29
HDQ: R300.1(P1) ; also on sheet 29
IND_I2C_SCL: R275.1(P1) R393.1(P1) U33.6(SCL) ; also on sheet 4 9 20 27 29
IND_I2C_SDA: R277.1(P1) R394.1(P1) U33.5(SDA) ; also on sheet 4 9 20 27 29
INDUS_INPUT0: J37.1 R368.1(P1)
INDUS_INPUT1: J37.3 R370.1(P1)
INDUS_INPUT2: J37.5 R372.1(P1)
INDUS_INPUT3: J37.7 R374.1(P1)
INDUS_INPUT4: J37.9 R373.1(P1)
INDUS_INPUT5: J37.11 R375.1(P1)
INDUS_INPUT6: J37.13 R376.1(P1)
INDUS_INPUT7: J37.15 R378.1(P1)
INDUS_INPUTCLK: R367.1(P1) U72.25(CLK)
INDUS_INPUTCSn: R369.1(P1) U72.24(~{CE})
INDUS_INPUTLDn: R371.1(P1) U72.26(~{LD})
INDUS_INPUTSO: U28.2(A) U72.23(SOP)
JTAG_EMU0: J18.13(EMU0) R422.1(P1) U1.G21(EMU0) ; also on sheet 1
JTAG_EMU1: J18.14(EMU1) R423.1(P1) U1.D24(EMU1) ; also on sheet 1
JTAG_TCK: R3.2(P2) U1.E20(TCK) ; also on sheet 1
JTAG_TDI: J18.3(TDI) U1.D23(TDI) ; also on sheet 1
JTAG_TDO: J18.7(TDO) U1.F19(TDO) ; also on sheet 1
JTAG_TMS: J18.1(TMS) U1.F18(TMS) ; also on sheet 1
JTAG_TRSTn: J18.2(TRSTn) R433.2(P2) U1.D20(TRSTn) ; also on sheet 1
JTAGPOD_PRES: U19.4(Y) ; also on sheet 1
PROFIBUS_A: J14.3 R577.1(P1) U74.12(A) U81.1
PROFIBUS_B: J14.8 R578.2(P2) U74.13(B) U80.1
RTCK: J18.9(TCKRTN) R426.1(P1)
SRCCLK: R276.1(P1) ; also on sheet 4
SYS_WARMRESETn: U78.4(Y) ; also on sheet 1 30
TCK: J18.11(TCK) R3.1(P1)
USB1_CONN_DM: J23.2(DM) L11.4 U64.2(D-)
USB1_CONN_DP: J23.3(DP) L11.3 U64.1(D+)
USB1_OVRCURn: R551.1(P1) U66.5(~{OC})
USB1_VBUS_EN: R553.1(P1) R557.1(P1) U66.4(EN)
USB2_CONN_DM: J45.2(DM) L33.3 U93.2(D-)
USB2_CONN_DP: J45.3(DP) L33.4 U93.1(D+)
USB2_ID: J45.4(ID) R788.1(P1) R789.1(P1) U93.3(ID)
USB2_OVRCURn: R790.1(P1) U94.5(~{OC})
USB2_VBUS_EN: R787.1(P1) R791.1(P1) U94.4(EN)
VAM572X_DDR1: C6.1 C7.1 C8.1 C9.1 C10.1 C11.1 C12.1 C114.1 C115.1 C441.1(POS) R639.2(I2) U1.AA21(VDDS_DDR1) U1.AA22(VDDS_DDR1) U1.AB21(VDDS_DDR1) U1.AB22(VDDS_DDR1) U1.AB24(VDDS_DDR1) U1.AB25(VDDS_DDR1) U1.AC22(VDDS_DDR1) U1.AD26(VDDS_DDR1) U1.AG20(VDDS_DDR1) U1.AG28(VDDS_DDR1) U1.AH27(VDDS_DDR1) U1.T24(VDDS_DDR1) U1.T25(VDDS_DDR1) U1.W16(VDDS_DDR1) U1.W27(VDDS_DDR1) U3.K13(SMPS3_FDBK)
VMAIN: C152.1 C272.1 C273.1 C274.1 C275.1 C281.1 C282.1 C283.1 C284.1 C285.1 C415.1 C416.1 C458.1 C459.1 C471.1 C561.1 J9.1 L28.1 U3.D11(SMPS1_IN_1) U3.D12(SMPS1_IN_2) U3.D13(SMPS1_IN_3) U3.E1(SMPS7_IN_B1_1) U3.E2(SMPS7_IN_B1_2) U3.E3(SMPS7_IN_B1_3) U3.F1(SMPS4_IN1) U3.F2(SMPS4_IN2) U3.F3(SMPS4_IN3) U3.G11(SMPS2_IN_1) U3.G12(SMPS2_IN_2) U3.G13(SMPS2_IN_3) U3.H11(SMPS3_IN1) U3.H12(SMPS3_IN2) U3.H13(SMPS3_IN3) U3.J1(SMPS5_IN1) U3.J2(SMPS5_IN2) U3.J3(SMPS5_IN3) U3.M6(SMPS6_IN) U3.M8(SMPS9_IN) U3.M9(SMPS8_IN) U3.N6(SMPS6_IN) U3.N8(SMPS9_IN) U3.N9(SMPS8_IN) U62.A1(VIN) U62.A2(VIN) U79.6(IN) U79.7(FREQ) U86.4(VIN) ; also on sheet 4 9 29
VPP_CONN: J46.2 R797.1(P1)
VPROFI: C323.1(POS) C325.1(POS) C430.1 C431.1 J14.6 R577.2(P2) U52.7(OUT) U52.8(OUT) U74.16(VCC2)
VPROFI_SRC: C433.1 C434.1 D14.1(CATHODE) D15.1(CATHODE) U52.5(IN) U52.6(IN)
VPROFI_TRANSA: D15.2(ANODE) L2.8
VPROFI_TRANSB: D14.2(ANODE) L2.5
VRTC_OUT: R909.2(P2) ; also on sheet 3 9
VSDMMC: U1.W8(VDDSHV8) U1.Y8(VDDSHV8) ; also on sheet 9 25 31
VSMPS1_2: C276.1 C277.1 L12.2 L13.2 R641.1(I1)
VSMPS1_SW: L12.1 U3.E11(SMPS1_SW_1) U3.E12(SMPS1_SW_2) U3.E13(SMPS1_SW_3)
VSMPS2_SW: L13.1 U3.F11(SMPS2_SW1) U3.F12(SMPS2_SW2) U3.F13(SMPS2_SW3)
VSMPS3: C278.1 L14.2 R656.2(P2)
VSMPS3_SW: L14.1 U3.J11(SMPS3_SW1) U3.J12(SMPS3_SW2) U3.J13(SMPS3_SW3)
VSMPS4_5: C279.1 C280.1 L15.2 L16.2 R642.1(I1)
VSMPS4_SW: L15.1 U3.G1(SMPS4_SW1) U3.G2(SMPS4_SW2) U3.G3(SMPS4_SW3)
VSMPS5_SW: L16.1 U3.H1(SMPS5_SW1) U3.H2(SMPS5_SW2) U3.H3(SMPS5_SW3)
VSMPS6_SW: L17.1 U3.M5(SMPS6_SW) U3.N5(SMPS6_SW)
VSMPS7: C269.1 L18.2 R640.1(I1)
VSMPS7_SW: L18.1 U3.D1(SMPS7_SW1) U3.D2(SMPS7_SW2) U3.D3(SMPS7_SW3)
VSMPS8: C270.1 L19.2 TP26.1 U3.L11(SMPS8_FDBK)
VSMPS8_SW: L19.1 U3.M10(SMPS8_SW) U3.N10(SMPS8_SW)
VSMPS9: C271.1 L20.2 R742.2(P2)
VSMPS9_SW: L20.1 U3.M7(SMPS9_SW) U3.N7(SMPS9_SW)
VUSB_VBUS1: C311.1(POS) J23.1(VBUS) U66.6(OUT) U66.7(OUT) U66.8(OUT)
VUSB_VBUS2: C546.1 C547.1 J45.1(VBUS) J50.2 U93.6(VBUS) U94.6(OUT) U94.7(OUT) U94.8(OUT) ; also on sheet 9
N16251668: R385.1(P1) U73.15(SCL)
N16251678: R387.1(P1) U73.2(SDA)
N16839102: C206.1 R379.1(P1) U72.14(VCC)
N16839202: R382.2(P2) U72.13(RLIM)
N16839209: R381.2(P2) U72.2(DB1)
N16839216: R380.2(P2) U72.1(DB0)
N16844891: D6.2(Anode) R388.2(P2)
N16844892: D11.2(Anode) R395.2(P2)
N16844893: D12.2(Anode) R396.2(P2)
N16844894: D9.2(Anode) R391.2(P2)
N16844899: D10.2(Anode) R392.2(P2)
N16844909: D5.2(Anode) R386.2(P2)
N16844924: D8.2(Anode) R390.2(P2)
N16844930: D7.2(Anode) R389.2(P2)
N17007255: R366.1(P1) R377.1(P1) U28.4(Y)
N17745676: J9.22 R275.2(P2)
N17745678: J9.24 R277.2(P2)
N17745755: R276.2(P2) R300.2(P2) R903.2(P2) R905.1(P1) X1.3(OUT)
N19120663: R41.2(P2) U5.L8(ZQ)
N19120749: R44.2(P2) U7.L8(ZQ)
N19127709: R42.2(P2) U6.L8(ZQ)
N19139994: R32.1(P1) U6.D7(DQ8)
N19139997: R33.1(P1) U6.C3(DQ9)
N19140025: R34.1(P1) U6.C8(DQ10)
N19140027: R35.1(P1) U6.C2(DQ11)
N19140065: R37.1(P1) U6.A7(DQ12)
N19140067: R38.1(P1) U6.A2(DQ13)
N19140105: R39.1(P1) U6.B8(DQ14)
N19140107: R40.1(P1) U6.A3(DQ15)
N19290398: R421.1(P1) U33.7(WP)
N19634423: R579.2(P2) U74.6(~{RE})
N19634430: R574.1(P1) U74.8(D)
N19634431: R575.1(P1) U74.5(R)
N19634433: R576.1(P1) U74.7(DE)
N19700674: J18.5(TVDD) R730.1(P1)
N19923823: C286.1 U1.J10(CAP_VBBLDO_IVA)
N19923824: C287.1 U1.J9(CAP_VDDRAM_DSP)
N19923825: C288.1 U1.J16(CAP_VBBLDO_MPU)
N19923831: C292.1 U1.K19(CAP_VDDRAM_MPU)
N19923832: C291.1 U1.K16(CAP_VDDRAM_IVA)
N19923833: C290.1 U1.K9(CAP_VBBLDO_DSP)
N19923834: C289.1 U1.J19(CAP_VDDRAM_CORE4)
N19923844: C293.1 U1.L9(CAP_VDDRAM_CORE3)
N19923851: C298.1 U1.Y14(CAP_VBBLDO_GPU)
N19923852: C297.1 U1.Y13(CAP_VDDRAM_GPU)
N19923853: C296.1 U1.T20(CAP_VDDRAM_CORE1)
N20127658: C403.1 R907.1(P1) R908.1(P1) U1.AB15(VDD_RTC)
N20128389: C404.1 R909.1(P1) R910.1(P1) U1.AB13(VDDA_RTC)
N20190363: C454.2 J40.2 R639.4(SENS2)
N20190375: C454.1 J40.1 R639.3(SENS1)
N20190748: C455.2 J41.1 R640.3(SENS1)
N20190772: C455.1 J41.2 R640.4(SENS2)
N20190931: C456.2 J42.1 R641.3(SENS1)
N20190955: C456.1 J42.2 R641.4(SENS2)
N20191205: C457.2 J43.1 R642.3(SENS1)
N20191229: C457.1 J43.2 R642.4(SENS2)
N20275163: C460.1 U79.8(SS)
N20287248: R647.1(P1) R648.2(P2) U79.2(FB)
N20287275: R646.2(P2) U79.1(COMP)
N20287568: C463.1 R646.1(P1)
N20287584: D20.2(ANODE) L28.2 U79.5(SW)
N20594970: R678.1(P1) U86.1(VEN)
N20595300: R679.1(P1) U79.3(EN)
N20619479: R680.2 R681.2 U86.2(ADJ)
N20664562: L22.1 U62.B1(L1) U62.B2(L1)
N20664572: C417.1 U62.A3(VINA) U62.B3(VINA1) U62.C4(~{PS}) U62.D4(VSEL)
N20665027: L22.2 U62.D1(L2) U62.D2(L2)
N20962931: C421.1 R149.1(P1) R806.1(P1) U19.2(A)
N21605448: C545.1(POS) J50.1
N21620210: C197.1 R368.2(P2) U72.3(IP0)
N21620213: C198.1 R370.2(P2) U72.5(IP1)
N21620216: C199.1 R372.2(P2) U72.7(IP2)
N21620219: C200.1 R374.2(P2) U72.9(IP3)
N21620222: C201.1 R373.2(P2) U72.11(IP4)
N21620225: C202.1 R375.2(P2) U72.18(IP5)
N21620228: C203.1 R376.2(P2) U72.20(IP6)
N21620231: C204.1 R378.2(P2) U72.22(IP7)
N21685968: C548.1 R797.2(P2) U1.K14(RSVK14)
N21685998: J46.4 R638.1(P1) R798.2(P2)
N21984965: R429.1(P1) U78.2(A)
N21986708: J18.4(TDIS) R587.1(P1)
N21987254: J18.10(GND) R806.2(P2)
N23239351: R902.1(P1) X1.1(EN)
N23239414: J9.23 R903.1(P1)

Not connected (* = marked no-connect by the designer): J9 10 14; J14 1 2 4 7 9; J18 6(NC)* 17(EMU2)* 18(EMU3)* 19(EMU4)*; J37 18; SCKT1 MCH1* MCH3*; U1 A27(RSVA27) AB16(DDR1_CSN1)* AC17(DDR1_ODT1)* AD18(DDR1_A15)* B28(RSVB28) E24(NC) G22(NC) G23(NC) H20(NC) H21(NC) H22(NC) J21(NC) J22(NC) J27(NC) L20(NC) L21(NC) M20(NC) M21(NC) N21(NC) P19(NC) R20(NC) U18(NC) U19(NC) V18(NC) V19(NC) Y5(RSVY5) Y10(RSVY10) Y15(NC) Y16(NC); U5 J1(NU0)* J9(NU1)* L1(NU2)* L9(NU3)* M7(NU4)*; U6 J1(NU0)* J9(NU1)* L1(NU2)* L9(NU3)* M7(NU4)*; U7 J1(NU0)* J9(NU1)* L1(NU2)* L9(NU3)* M7(NU4)*; U19 1(NC)*; U28 1(NC)*; U52 1(NC/FB)* 2(PG)*; U72 4(RE0)* 6(RE1)* 8(RE2)* 10(RE3)* 12(RE4)* 16(TOK)* 17(RE5)* 19(RE6)* 21(RE7)* 27(SIP)*; U74 10(ISODE); U78 1(NC)*; U93 5(NC)*

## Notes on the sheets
sheet 10
- ID Memory
- JTAG Connector
- Boot Configuration
sheet 12
- RT2_MII0_EDIO_DATA1
- PR2_PRU1_PRU_R30[2]
- AM57XX_PR1_PROFI_TXEN
sheet 13
- ARM MPU AM571X Industrial EVM
  ABC Package
- -See the Hardware User Guide for board details
- -See the Errata Document for design Issues
- -See the PCB Build Specification for PCB Details
sheet 14
- USB2 Port
sheet 15
- USB1 Port
sheet 18
- Industrial INPUTS
- Digital OUTPUTS
- I/O Expansion Header
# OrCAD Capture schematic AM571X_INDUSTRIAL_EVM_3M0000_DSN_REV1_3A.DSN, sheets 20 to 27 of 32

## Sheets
20 Pg30: PCIE Connector: size C
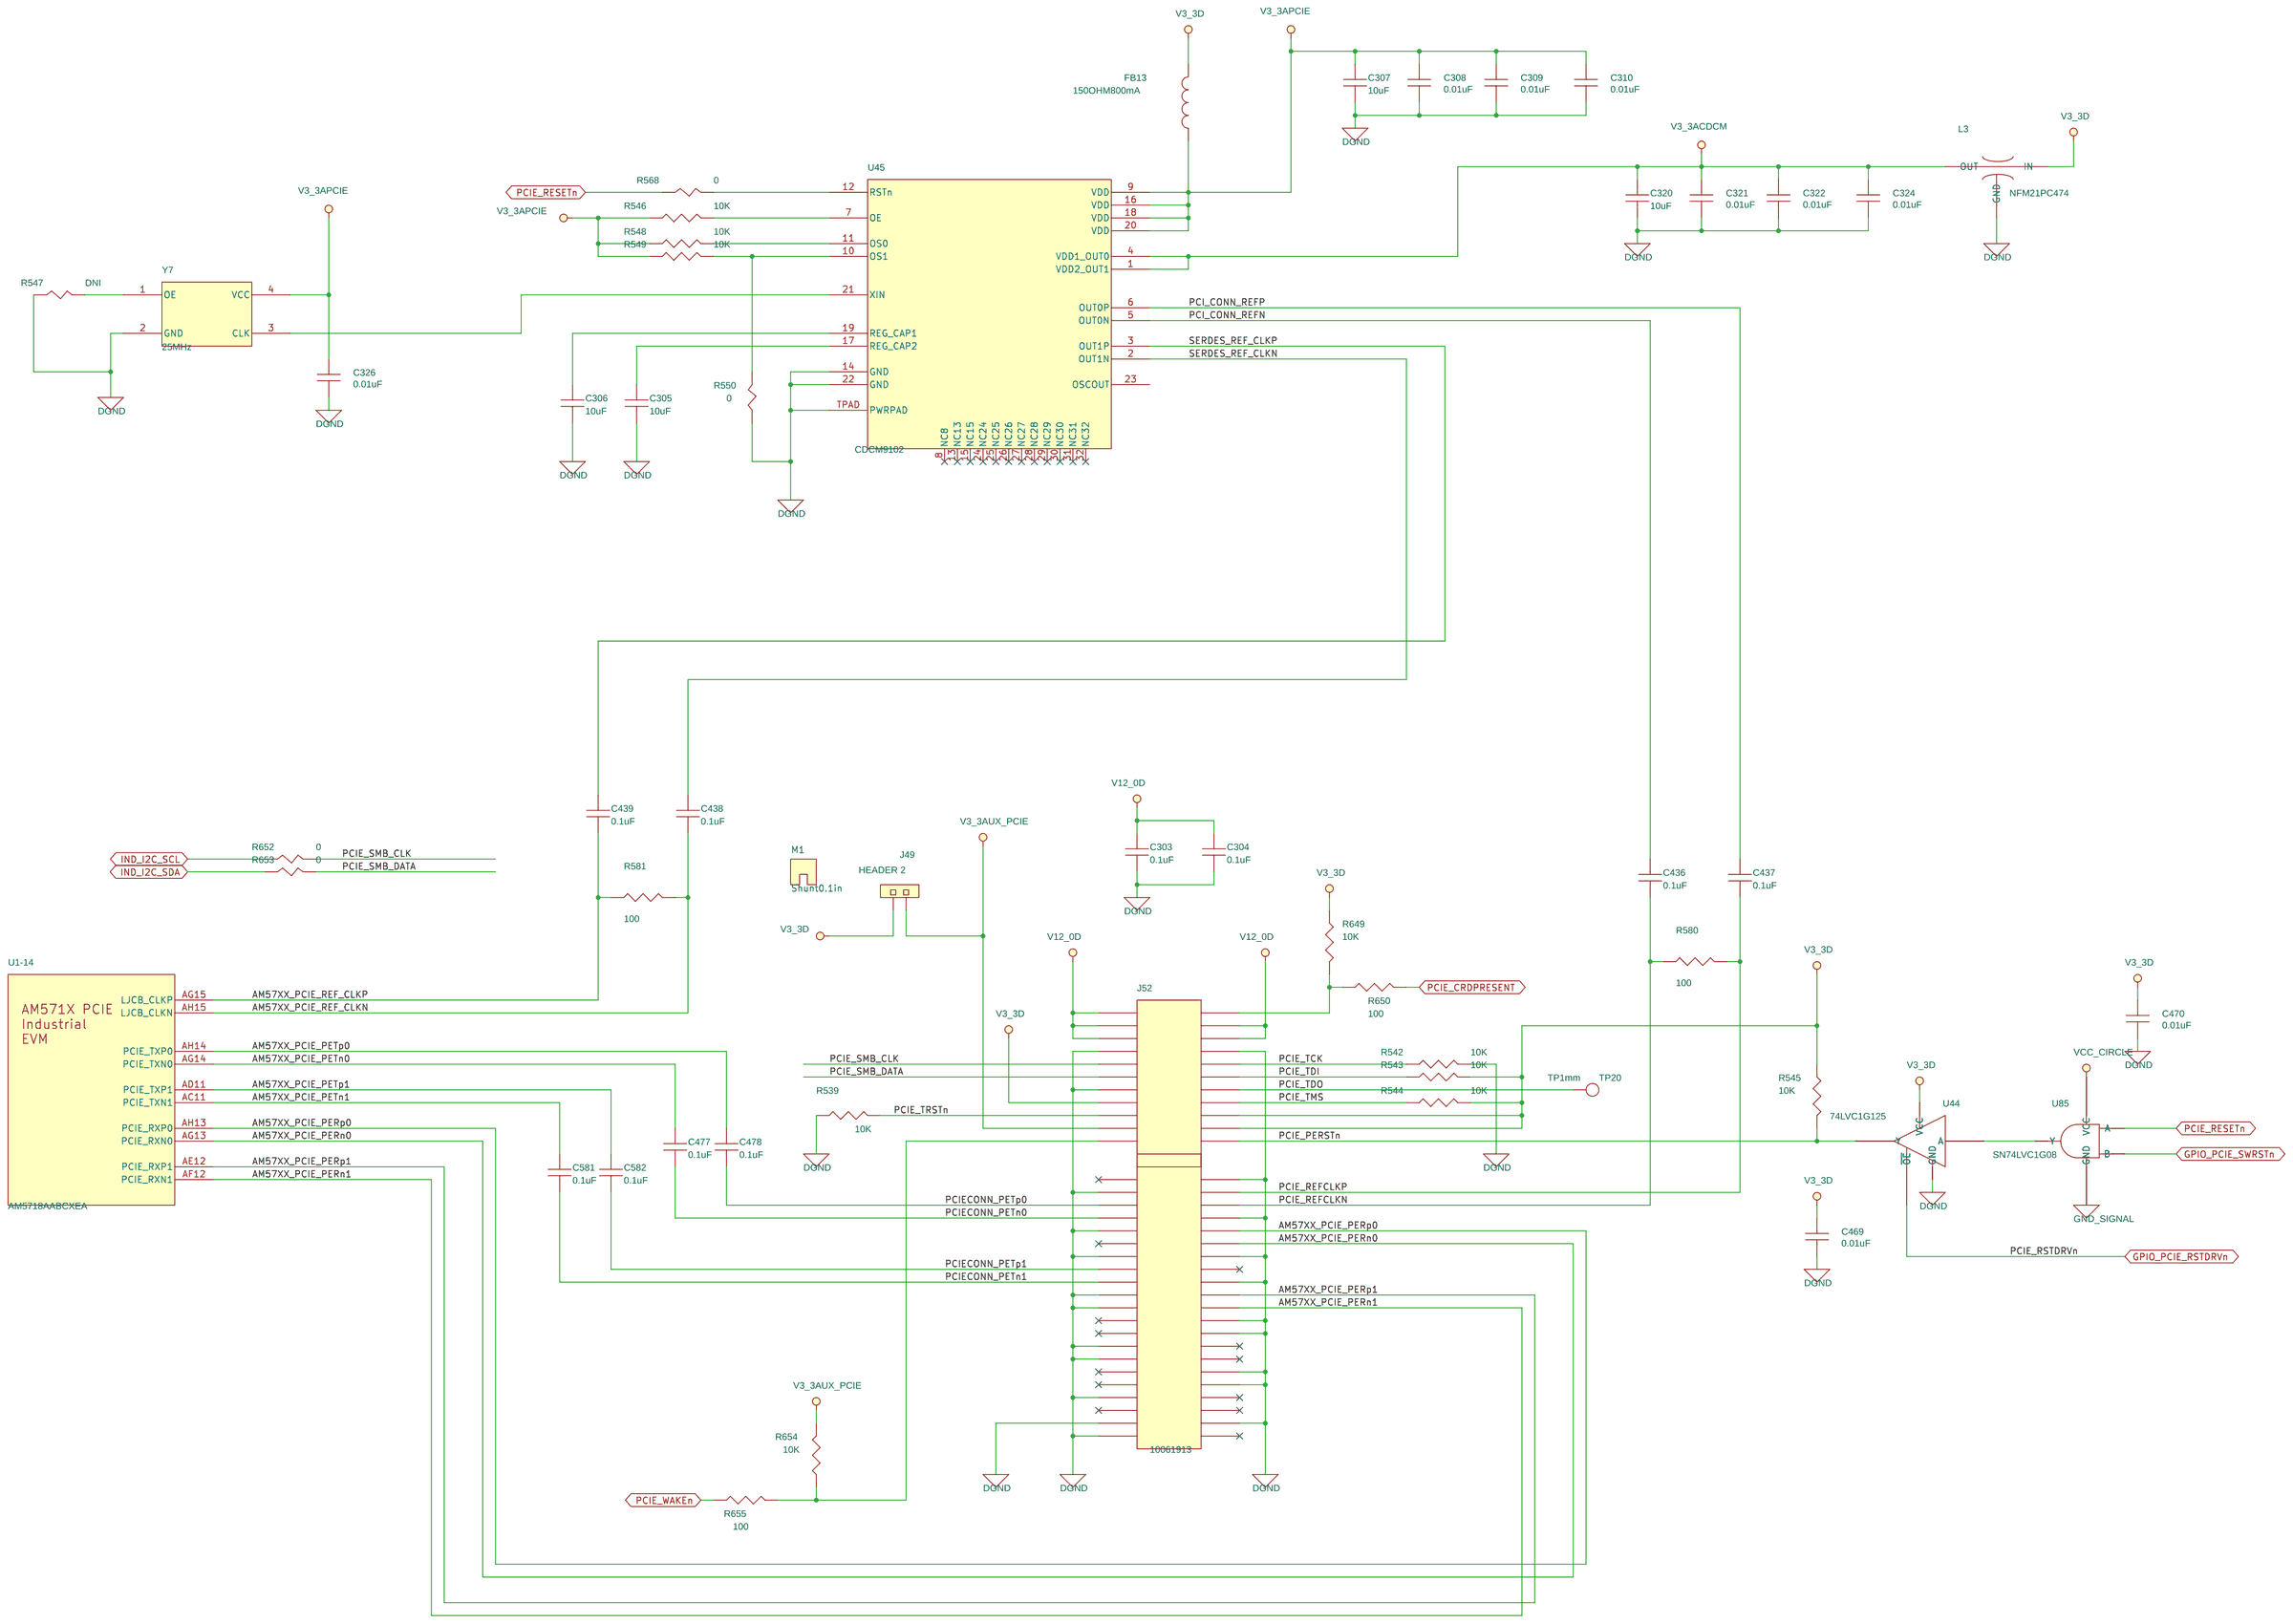
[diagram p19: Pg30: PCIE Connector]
21 Pg13: ICSS2 Ethernet 1: size C
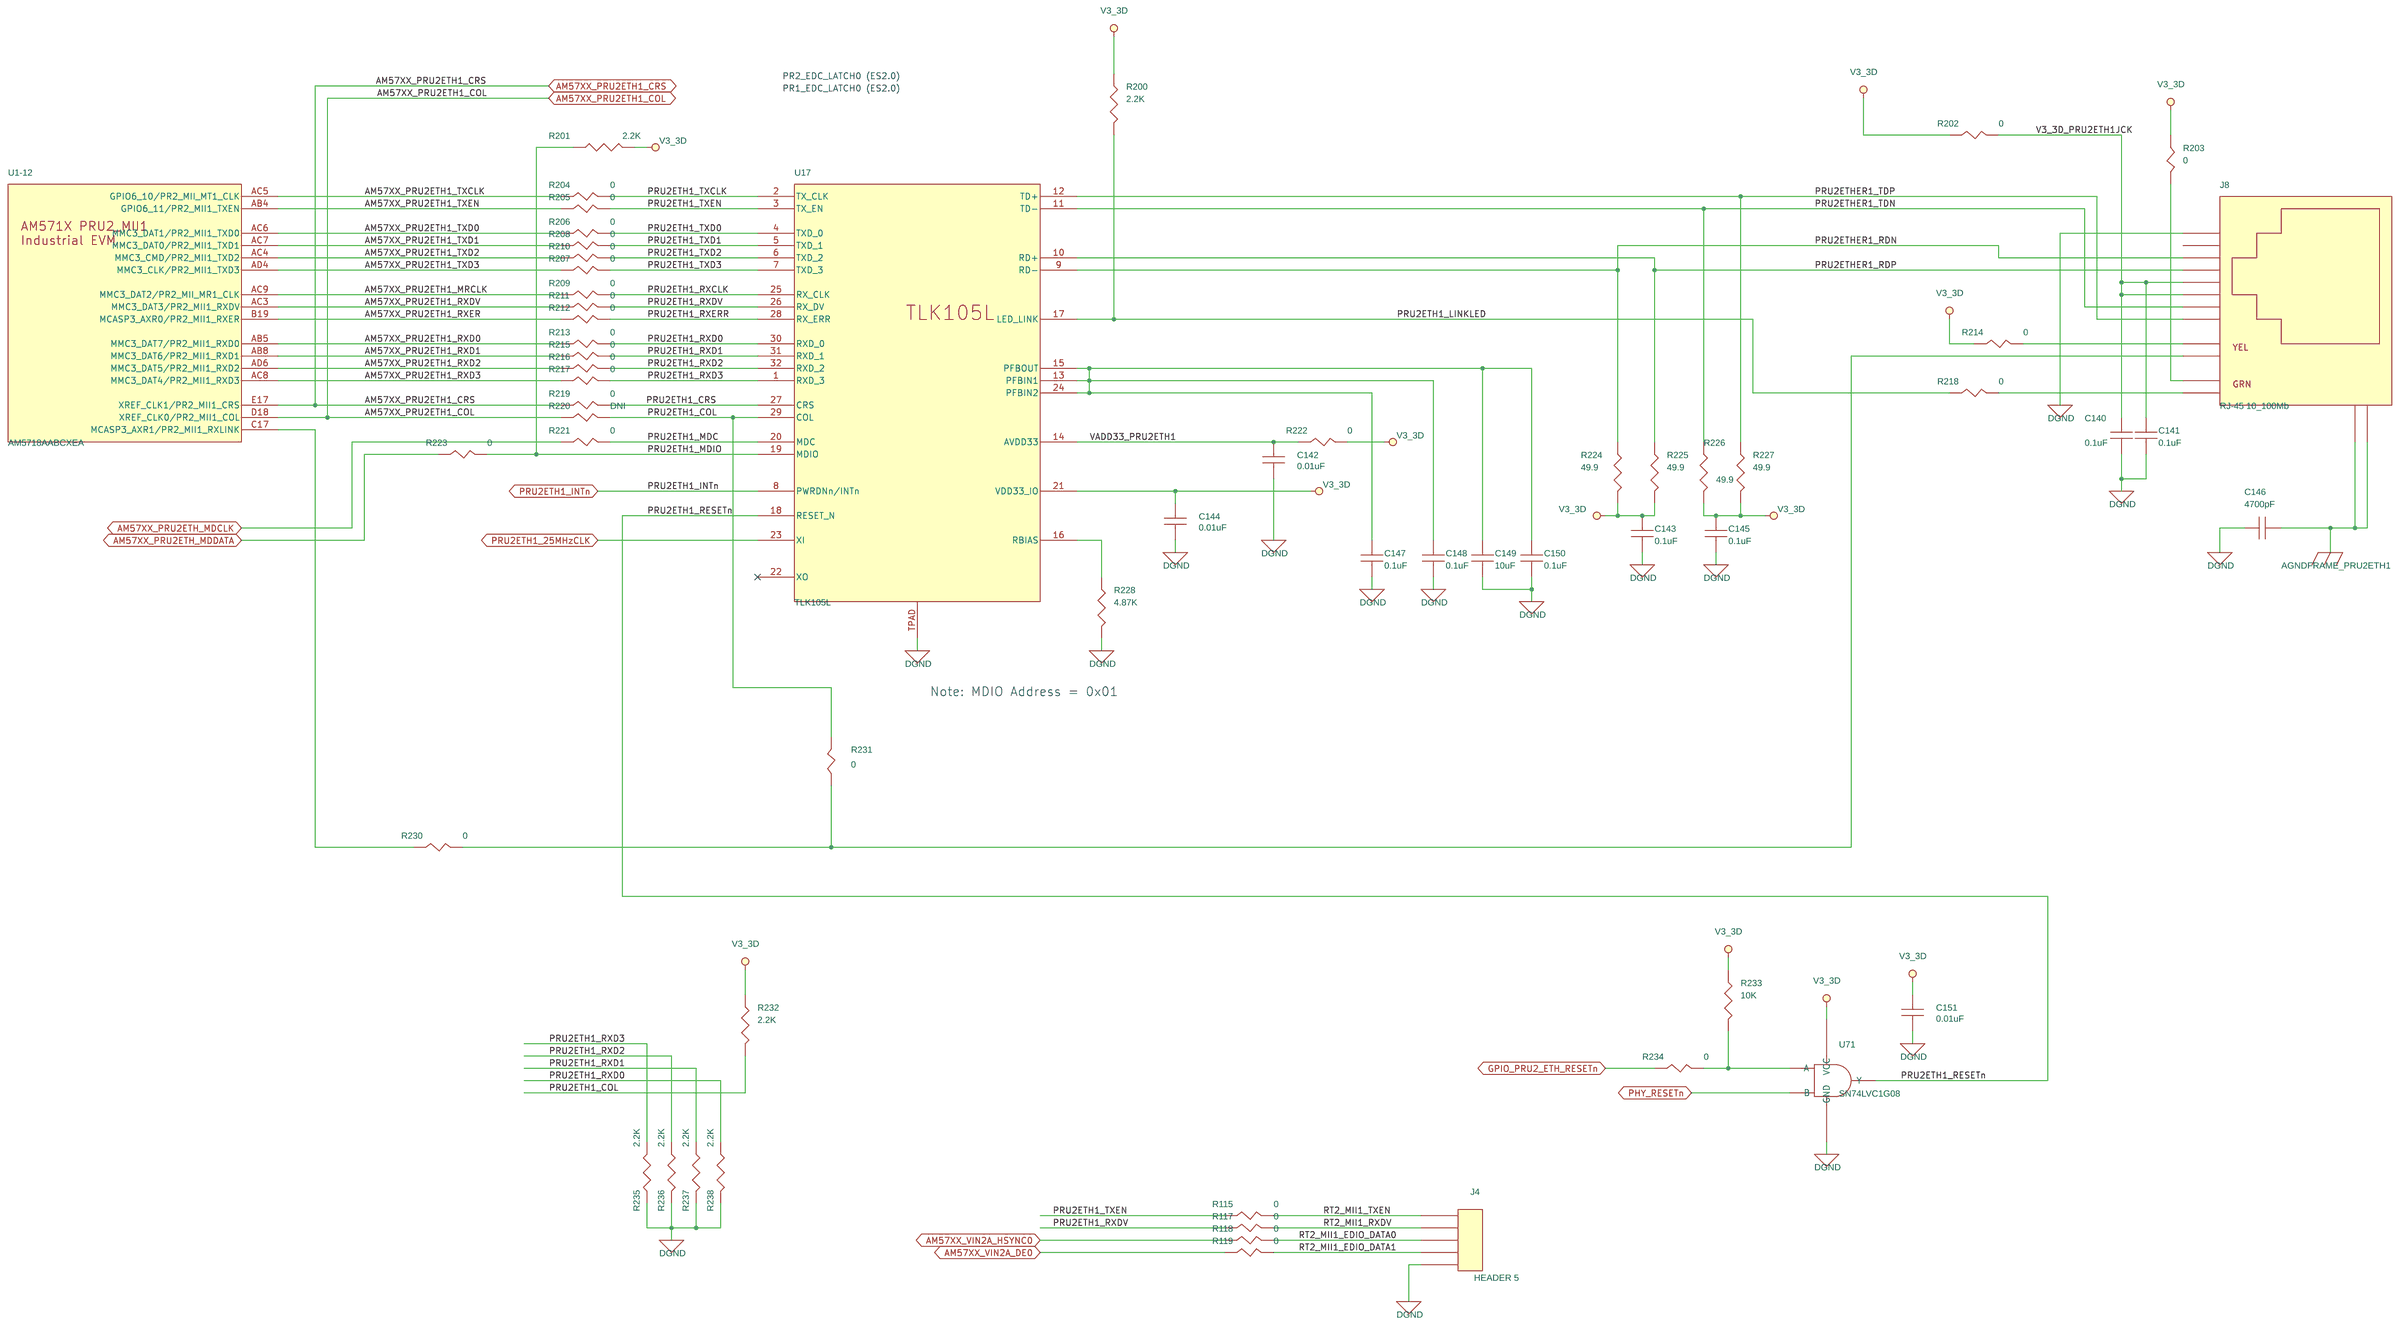
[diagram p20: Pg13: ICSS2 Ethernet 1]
22 Pg11: ICSS1 Ethernet 1: size C
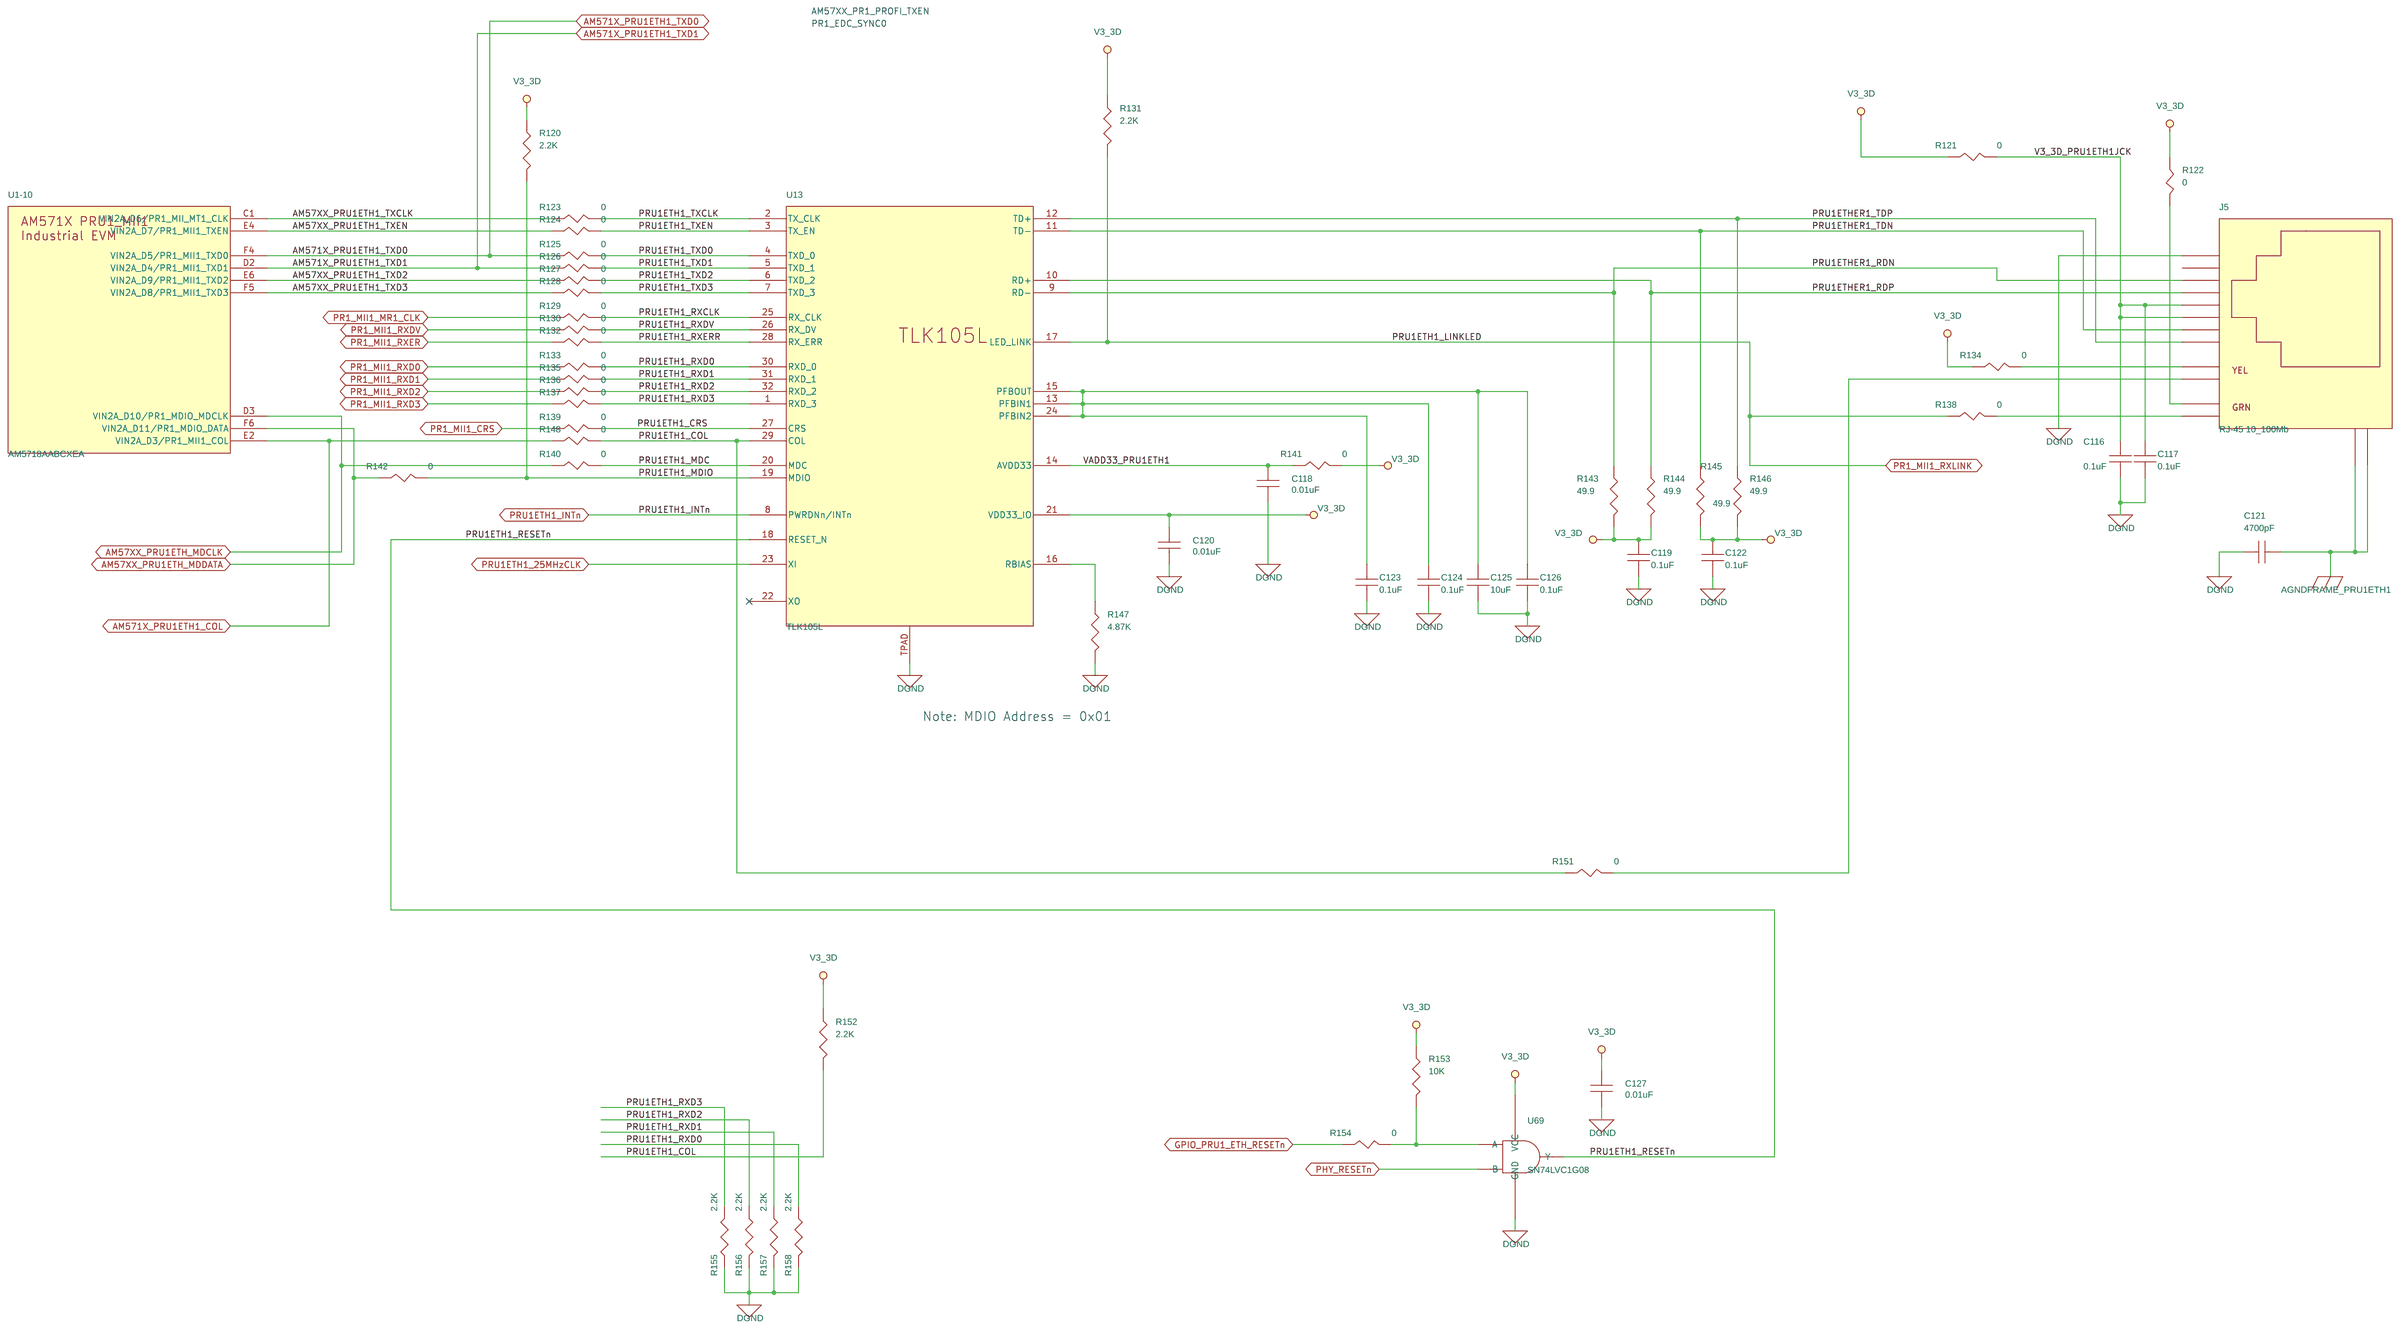
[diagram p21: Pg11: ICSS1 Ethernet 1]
23 Pg10: ICSS1 Ethernet 0: size C
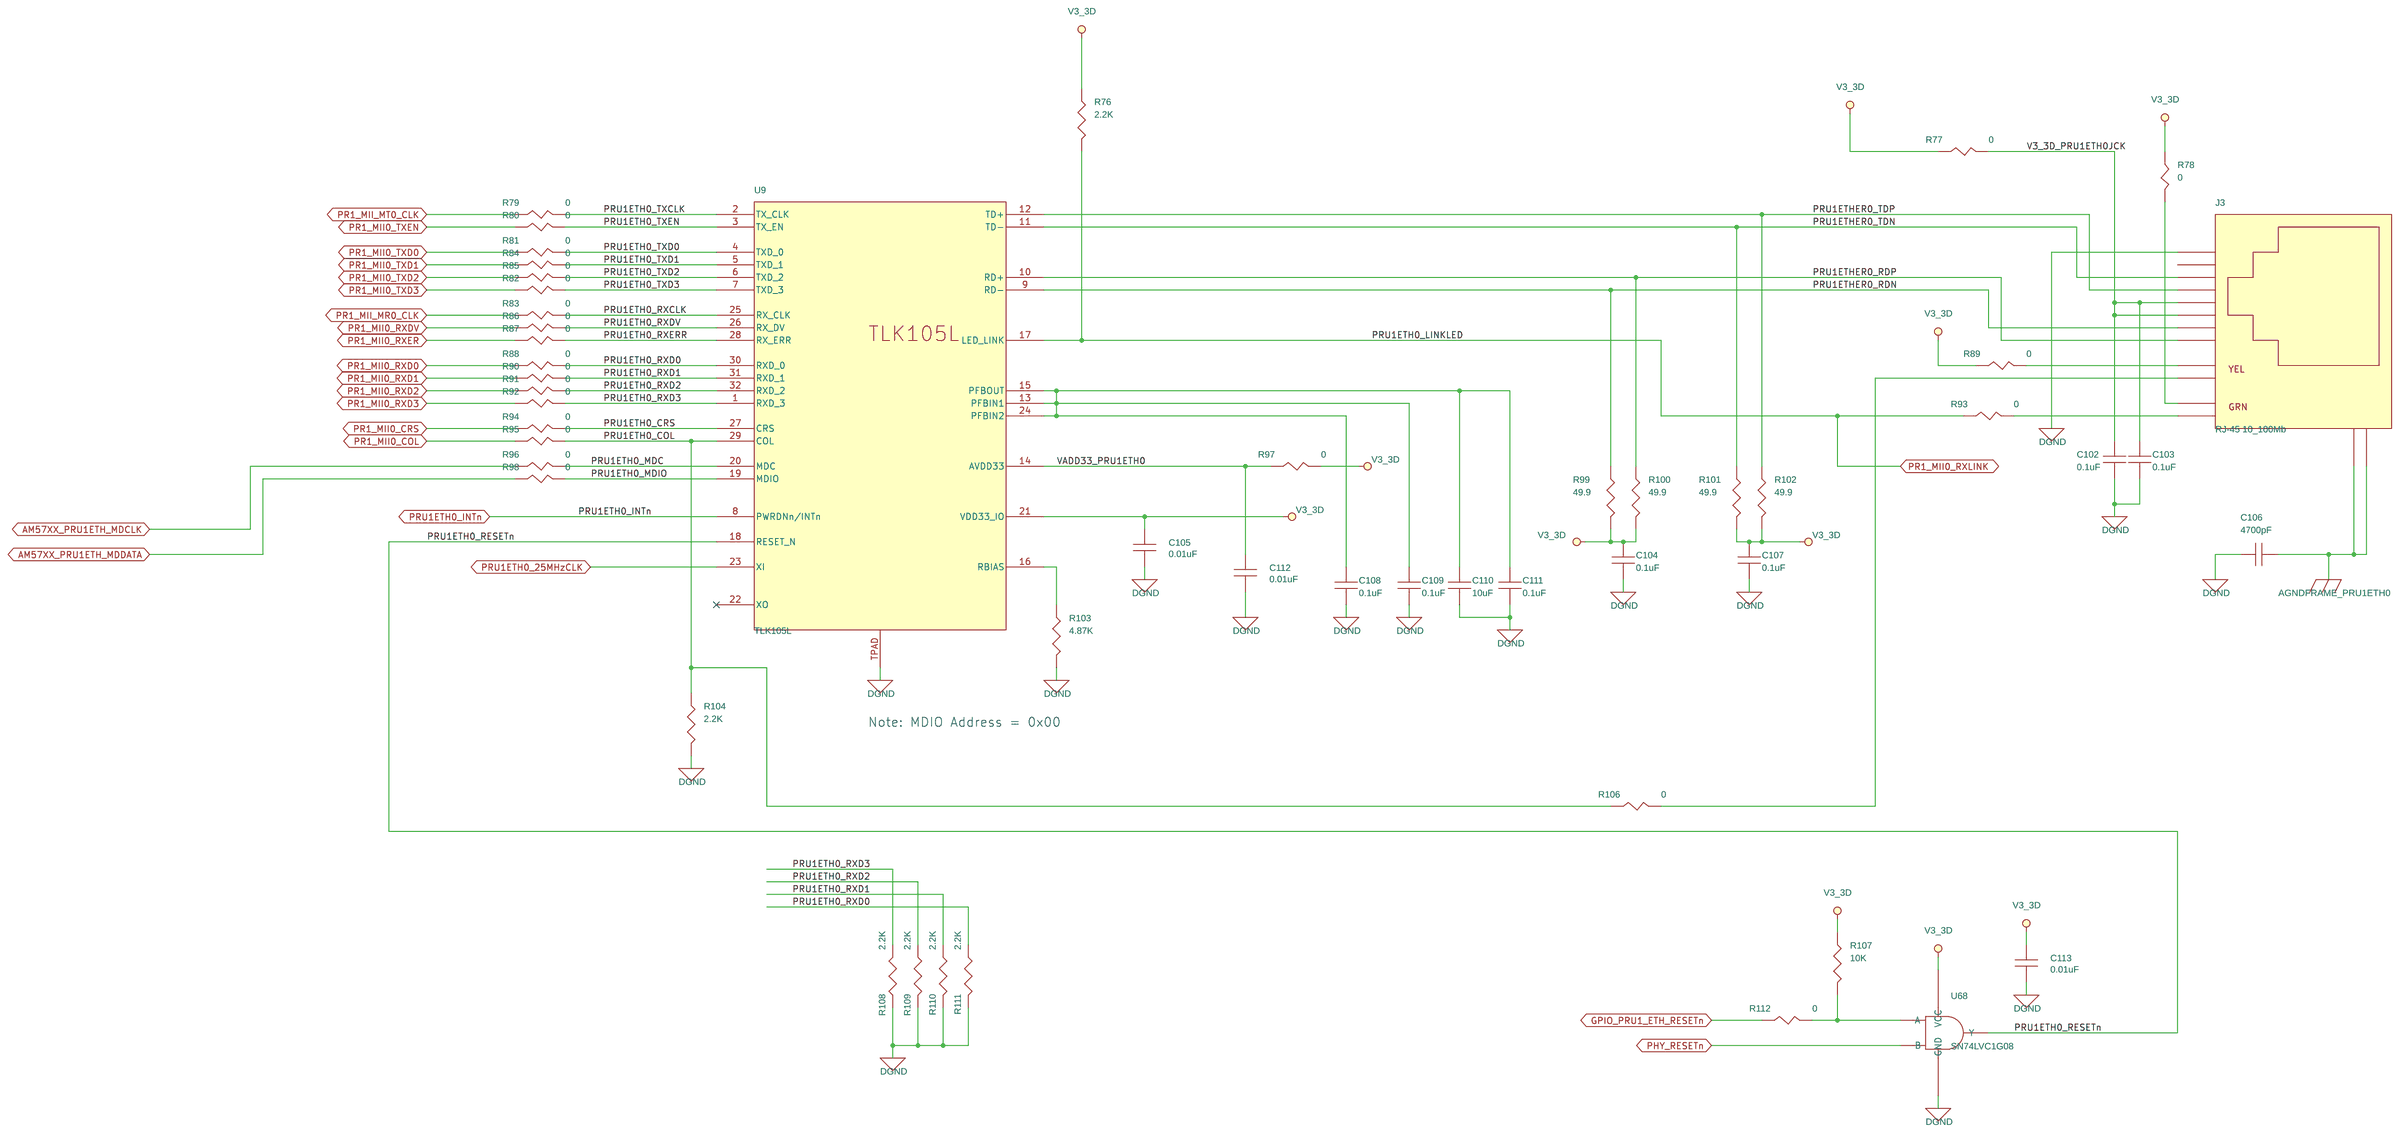
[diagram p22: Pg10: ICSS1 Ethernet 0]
24 Pg12: ICSS2 Ethernet 0: size C
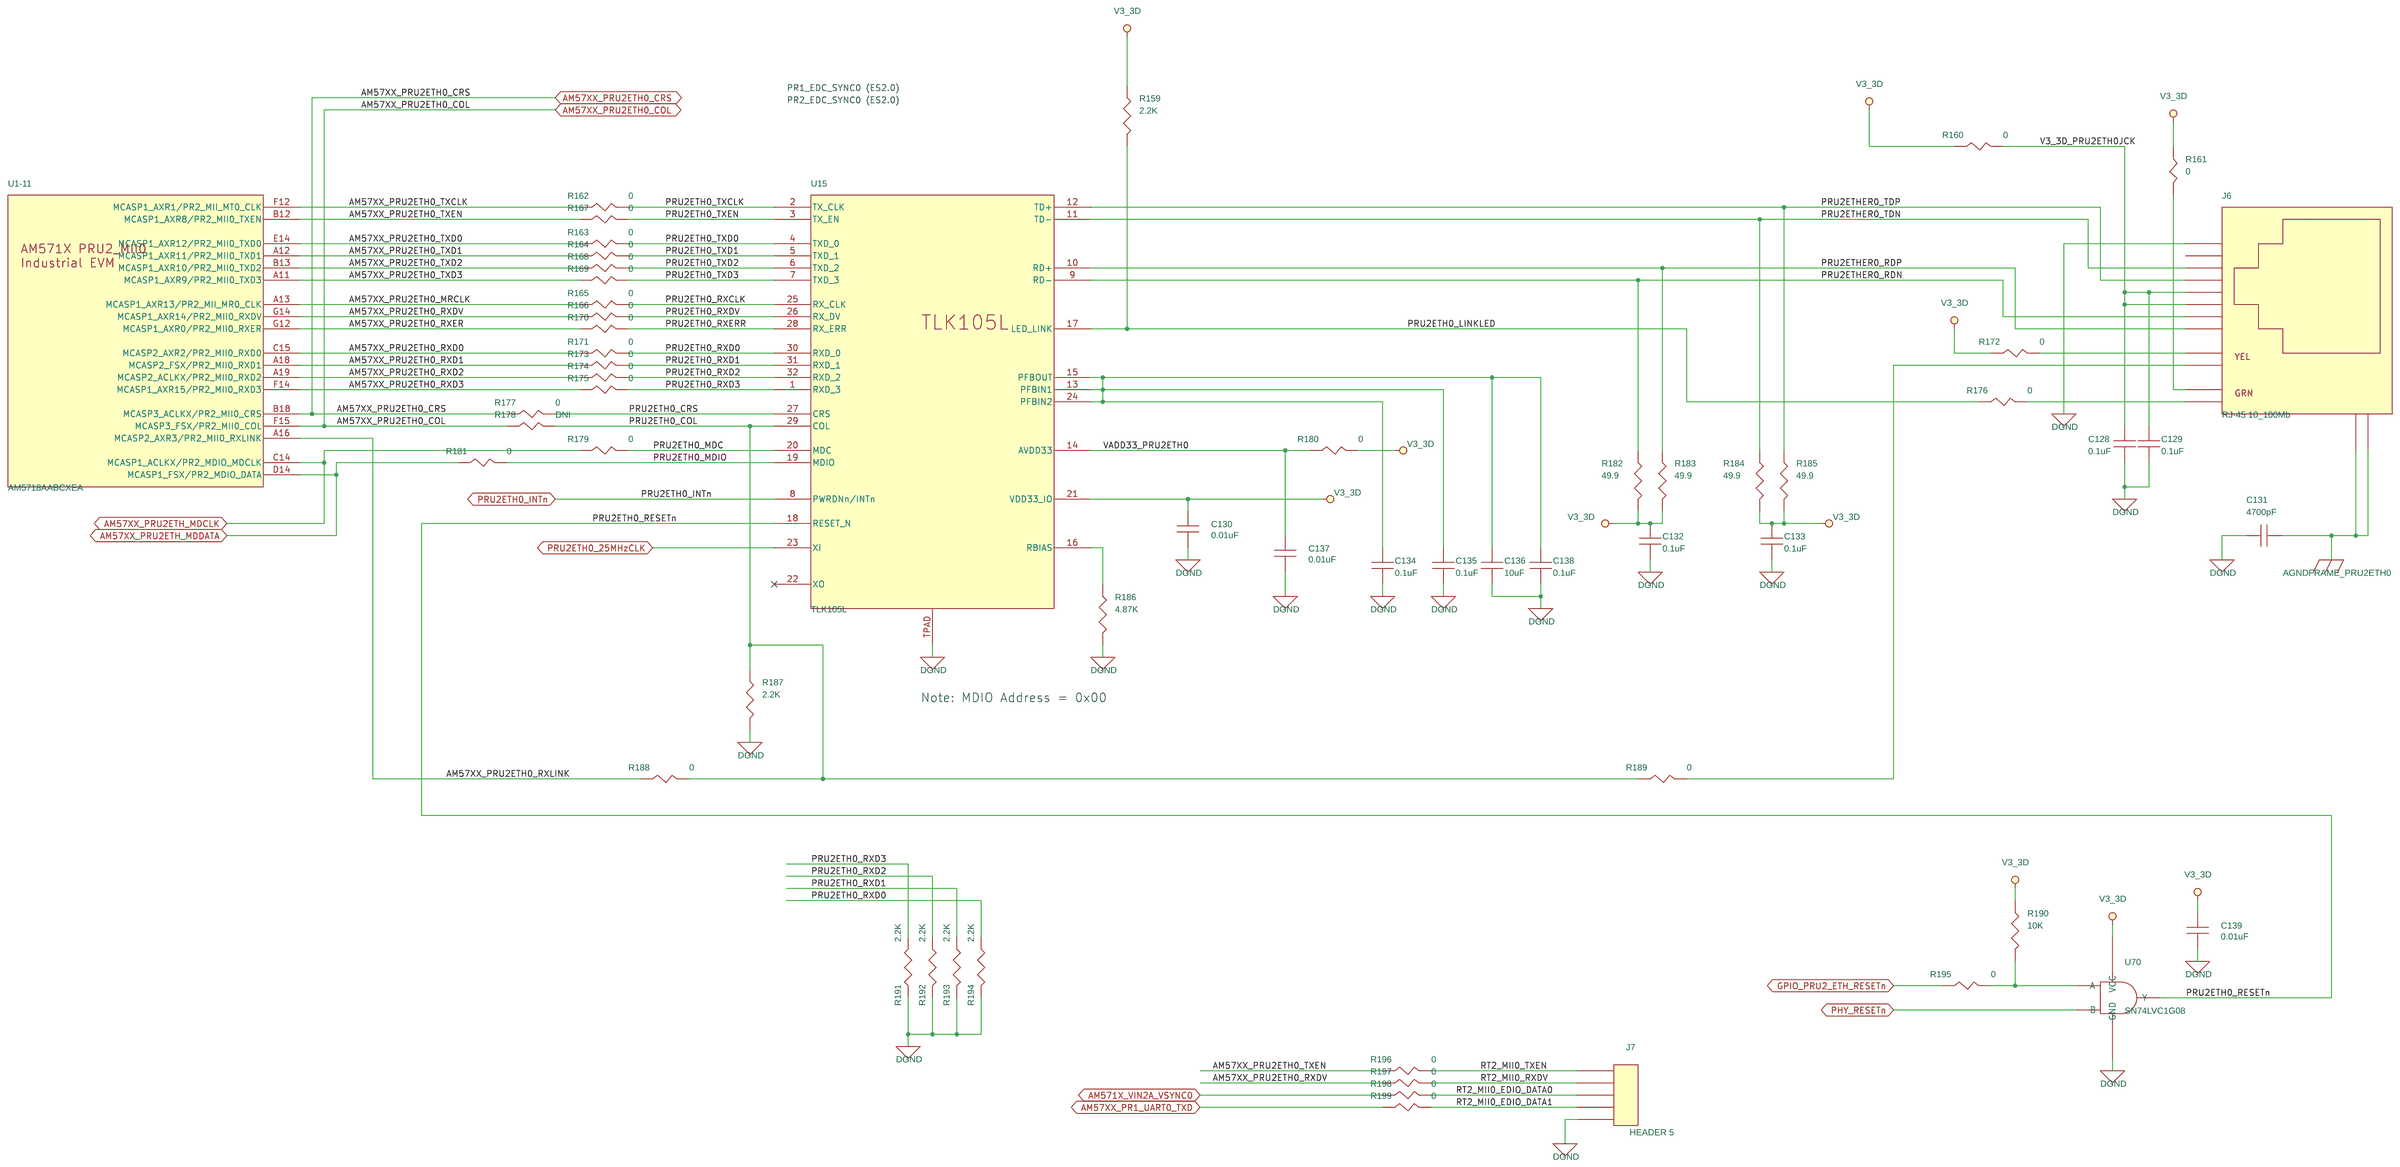
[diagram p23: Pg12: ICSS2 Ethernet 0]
25 Pg18: SDMMC #1 Interface: size C
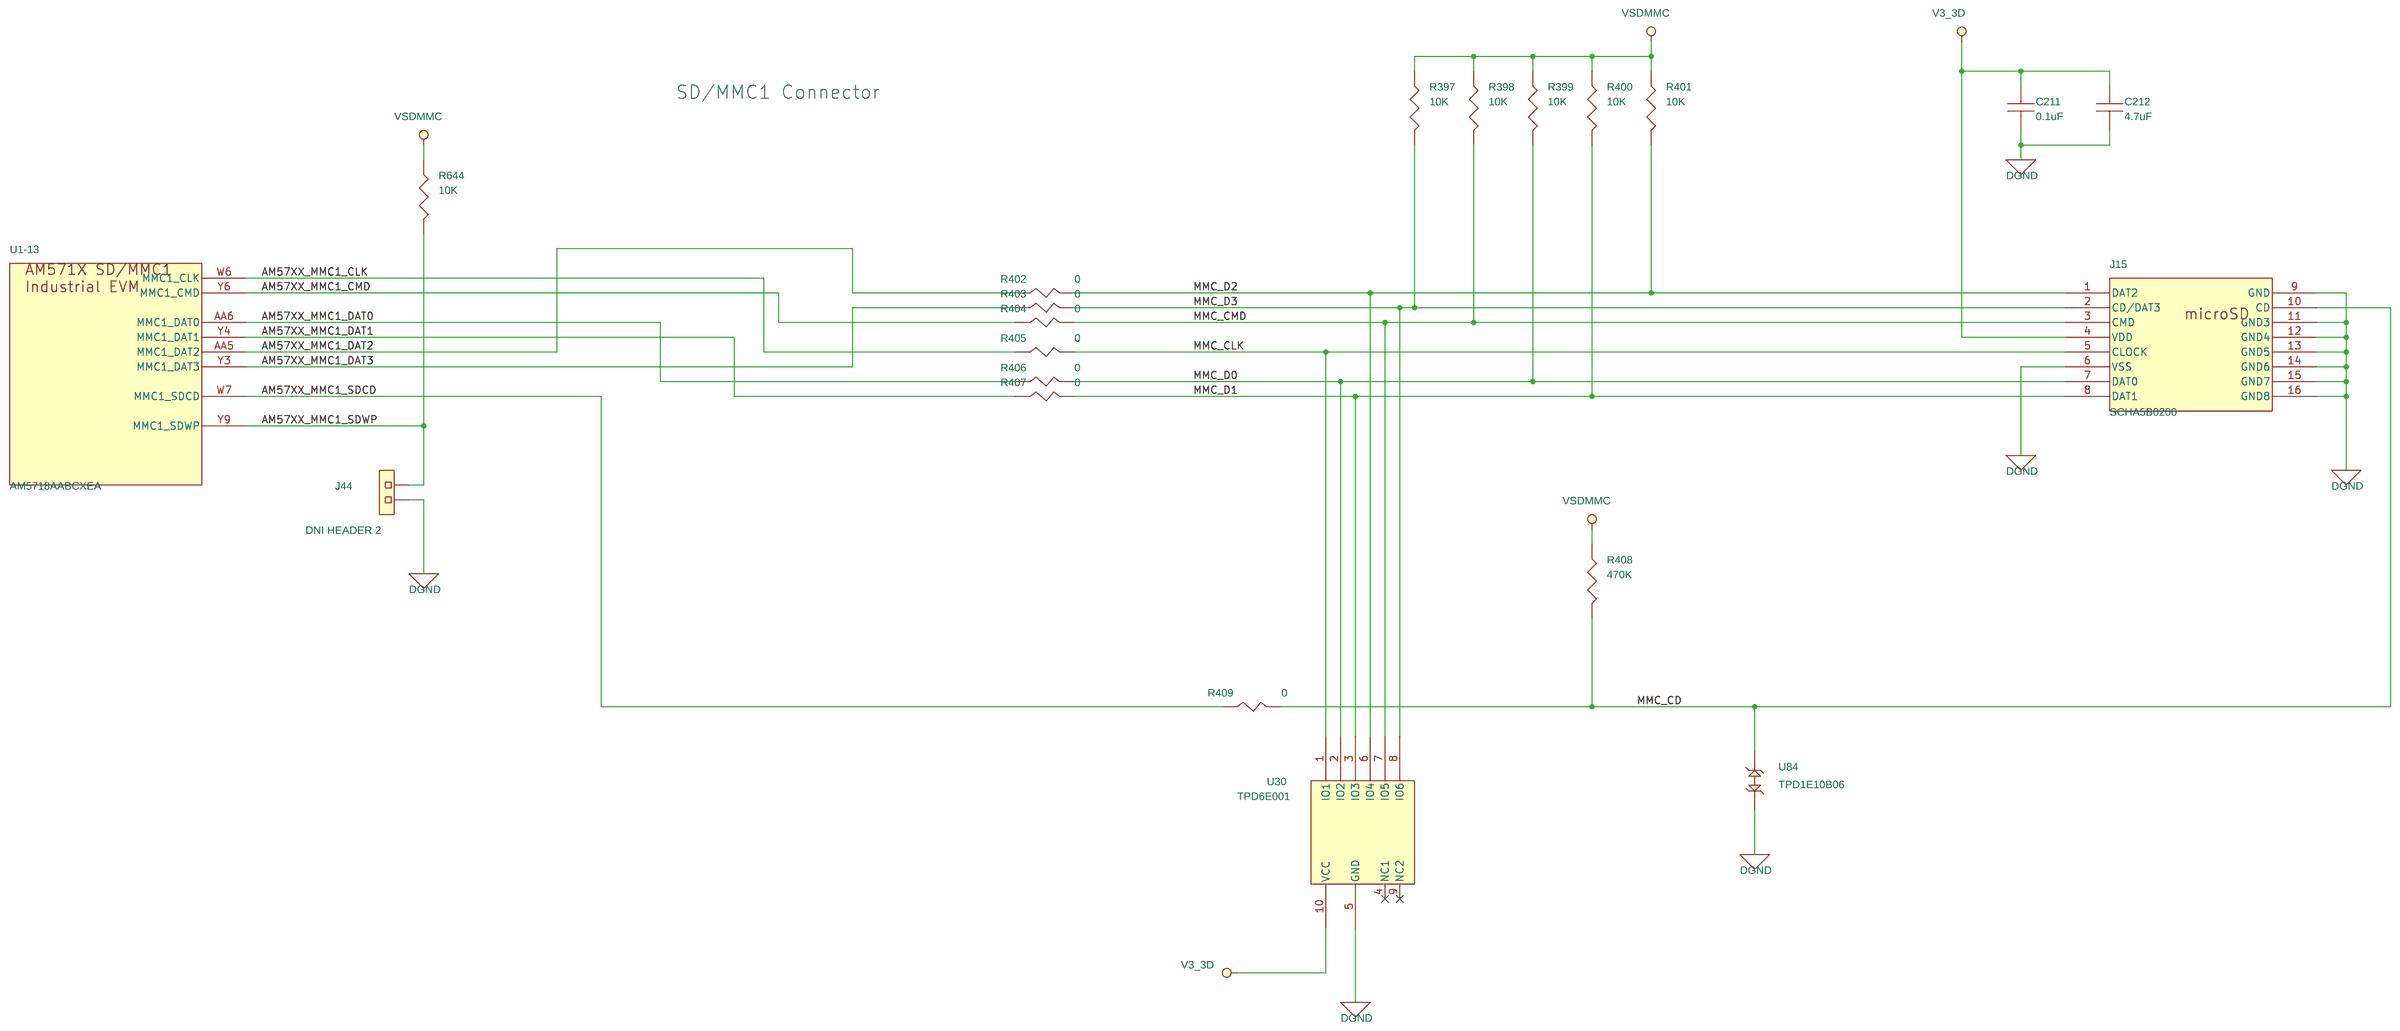
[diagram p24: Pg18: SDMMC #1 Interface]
26 Pg17: Gbit Ethernet #1: size C
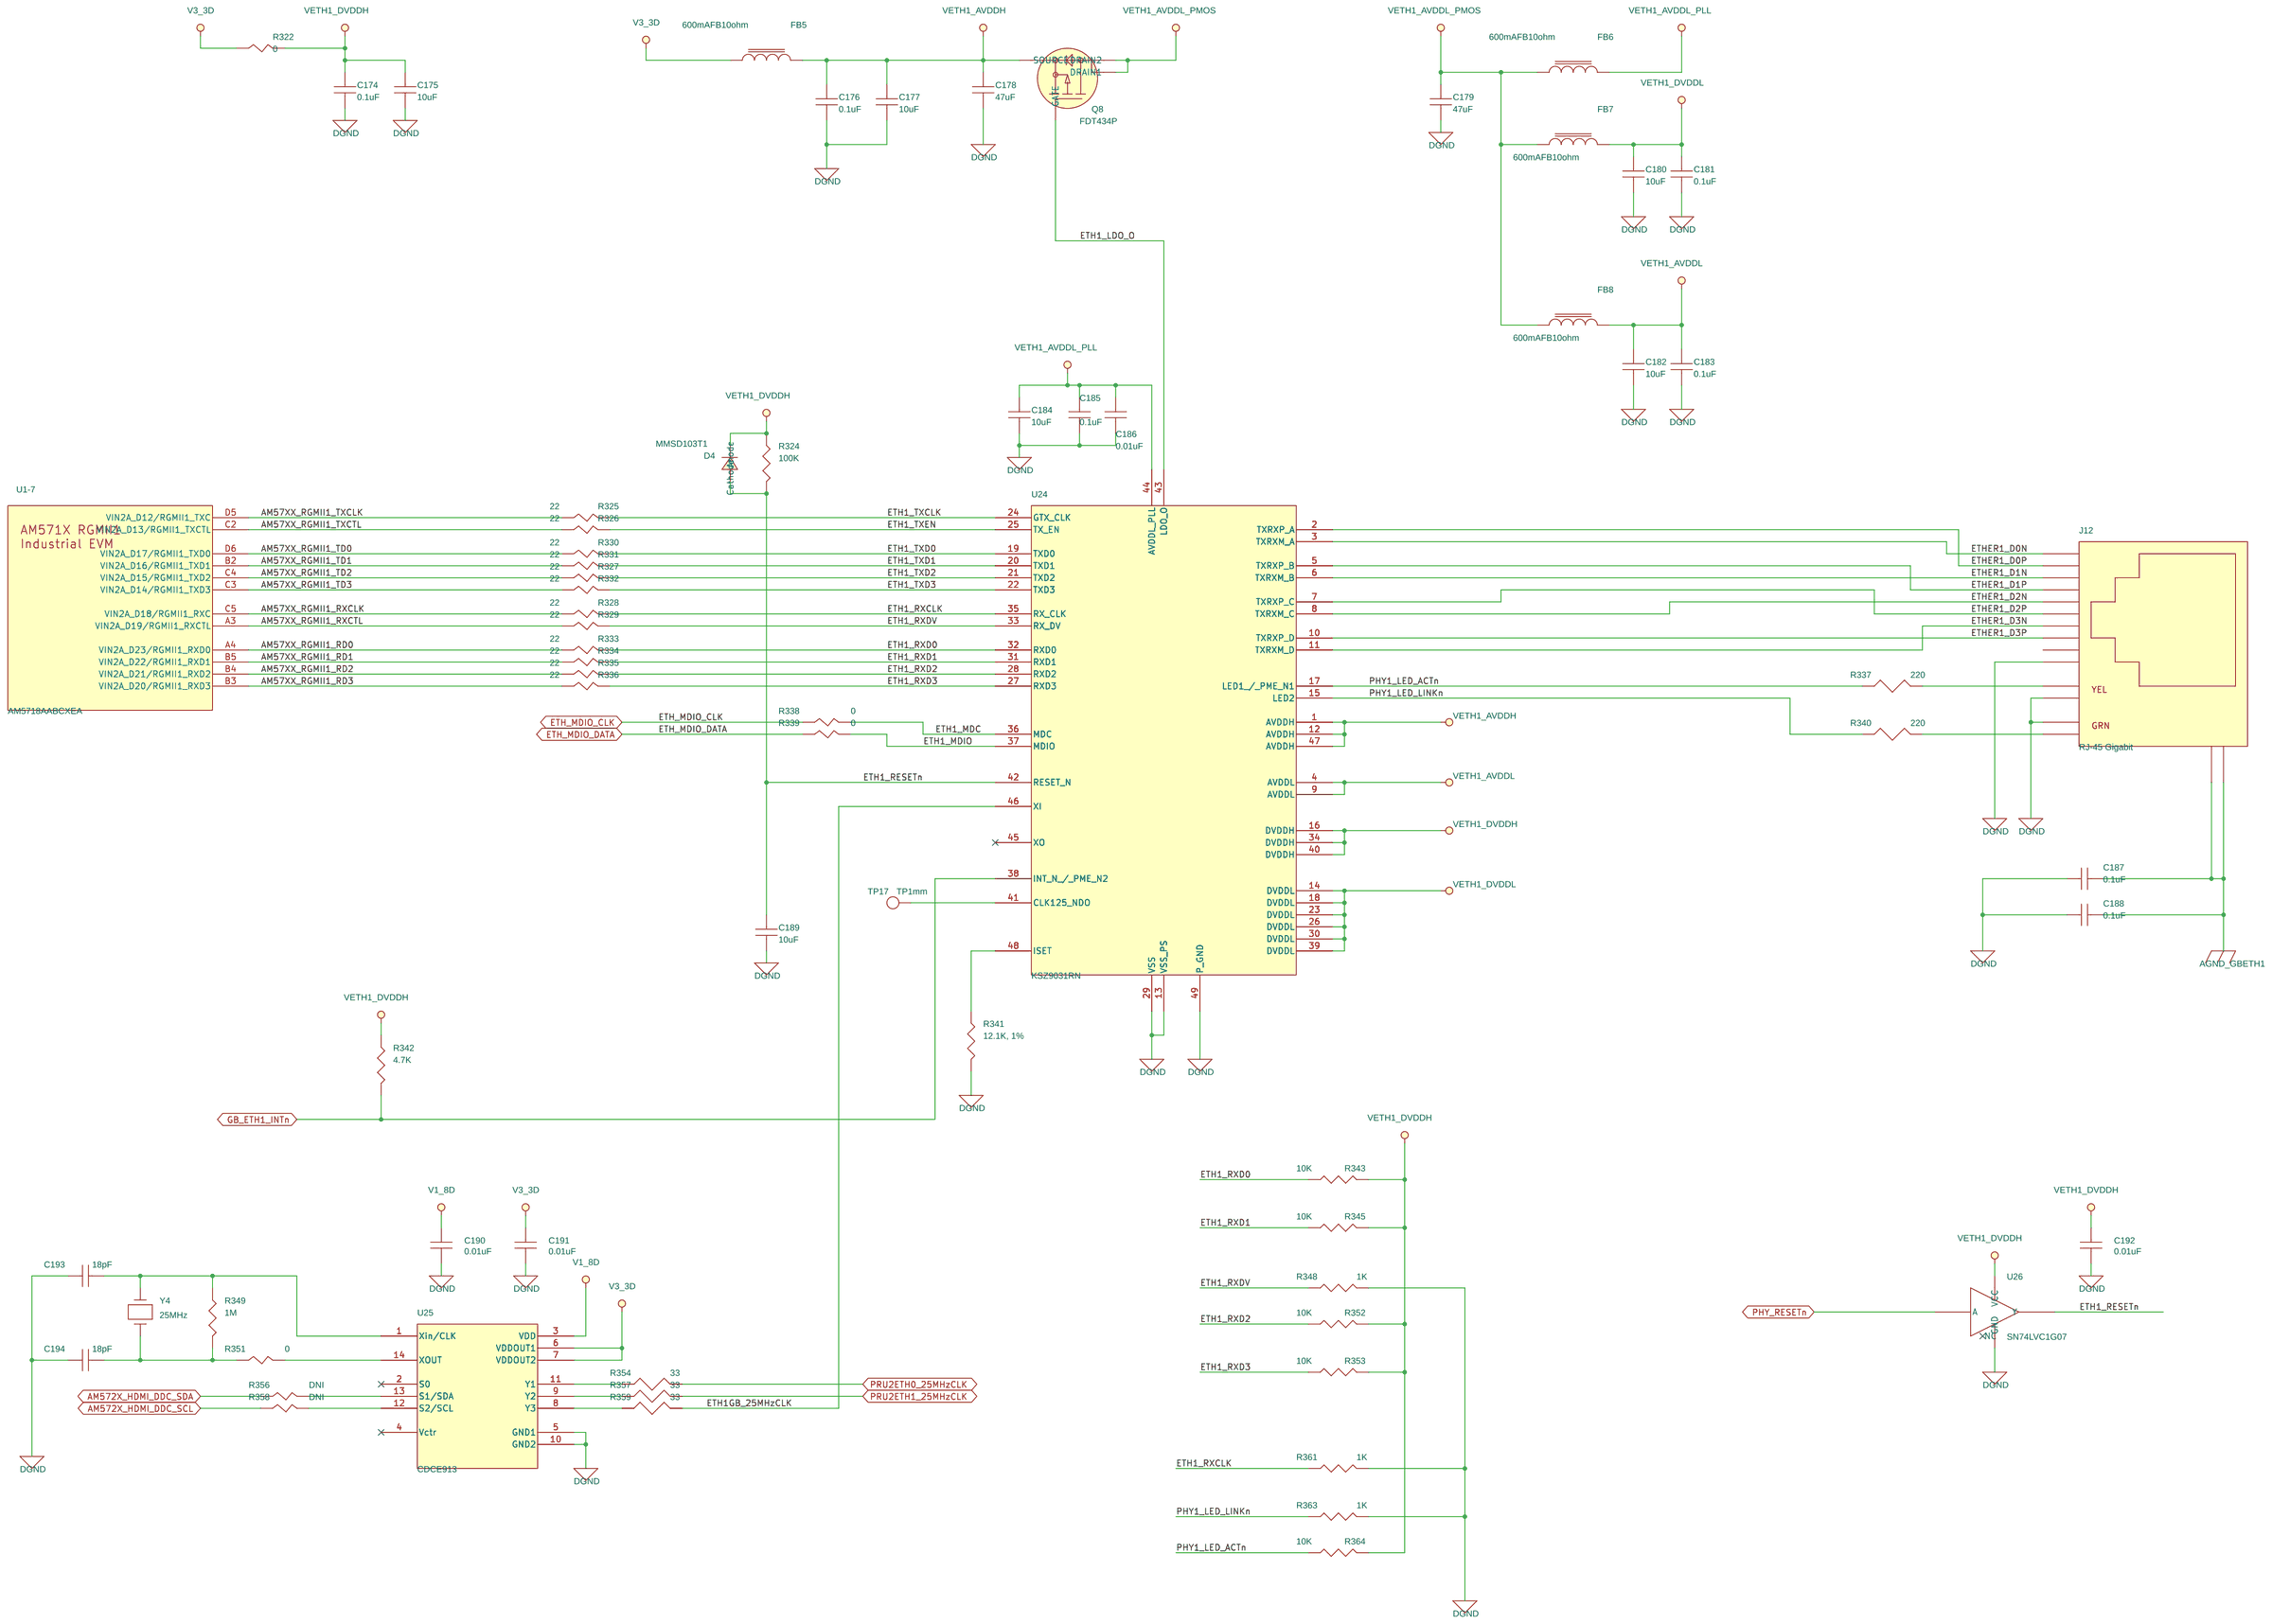
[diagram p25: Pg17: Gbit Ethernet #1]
27 Pg16: Gbit Ethernet #0: size C

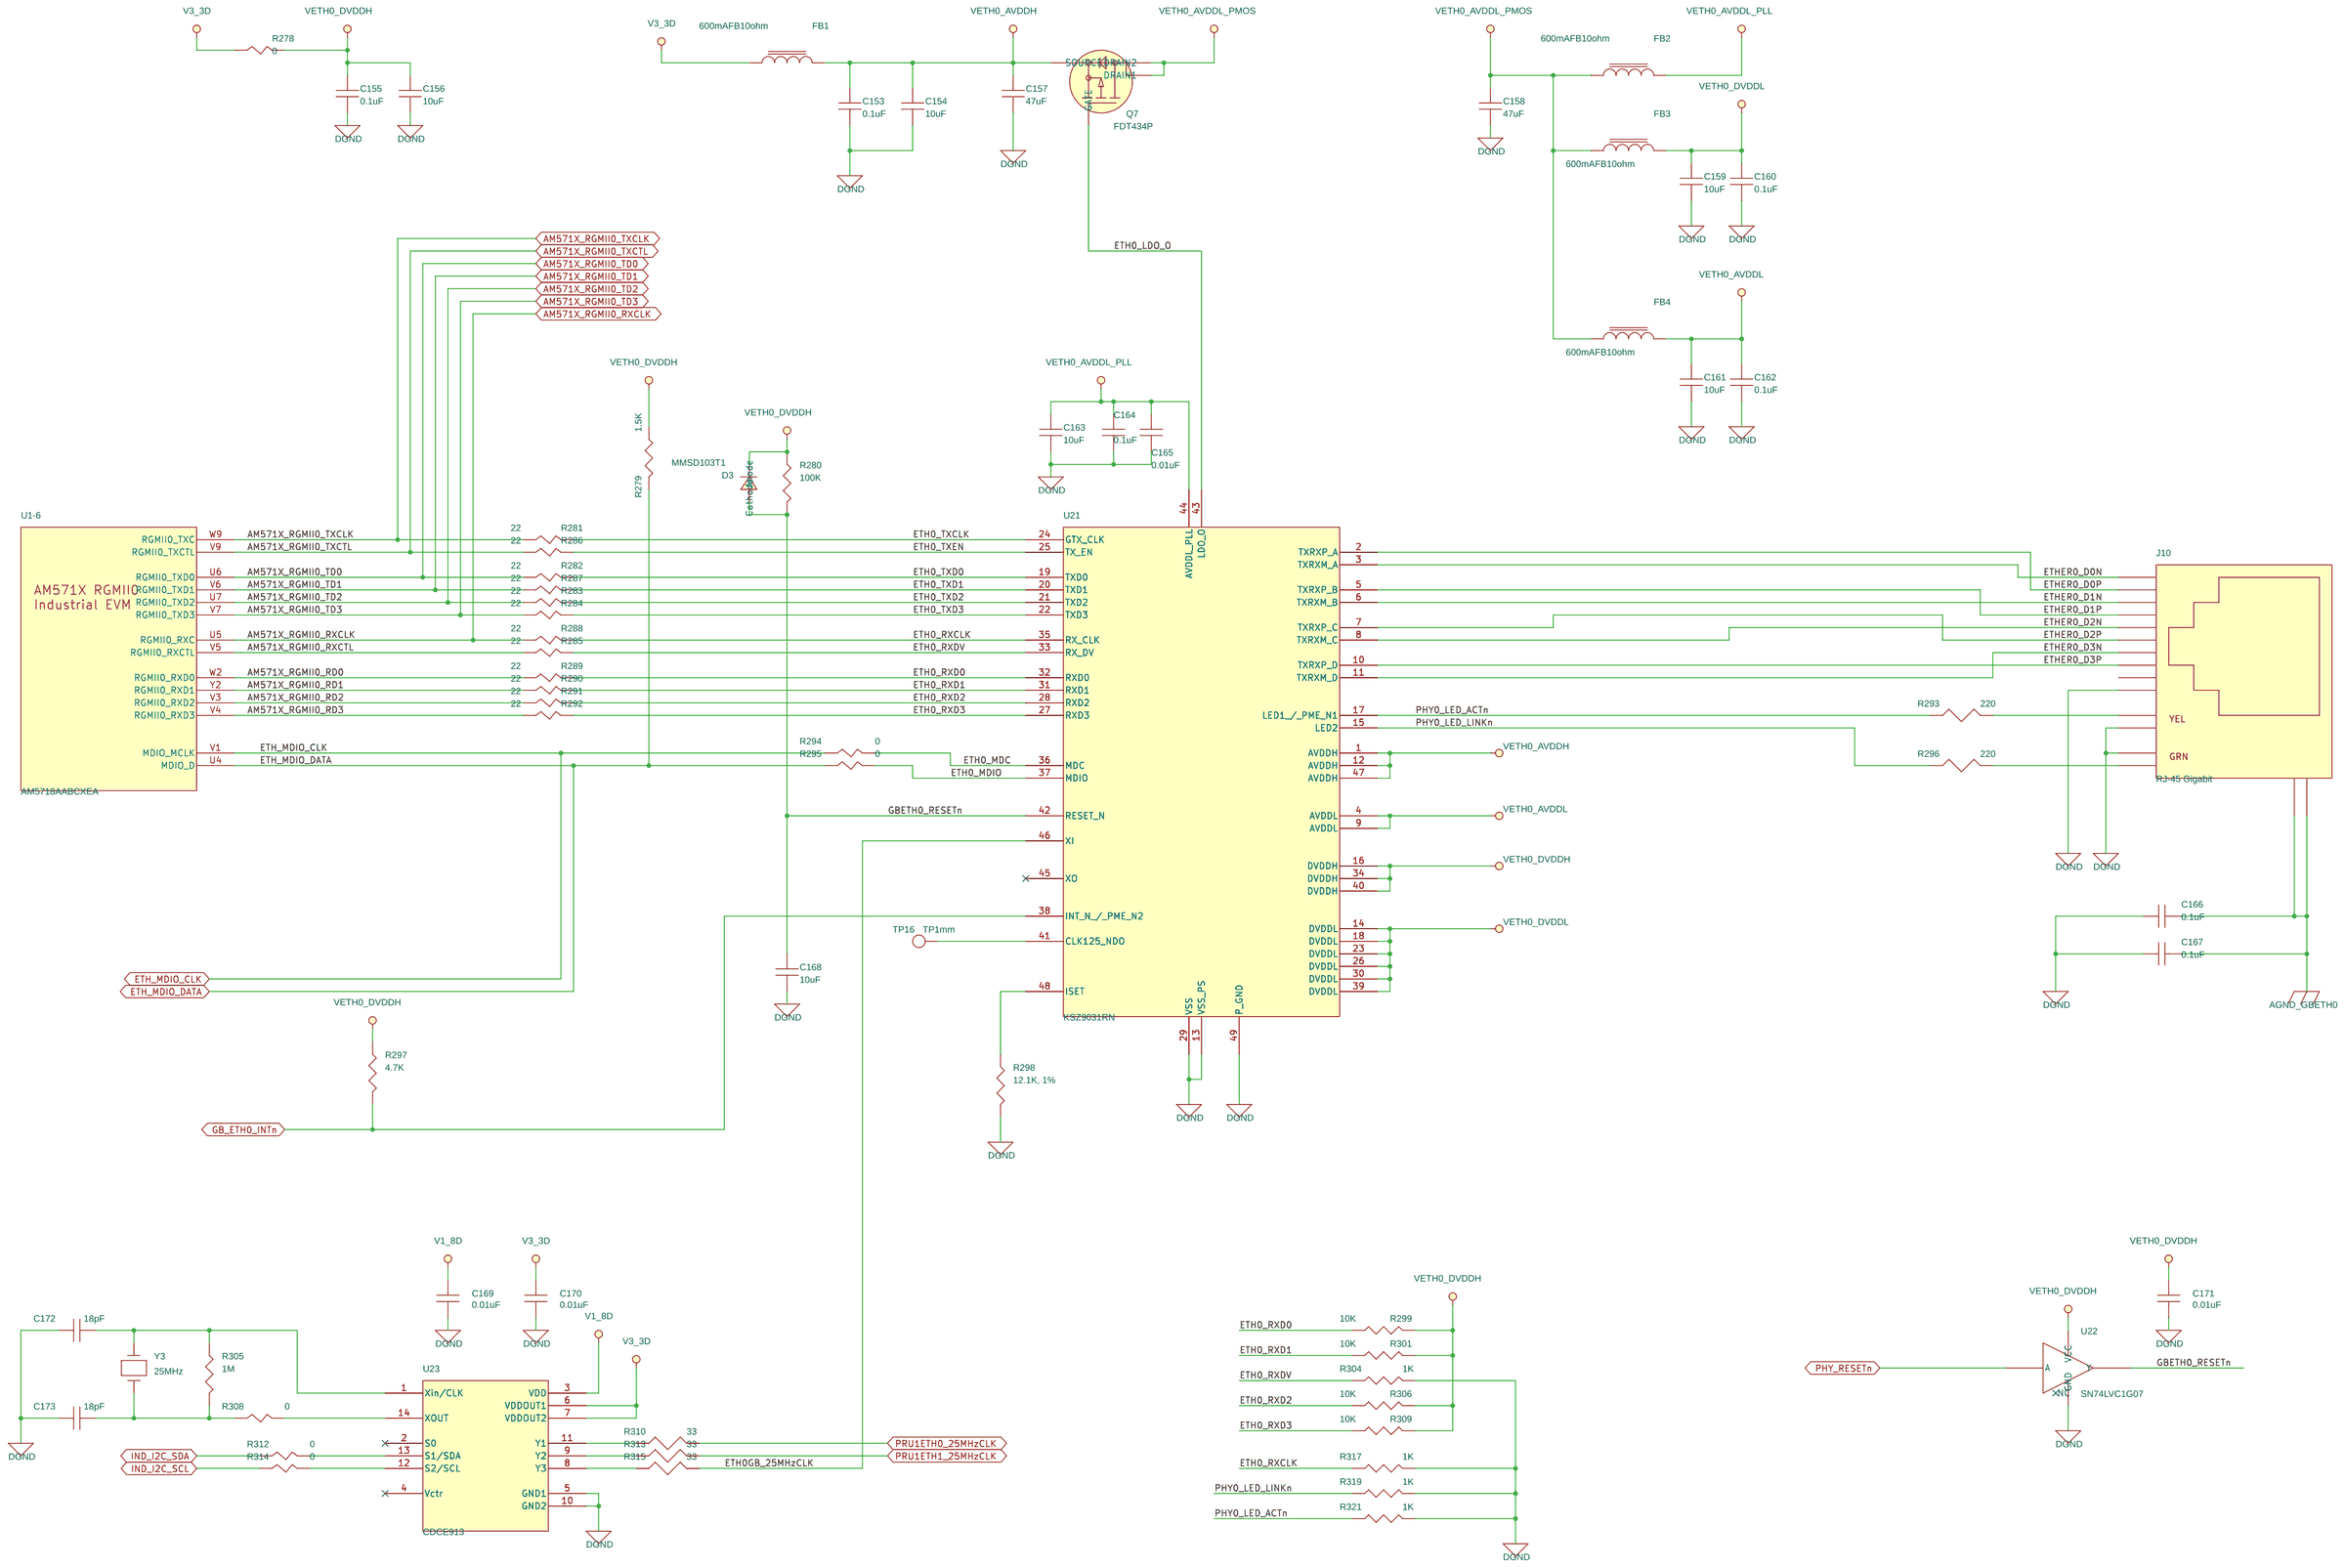
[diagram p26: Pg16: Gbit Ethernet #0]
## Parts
sheet Pg10: ICSS1 Ethernet 0
C102  0.1uF  [SM-7351-CAP-0402]
C103  0.1uF  [SM-7351-CAP-0402]
C104  0.1uF  [SM-7351-CAP-0402]
C105  0.01uF  [SM-7351-CAP-0402]
C106  4700pF  [SM-7351-CAP-0402]
C107  0.1uF  [SM-7351-CAP-0402]
C108  0.1uF  [SM-7351-CAP-0402]
C109  0.1uF  [SM-7351-CAP-0402]
C110  10uF  [SM-7351-CAP-0805]
C111  0.1uF  [SM-7351-CAP-0402]
C112  0.01uF  [SM-7351-CAP-0402]
C113  0.01uF  [SM-7351-CAP-0402]
J3  RJ-45 10_100Mb  [CNRJ45-1X1WLED]
R76  2.2K  [sm-7351-res-0402]
R77  0  [SM-7351-RES-0402]
R78  0  [SM-7351-RES-0402]
R79  0  [SM-7351-RES-0402]
R80  0  [SM-7351-RES-0402]
R81  0  [SM-7351-RES-0402]
R82  0  [SM-7351-RES-0402]
R83  0  [SM-7351-RES-0402]
R84  0  [SM-7351-RES-0402]
R85  0  [SM-7351-RES-0402]
R86  0  [SM-7351-RES-0402]
R87  0  [SM-7351-RES-0402]
R88  0  [SM-7351-RES-0402]
R89  0  [SM-7351-RES-0402]
R90  0  [SM-7351-RES-0402]
R91  0  [SM-7351-RES-0402]
R92  0  [SM-7351-RES-0402]
R93  0  [SM-7351-RES-0402]
R94  0  [SM-7351-RES-0402]
R95  0  [SM-7351-RES-0402]
R96  0  [SM-7351-RES-0402]
R97  0  [SM-7351-RES-0603]
R98  0  [SM-7351-RES-0402]
R99  49.9  [SM-7351-RES-0402]
R100  49.9  [SM-7351-RES-0402]
R101  49.9  [SM-7351-RES-0402]
R102  49.9  [SM-7351-RES-0402]
R103  4.87K  [SM-7351-RES-0402]
R104  2.2K  [sm-7351-res-0402]
R106  0  [SM-7351-RES-0402]
R107  10K  [SM-7351-RES-0402]
R108  2.2K  [sm-7351-res-0402]
R109  2.2K  [sm-7351-res-0402]
R110  2.2K  [sm-7351-res-0402]
R111  2.2K  [sm-7351-res-0402]
R112  0  [SM-7351-RES-0402]
U9  TLK105L  [qfn5x5-32-39m]
U68  SN74LVC1G08  [sm-so-sc70-5]
sheet Pg11: ICSS1 Ethernet 1
C116  0.1uF  [SM-7351-CAP-0402]
C117  0.1uF  [SM-7351-CAP-0402]
C118  0.01uF  [SM-7351-CAP-0402]
C119  0.1uF  [SM-7351-CAP-0402]
C120  0.01uF  [SM-7351-CAP-0402]
C121  4700pF  [SM-7351-CAP-0402]
C122  0.1uF  [SM-7351-CAP-0402]
C123  0.1uF  [SM-7351-CAP-0402]
C124  0.1uF  [SM-7351-CAP-0402]
C125  10uF  [SM-7351-CAP-0805]
C126  0.1uF  [SM-7351-CAP-0402]
C127  0.01uF  [SM-7351-CAP-0402]
J5  RJ-45 10_100Mb  [CNRJ45-1X1WLED]
R120  2.2K  [sm-7351-res-0402]
R121  0  [SM-7351-RES-0402]
R122  0  [SM-7351-RES-0402]
R123  0  [SM-7351-RES-0402]
R124  0  [SM-7351-RES-0402]
R125  0  [SM-7351-RES-0402]
R126  0  [SM-7351-RES-0402]
R127  0  [SM-7351-RES-0402]
R128  0  [SM-7351-RES-0402]
R129  0  [SM-7351-RES-0402]
R130  0  [SM-7351-RES-0402]
R131  2.2K  [sm-7351-res-0402]
R132  0  [SM-7351-RES-0402]
R133  0  [SM-7351-RES-0402]
R134  0  [SM-7351-RES-0402]
R135  0  [SM-7351-RES-0402]
R136  0  [SM-7351-RES-0402]
R137  0  [SM-7351-RES-0402]
R138  0  [SM-7351-RES-0603]
R139  0  [SM-7351-RES-0402]
R140  0  [SM-7351-RES-0402]
R141  0  [SM-7351-RES-0603]
R142  0  [SM-7351-RES-0402]
R143  49.9  [SM-7351-RES-0402]
R144  49.9  [SM-7351-RES-0402]
R145  49.9  [SM-7351-RES-0402]
R146  49.9  [SM-7351-RES-0402]
R147  4.87K  [SM-7351-RES-0402]
R148  0  [SM-7351-RES-0402]
R151  0  [SM-7351-RES-0402]
R152  2.2K  [sm-7351-res-0402]
R153  10K  [SM-7351-RES-0402]
R154  0  [SM-7351-RES-0402]
R155  2.2K  [sm-7351-res-0402]
R156  2.2K  [sm-7351-res-0402]
R157  2.2K  [sm-7351-res-0402]
R158  2.2K  [sm-7351-res-0402]
U13  TLK105L  [qfn5x5-32-39m]
U69  SN74LVC1G08  [sm-so-sc70-5]
sheet Pg12: ICSS2 Ethernet 0
C128  0.1uF  [SM-7351-CAP-0402]
C129  0.1uF  [SM-7351-CAP-0402]
C130  0.01uF  [SM-7351-CAP-0402]
C131  4700pF  [SM-7351-CAP-0402]
C132  0.1uF  [SM-7351-CAP-0402]
C133  0.1uF  [SM-7351-CAP-0402]
C134  0.1uF  [SM-7351-CAP-0402]
C135  0.1uF  [SM-7351-CAP-0402]
C136  10uF  [SM-7351-CAP-0805]
C137  0.01uF  [SM-7351-CAP-0402]
C138  0.1uF  [SM-7351-CAP-0402]
C139  0.01uF  [SM-7351-CAP-0402]
J6  RJ-45 10_100Mb  [CNRJ45-1X1WLED]
J7  HEADER 5  [HEADER_5X1]
R159  2.2K  [sm-7351-res-0402]
R160  0  [SM-7351-RES-0402]
R161  0  [SM-7351-RES-0402]
R162  0  [SM-7351-RES-0402]
R163  0  [SM-7351-RES-0402]
R164  0  [SM-7351-RES-0402]
R165  0  [SM-7351-RES-0402]
R166  0  [SM-7351-RES-0402]
R167  0  [SM-7351-RES-0402]
R168  0  [SM-7351-RES-0402]
R169  0  [SM-7351-RES-0402]
R170  0  [SM-7351-RES-0402]
R171  0  [SM-7351-RES-0402]
R172  0  [SM-7351-RES-0402]
R173  0  [SM-7351-RES-0402]
R174  0  [SM-7351-RES-0402]
R175  0  [SM-7351-RES-0402]
R176  0  [SM-7351-RES-0402]
R177  0  [SM-7351-RES-0402]
R178  DNI  [SM-7351-RES-0402]
R179  0  [SM-7351-RES-0402]
R180  0  [SM-7351-RES-0603]
R181  0  [SM-7351-RES-0402]
R182  49.9  [SM-7351-RES-0402]
R183  49.9  [SM-7351-RES-0402]
R184  49.9  [SM-7351-RES-0402]
R185  49.9  [SM-7351-RES-0402]
R186  4.87K  [SM-7351-RES-0402]
R187  2.2K  [sm-7351-res-0402]
R188  0  [SM-7351-RES-0402]
R189  0  [SM-7351-RES-0402]
R190  10K  [SM-7351-RES-0402]
R191  2.2K  [sm-7351-res-0402]
R192  2.2K  [sm-7351-res-0402]
R193  2.2K  [sm-7351-res-0402]
R194  2.2K  [sm-7351-res-0402]
R195  0  [SM-7351-RES-0402]
R196  0  [SM-7351-RES-0402]
R197  0  [SM-7351-RES-0402]
R198  0  [SM-7351-RES-0402]
R199  0  [SM-7351-RES-0402]
U15  TLK105L  [qfn5x5-32-39m]
U70  SN74LVC1G08  [sm-so-sc70-5]
sheet Pg13: ICSS2 Ethernet 1
C140  0.1uF  [SM-7351-CAP-0402]
C141  0.1uF  [SM-7351-CAP-0402]
C142  0.01uF  [SM-7351-CAP-0402]
C143  0.1uF  [SM-7351-CAP-0402]
C144  0.01uF  [SM-7351-CAP-0402]
C145  0.1uF  [SM-7351-CAP-0402]
C146  4700pF  [SM-7351-CAP-0402]
C147  0.1uF  [SM-7351-CAP-0402]
C148  0.1uF  [SM-7351-CAP-0402]
C149  10uF  [SM-7351-CAP-0805]
C150  0.1uF  [SM-7351-CAP-0402]
C151  0.01uF  [SM-7351-CAP-0402]
J4  HEADER 5  [HEADER_5X1]
J8  RJ-45 10_100Mb  [CNRJ45-1X1WLED]
R115  0  [SM-7351-RES-0402]
R117  0  [SM-7351-RES-0402]
R118  0  [SM-7351-RES-0402]
R119  0  [SM-7351-RES-0402]
R200  2.2K  [sm-7351-res-0402]
R201  2.2K  [sm-7351-res-0402]
R202  0  [SM-7351-RES-0402]
R203  0  [SM-7351-RES-0402]
R204  0  [SM-7351-RES-0402]
R205  0  [SM-7351-RES-0402]
R206  0  [SM-7351-RES-0402]
R207  0  [SM-7351-RES-0402]
R208  0  [SM-7351-RES-0402]
R209  0  [SM-7351-RES-0402]
R210  0  [SM-7351-RES-0402]
R211  0  [SM-7351-RES-0402]
R212  0  [SM-7351-RES-0402]
R213  0  [SM-7351-RES-0402]
R214  0  [SM-7351-RES-0402]
R215  0  [SM-7351-RES-0402]
R216  0  [SM-7351-RES-0402]
R217  0  [SM-7351-RES-0402]
R218  0  [SM-7351-RES-0603]
R219  0  [SM-7351-RES-0402]
R220  DNI  [SM-7351-RES-0402]
R221  0  [SM-7351-RES-0402]
R222  0  [SM-7351-RES-0603]
R223  0  [SM-7351-RES-0402]
R224  49.9  [SM-7351-RES-0402]
R225  49.9  [SM-7351-RES-0402]
R226  49.9  [SM-7351-RES-0402]
R227  49.9  [SM-7351-RES-0402]
R228  4.87K  [SM-7351-RES-0402]
R230  0  [SM-7351-RES-0402]
R231  0  [SM-7351-RES-0402]
R232  2.2K  [sm-7351-res-0402]
R233  10K  [SM-7351-RES-0402]
R234  0  [SM-7351-RES-0402]
R235  2.2K  [sm-7351-res-0402]
R236  2.2K  [sm-7351-res-0402]
R237  2.2K  [sm-7351-res-0402]
R238  2.2K  [sm-7351-res-0402]
U17  TLK105L  [qfn5x5-32-39m]
U71  SN74LVC1G08  [sm-so-sc70-5]
sheet Pg16: Gbit Ethernet #0
C153  0.1uF  [SM-7351-CAP-0402]
C154  10uF  [SM-7351-CAP-0805]
C155  0.1uF  [SM-7351-CAP-0402]
C156  10uF  [SM-7351-CAP-0805]
C157  47uF  [SM-7351-CAP-1206]
C158  47uF  [SM-7351-CAP-1206]
C159  10uF  [SM-7351-CAP-0805]
C160  0.1uF  [SM-7351-CAP-0402]
C161  10uF  [SM-7351-CAP-0805]
C162  0.1uF  [SM-7351-CAP-0402]
C163  10uF  [SM-7351-CAP-0805]
C164  0.1uF  [SM-7351-CAP-0402]
C165  0.01uF  [SM-7351-CAP-0402]
C166  0.1uF  [SM-7351-CAP-0402]
C167  0.1uF  [SM-7351-CAP-0402]
C168  10uF  [SM-7351-CAP-0805]
C169  0.01uF  [SM-7351-CAP-0402]
C170  0.01uF  [SM-7351-CAP-0402]
C171  0.01uF  [SM-7351-CAP-0402]
C172  18pF  [SM-7351-CAP-0402]
C173  18pF  [SM-7351-CAP-0402]
D3  MMSD103T1  [sod-123]
FB1  600mAFB10ohm  [HF70ACB201209]
FB2  600mAFB10ohm  [HF70ACB201209]
FB3  600mAFB10ohm  [HF70ACB201209]
FB4  600mAFB10ohm  [HF70ACB201209]
J10  RJ-45 Gigabit  [CNRJ45-1X1WLED-598M]
Q7  FDT434P  [SOT223-4]
R278  0  [SM-7351-RES-0603]
R279  1.5K  [SM-7351-RES-0402]
R280  100K  [SM-7351-RES-0402]
R281  22  [SM-7351-RES-0402]
R282  22  [SM-7351-RES-0402]
R283  22  [SM-7351-RES-0402]
R284  22  [SM-7351-RES-0402]
R285  22  [SM-7351-RES-0402]
R286  22  [SM-7351-RES-0402]
R287  22  [SM-7351-RES-0402]
R288  22  [SM-7351-RES-0402]
R289  22  [SM-7351-RES-0402]
R290  22  [SM-7351-RES-0402]
R291  22  [SM-7351-RES-0402]
R292  22  [SM-7351-RES-0402]
R293  220  [SM-7351-RES-0402]
R294  0  [SM-7351-RES-0402]
R295  0  [SM-7351-RES-0402]
R296  220  [SM-7351-RES-0402]
R297  4.7K  [SM-7351-RES-0402]
R298  12.1K, 1%  [SM-7351-RES-0402]
R299  10K  [SM-7351-RES-0402]
R301  10K  [SM-7351-RES-0402]
R304  1K  [SM-7351-RES-0402]
R305  1M  [SM-7351-RES-0402]
R306  10K  [SM-7351-RES-0402]
R308  0  [SM-7351-RES-0402]
R309  10K  [SM-7351-RES-0402]
R310  33  [SM-7351-RES-0402]
R312  0  [SM-7351-RES-0402]
R313  33  [SM-7351-RES-0402]
R314  0  [SM-7351-RES-0402]
R315  33  [SM-7351-RES-0402]
R317  1K  [SM-7351-RES-0402]
R319  1K  [SM-7351-RES-0402]
R321  1K  [SM-7351-RES-0402]
TP16  TP1mm  [tp_smd1mmcircle]
U21  KSZ9031RN  [qfn7x7-48]
U22  SN74LVC1G07  [SC70-5-43M]
U23  CDCE913  [TSSOP5X4-14-47M]
Y3  25MHz  [SM_OSC_ABM3]
sheet Pg17: Gbit Ethernet #1
C174  0.1uF  [SM-7351-CAP-0402]
C175  10uF  [SM-7351-CAP-0805]
C176  0.1uF  [SM-7351-CAP-0402]
C177  10uF  [SM-7351-CAP-0805]
C178  47uF  [SM-7351-CAP-1206]
C179  47uF  [SM-7351-CAP-1206]
C180  10uF  [SM-7351-CAP-0805]
C181  0.1uF  [SM-7351-CAP-0402]
C182  10uF  [SM-7351-CAP-0805]
C183  0.1uF  [SM-7351-CAP-0402]
C184  10uF  [SM-7351-CAP-0805]
C185  0.1uF  [SM-7351-CAP-0402]
C186  0.01uF  [SM-7351-CAP-0402]
C187  0.1uF  [SM-7351-CAP-0402]
C188  0.1uF  [SM-7351-CAP-0402]
C189  10uF  [SM-7351-CAP-0805]
C190  0.01uF  [SM-7351-CAP-0402]
C191  0.01uF  [SM-7351-CAP-0402]
C192  0.01uF  [SM-7351-CAP-0402]
C193  18pF  [SM-7351-CAP-0402]
C194  18pF  [SM-7351-CAP-0402]
D4  MMSD103T1  [sod-123]
FB5  600mAFB10ohm  [HF70ACB201209]
FB6  600mAFB10ohm  [HF70ACB201209]
FB7  600mAFB10ohm  [HF70ACB201209]
FB8  600mAFB10ohm  [HF70ACB201209]
J12  RJ-45 Gigabit  [CNRJ45-1X1WLED-598M]
Q8  FDT434P  [SOT223-4]
R322  0  [SM-7351-RES-0603]
R324  100K  [SM-7351-RES-0402]
R325  22  [SM-7351-RES-0402]
R326  22  [SM-7351-RES-0402]
R327  22  [SM-7351-RES-0402]
R328  22  [SM-7351-RES-0402]
R329  22  [SM-7351-RES-0402]
R330  22  [SM-7351-RES-0402]
R331  22  [SM-7351-RES-0402]
R332  22  [SM-7351-RES-0402]
R333  22  [SM-7351-RES-0402]
R334  22  [SM-7351-RES-0402]
R335  22  [SM-7351-RES-0402]
R336  22  [SM-7351-RES-0402]
R337  220  [SM-7351-RES-0402]
R338  0  [SM-7351-RES-0402]
R339  0  [SM-7351-RES-0402]
R340  220  [SM-7351-RES-0402]
R341  12.1K, 1%  [SM-7351-RES-0402]
R342  4.7K  [SM-7351-RES-0402]
R343  10K  [SM-7351-RES-0402]
R345  10K  [SM-7351-RES-0402]
R348  1K  [SM-7351-RES-0402]
R349  1M  [SM-7351-RES-0402]
R351  0  [SM-7351-RES-0402]
R352  10K  [SM-7351-RES-0402]
R353  10K  [SM-7351-RES-0402]
R354  33  [SM-7351-RES-0402]
R356  DNI  [SM-7351-RES-0402]
R357  33  [SM-7351-RES-0402]
R358  DNI  [SM-7351-RES-0402]
R359  33  [SM-7351-RES-0402]
R361  1K  [SM-7351-RES-0402]
R363  1K  [SM-7351-RES-0402]
R364  10K  [SM-7351-RES-0402]
TP17  TP1mm  [tp_smd1mmcircle]
U24  KSZ9031RN  [qfn7x7-48]
U25  CDCE913  [TSSOP5X4-14-47M]
U26  SN74LVC1G07  [SC70-5-43M]
Y4  25MHz  [SM_OSC_ABM3]
sheet Pg18: SDMMC #1 Interface
C211  0.1uF  [SM-7351-CAP-0402]
C212  4.7uF  [SM-7351-CAP-0603]
J15  SCHA5B0200  [SD-MICRO-SCHA5B0300]
J44  DNI HEADER 2  [header_2x1]
R397  10K  [SM-7351-RES-0402]
R398  10K  [SM-7351-RES-0402]
R399  10K  [SM-7351-RES-0402]
R400  10K  [SM-7351-RES-0402]
R401  10K  [SM-7351-RES-0402]
R402  0  [SM-7351-RES-0402]
R403  0  [SM-7351-RES-0402]
R404  0  [SM-7351-RES-0402]
R405  0  [SM-7351-RES-0402]
R406  0  [SM-7351-RES-0402]
R407  0  [SM-7351-RES-0402]
R408  470K  [SM-7351-RES-0402]
R409  0  [SM-7351-RES-0402]
R644  10K  [SM-7351-RES-0402]
U30  TPD6E001  [U_10_RSE]
U84  TPD1E10B06  [tpd1e10b06-2l]
sheet Pg29: RS-485
U1  AM5718AABCXEA  [BGA23X23-760-117M]  (sections -1,-10,-11,-12,-13,-14,-15,-16,-17,-18,-19,-2,-20,-21,-22,-23,-24,-25,-26,-27,-3,-4,-5,-6,-7,-8,-9)
sheet Pg30: PCIE Connector
C303  0.1uF  [SM-7351-CAP-0402]
C304  0.1uF  [SM-7351-CAP-0402]
C305  10uF  [SM-7351-CAP-0805]
C306  10uF  [SM-7351-CAP-0805]
C307  10uF  [SM-7351-CAP-0805]
C308  0.01uF  [SM-7351-CAP-0402]
C309  0.01uF  [SM-7351-CAP-0402]
C310  0.01uF  [SM-7351-CAP-0402]
C320  10uF  [SM-7351-CAP-0805]
C321  0.01uF  [SM-7351-CAP-0402]
C322  0.01uF  [SM-7351-CAP-0402]
C324  0.01uF  [SM-7351-CAP-0402]
C326  0.01uF  [SM-7351-CAP-0402]
C436  0.1uF  [SM-7351-CAP-0402]
C437  0.1uF  [SM-7351-CAP-0402]
C438  0.1uF  [SM-7351-CAP-0402]
C439  0.1uF  [SM-7351-CAP-0402]
C469  0.01uF  [SM-7351-CAP-0402]
C470  0.01uF  [SM-7351-CAP-0402]
C477  0.1uF  [SM-7351-CAP-0402]
C478  0.1uF  [SM-7351-CAP-0402]
C581  0.1uF  [SM-7351-CAP-0402]
C582  0.1uF  [SM-7351-CAP-0402]
FB13  150OHM800mA  [sm-7351-ind-0805]
J49  HEADER 2  [header_2x1]
J52  10061913  [CNPCIE64SMT]
L3  NFM21PC474  [FILT-NFM21PC]
M1  Shunt0.1in  [DNP]
R539  10K  [SM-7351-RES-0402]
R542  10K  [SM-7351-RES-0402]
R543  10K  [SM-7351-RES-0402]
R544  10K  [SM-7351-RES-0402]
R545  10K  [SM-7351-RES-0402]
R546  10K  [SM-7351-RES-0402]
R547  DNI  [SM-7351-RES-0402]
R548  10K  [SM-7351-RES-0402]
R549  10K  [SM-7351-RES-0402]
R550  0  [SM-7351-RES-0402]
R568  0  [SM-7351-RES-0402]
R580  100  [SM-7351-RES-0402]
R581  100  [SM-7351-RES-0402]
R649  10K  [SM-7351-RES-0402]
R650  100  [SM-7351-RES-0402]
R652  0  [SM-7351-RES-0402]
R653  0  [SM-7351-RES-0402]
R654  10K  [SM-7351-RES-0402]
R655  100  [SM-7351-RES-0402]
TP20  TP1mm  [tp_smd1mmcircle]
U44  74LVC1G125  [SC70-5-43M]
U45  CDCM9102  [qfn5x5-32ti-39m]
U85  SN74LVC1G08  [sm-so-sc70-5]
Y7  25MHz  [asf_smd3_2x5mm]

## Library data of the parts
C102-C104 C107-C109 C111 C116 C117 C119 C122-C124 C126 C128 C129 C132-C135 C138 C140 C141 C143 C145 C147 C148 C150 C153 C155 C160 C162 C164 C174 C176 C181 C183 C185 C211 C436-C439 C477 C478 C581 C582 = 1C_0.1uFCapacitor16V10%0402
C105 C112 C113 C118 C120 C127 C130 C137 C139 C142 C144 C151 C165 C169-C171 C186 C190-C192 C308-C310 C321 C322 C324 C326 C469 C470 = 1C_0.01uFCapacitor16V10%0402
C106 C121 C131 C146 = 1C_4700pFCapacitor50V10%0402
C110 C125 C136 C149 C154 C156 C159 C161 C163 C168 C175 C177 C180 C182 C184 C189 C305-C307 C320 = 1C_10uFCapacitor16V10%0805
J3 J5 J6 J8 = 2J_ConnectorRJ45_10_100MbAMDIX
R76 R104 R108-R111 R120 R131 R152 R155-R159 R187 R191-R194 R200 R201 R232 R235-R238 = 1R_2.2KOhmResistor1_16W0402
R77-R96 R98 R106 R112 R115 R117-R119 R121-R130 R132-R137 R139 R140 R142 R148 R151 R154 R160-R179 R181 R188 R189 R195-R199 R202-R217 R219-R221 R223 R230 R231 R234 R294 R295 R308 R312 R314 R338 R339 R351 R356 R358 R402-R407 R409 R547 R550 R568 R652 R653 = 1R_ZeroOhmResistor1_16W0402
R97 R138 R141 R180 R218 R222 R278 R322 = 1R_ZeroOhmResistor1_16W0603
R99-R102 R143-R146 R182-R185 R224-R227 = 1R_49.9OhmResistor1_16W0402
R103 R147 R186 R228 = 1R_4.87Kohm1_16W1%smd0402
R107 R153 R190 R233 R299 R301 R306 R309 R343 R345 R352 R353 R364 R397-R401 R539 R542-R546 R548 R549 R644 R649 R654 = 1R_10KOhmResistor1_16W0402
U9 U13 U15 U17 = 1A_TLK105L
U68-U71 U85 = 1A_SN74LVC1G08DCKT_SC70
J4 J7 = 2H_Header_5x1
C157 C158 C178 C179 = 1C_47uFCapacitor16V20%1206
C166 C167 C187 C188 C303 C304 = 1C_0.1uFCapacitor50V10%0402
C172 C173 C193 C194 = 1C_18pFCapacitor16V10%0402
D3 D4 = Diode200mA250V: TIIntPartnumber: _1E0013
FB1-FB8 = 1L_FerriteBead_600mA10ohm
J10 J12 = 2J_ConnectorRJ45_Gigabit
Q7 Q8 = 1Q_MOSFET_PChan_FDT434P
R279 = 1R_1.5KohmResistor1_16W5%0402
R280 R324 = 1R_100KOhmResistor1_16W0402
R281-R292 R325-R336 = 1R_22OhmResistor1_16W1%0402
R293 R296 R337 R340 = 1R_220ohm1_10W1%smd0402
R297 R342 = 1R_4.7KOhmResistor1_16W0402
R298 R341 = 1R_12.1KohmResistor1_16W1%0402
R304 R317 R319 R321 R348 R361 R363 = 1R_1KOhmResistor1_16W0402
R305 R349 = 1MOhmResistor1_16W0402
R310 R313 R315 R354 R357 R359 = 1R_33ohmResistor1_16W5%0402
TP16 TP17 TP20 = 2H_Testpoint_SMD1mmCircle
U21 U24 = 1A_KSZ9031RNX
U22 U26 = 1A_SN74LVC1G07
U23 U25 = 1A_CDCE913
Y3 Y4 = 1Y_Crystal25MHzABM3
C212 = 1C_4.7uFCapacitor16V10%0603
J15 = 2C_Conn_microSD_8
J44 J49 = 2H_Header_2x1
R408 = 470Kohm1_16W1%SMD0402
U30 = 1A_TPD6E001RSE
U84 = 1A_TPD1E10B06
U1 = AM571X_ABCpkg_Industrial_10
FB13 = 1L_FerBead_180ohm200mA
J52 = 2C_PCIEConnector_x4SMT_10061913: DescriptiveText: PCIE Connector Card Edge Type 64pin; MfrNum: 10061913-101TLF; PartName: PCIE_Connector64pin
L3 = 1L_NFM21PC474_EMIFilter
M1 = 2H_Shunt0.1in
R580 R581 R650 R655 = 1R_100ohm1_16W1%SMD0402
U44 = 1A_SN74LVC1G125
U45 = 1A_CDCM9102
Y7 = 1Y_Oscillator25MHzSMD

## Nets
AGND_GBETH0: C166.2 C167.2 J10.SHLD1 J10.SHLD2
AGND_GBETH1: C187.2 C188.2 J12.SHLD1 J12.SHLD2
AGNDFRAME_PRU1ETH0: C106.2 J3.SHLD1 J3.SHLD2
AGNDFRAME_PRU1ETH1: C121.2 J5.SHLD1 J5.SHLD2
AGNDFRAME_PRU2ETH0: C131.2 J6.SHLD1 J6.SHLD2
AGNDFRAME_PRU2ETH1: C146.2 J8.SHLD1 J8.SHLD2
DGND: C102.2 C103.2 C104.2 C105.2 C106.1 C107.2 C108.2 C109.2 C110.2 C111.2 C112.2 C113.2 C116.2 C117.2 C118.2 C119.2 C120.2 C121.1 C122.2 C123.2 C124.2 C125.2 C126.2 C127.2 C128.2 C129.2 C130.2 C131.1 C132.2 C133.2 C134.2 C135.2 C136.2 C137.2 C138.2 C139.2 C140.2 C141.2 C142.2 C143.2 C144.2 C145.2 C146.1 C147.2 C148.2 C149.2 C150.2 C151.2 C153.2 C154.2 C155.2 C156.2 C157.2 C158.2 C159.2 C160.2 C161.2 C162.2 C163.2 C164.2 C165.2 C166.1 C167.1 C168.2 C169.2 C170.2 C171.2 C172.1 C173.1 C174.2 C175.2 C176.2 C177.2 C178.2 C179.2 C180.2 C181.2 C182.2 C183.2 C184.2 C185.2 C186.2 C187.1 C188.1 C189.2 C190.2 C191.2 C192.2 C193.1 C194.1 C211.2 C212.2 C303.2 C304.2 C305.2 C306.2 C307.2 C308.2 C309.2 C310.2 C320.2 C321.2 C322.2 C324.2 C326.2 C469.2 C470.2 J3.8 J4.5 J5.8 J6.8 J7.5 J8.8 J10.1 J10.12 J10.13 J12.1 J12.12 J12.13 J15.6(VSS) J15.9(GND) J15.11(GND3) J15.12(GND4) J15.13(GND5) J15.14(GND6) J15.15(GND7) J15.16(GND8) J44.2 J52.A4 J52.A12 J52.A15 J52.A18 J52.A20 J52.A23 J52.A24 J52.A27 J52.A28 J52.A31 J52.B4 J52.B7 J52.B13 J52.B16 J52.B18 J52.B21 J52.B22 J52.B25 J52.B26 J52.B29 J52.B31 J52.B32 L3.2(GND) R103.1(P1) R104.1(P1) R108.1(P1) R109.1(P1) R110.1(P1) R111.1(P1) R147.1(P1) R155.1(P1) R156.1(P1) R157.1(P1) R158.1(P1) R186.1(P1) R187.1(P1) R191.1(P1) R192.1(P1) R193.1(P1) R194.1(P1) R228.1(P1) R235.1(P1) R236.1(P1) R237.1(P1) R238.1(P1) R298.2 R304.1(P1) R317.1(P1) R319.1(P1) R321.1(P1) R341.2 R348.1(P1) R361.1(P1) R363.1(P1) R539.2(P2) R542.1(P1) R547.2(P2) R550.2(P2) U9.TPAD U13.TPAD U15.TPAD U17.TPAD U21.13(VSS_PS) U21.29(VSS) U21.49(P_GND) U22.3(GND) U23.5(GND1) U23.10(GND2) U24.13(VSS_PS) U24.29(VSS) U24.49(P_GND) U25.5(GND1) U25.10(GND2) U26.3(GND) U30.5(GND) U44.3(GND) U45.14(GND) U45.22(GND) U45.TPAD(PWRPAD) U68.3(GND) U69.3(GND) U70.3(GND) U71.3(GND) U84.2 U85.3(GND) Y7.2(GND) ; also on sheet 1 2 3 4 5 6 7 8 9 10 11 12 14 15 16 17 18 19 28 29 30 31 32
V1_8D: C169.1 C190.1 U23.3(VDD) U25.3(VDD) ; also on sheet 4 9 17 31
V3_3ACDCM: C320.1 C321.1 C322.1 C324.1 L3.3(OUT) U45.1(VDD2_OUT1) U45.4(VDD1_OUT0)
V3_3APCIE: C307.1 C308.1 C309.1 C310.1 C326.1 FB13.1 R546.2(P2) R548.2(P2) R549.2(P2) U45.9(VDD) U45.16(VDD) U45.18(VDD) U45.20(VDD) Y7.4(VCC)
V3_3AUX_PCIE: J49.2 J52.B10 R654.2(P2)
V3_3D: C104.1 C105.1 C107.1 C113.1 C119.1 C120.1 C122.1 C127.1 C130.1 C132.1 C133.1 C139.1 C143.1 C144.1 C145.1 C151.1 C170.1 C191.1 C211.1 C212.1 C469.1 C470.1 FB1.1 FB5.1 FB13.2 J15.4(VDD) J49.1 J52.A9 J52.A10 J52.B8 L3.1(IN) R76.2(P2) R77.2(P2) R78.2(P2) R89.2(P2) R97.1(P1) R99.1(P1) R100.1(P1) R101.1(P1) R102.1(P1) R107.2(P2) R120.2(P2) R121.2(P2) R122.2(P2) R131.2(P2) R134.2(P2) R141.1(P1) R143.1(P1) R144.1(P1) R145.1(P1) R146.1(P1) R152.2(P2) R153.2(P2) R159.2(P2) R160.2(P2) R161.2(P2) R172.2(P2) R180.1(P1) R182.1(P1) R183.1(P1) R184.1(P1) R185.1(P1) R190.2(P2) R200.2(P2) R201.2(P2) R202.2(P2) R203.2(P2) R214.2(P2) R222.1(P1) R224.1(P1) R225.1(P1) R226.1(P1) R227.1(P1) R232.2(P2) R233.2(P2) R278.2(P2) R322.2(P2) R543.1(P1) R544.1(P1) R545.2(P2) R649.2(P2) U9.21(VDD33_IO) U13.21(VDD33_IO) U15.21(VDD33_IO) U17.21(VDD33_IO) U23.6(VDDOUT1) U23.7(VDDOUT2) U25.6(VDDOUT1) U25.7(VDDOUT2) U30.10(VCC) U44.5(VCC) U68.5(VCC) U69.5(VCC) U70.5(VCC) U71.5(VCC) U85.5(VCC) ; also on sheet 1 2 3 4 5 6 7 8 9 10 11 12 14 15 17 18 19 28 29 30 31 32
V3_3D_PRU1ETH0JCK: C102.1 C103.1 J3.3 J3.4 R77.1(P1)
V3_3D_PRU1ETH1JCK: C116.1 C117.1 J5.3 J5.4 R121.1(P1)
V3_3D_PRU2ETH0JCK: C128.1 C129.1 J6.3 J6.4 R160.1(P1)
V3_3D_PRU2ETH1JCK: C140.1 C141.1 J8.3 J8.4 R202.1(P1)
V12_0D: C303.1 C304.1 J52.A2 J52.A3 J52.B1 J52.B2 J52.B3 ; also on sheet 18 19
AM57XX_MMC1_CLK: R405.2(P2) U1.W6(MMC1_CLK)
AM57XX_MMC1_CMD: R404.2(P2) U1.Y6(MMC1_CMD)
AM57XX_MMC1_DAT0: R406.2(P2) U1.AA6(MMC1_DAT0)
AM57XX_MMC1_DAT1: R407.2(P2) U1.Y4(MMC1_DAT1)
AM57XX_MMC1_DAT2: R402.2(P2) U1.AA5(MMC1_DAT2)
AM57XX_MMC1_DAT3: R403.2(P2) U1.Y3(MMC1_DAT3)
AM57XX_MMC1_SDCD: R409.2(P2) U1.W7(MMC1_SDCD)
AM57XX_MMC1_SDWP: J44.1 R644.1(P1) U1.Y9(MMC1_SDWP)
AM57XX_PCIE_PERn0: J52.A17 U1.AG13(PCIE_RXN0)
AM57XX_PCIE_PERn1: J52.A22 U1.AF12(PCIE_RXN1)
AM57XX_PCIE_PERp0: J52.A16 U1.AH13(PCIE_RXP0)
AM57XX_PCIE_PERp1: J52.A21 U1.AE12(PCIE_RXP1)
AM57XX_PCIE_PETn0: C477.1 U1.AG14(PCIE_TXN0)
AM57XX_PCIE_PETn1: C581.1 U1.AC11(PCIE_TXN1)
AM57XX_PCIE_PETp0: C478.1 U1.AH14(PCIE_TXP0)
AM57XX_PCIE_PETp1: C582.1 U1.AD11(PCIE_TXP1)
AM57XX_PCIE_REF_CLKN: C438.2 R581.1(P1) U1.AH15(LJCB_CLKN)
AM57XX_PCIE_REF_CLKP: C439.2 R581.2(P2) U1.AG15(LJCB_CLKP)
AM57XX_PR1_UART0_TXD: R199.2(P2) ; also on sheet 12 29
AM57XX_PRU1ETH1_TXCLK: R123.2(P2) U1.C1(VIN2A_D6/PR1_MII_MT1_CLK)
AM57XX_PRU1ETH1_TXD2: R127.2(P2) U1.E6(VIN2A_D9/PR1_MII1_TXD2)
AM57XX_PRU1ETH1_TXD3: R128.2(P2) U1.F5(VIN2A_D8/PR1_MII1_TXD3)
AM57XX_PRU1ETH1_TXEN: R124.2(P2) U1.E4(VIN2A_D7/PR1_MII1_TXEN)
AM57XX_PRU1ETH_MDCLK: R96.2(P2) R140.2(P2) U1.D3(VIN2A_D10/PR1_MDIO_MDCLK)
AM57XX_PRU1ETH_MDDATA: R98.2(P2) R142.2(P2) U1.F6(VIN2A_D11/PR1_MDIO_DATA)
AM57XX_PRU2ETH0_COL: R178.2(P2) U1.F15(MCASP3_FSX/PR2_MII0_COL) ; also on sheet 29
AM57XX_PRU2ETH0_CRS: R177.2(P2) U1.B18(MCASP3_ACLKX/PR2_MII0_CRS) ; also on sheet 29
AM57XX_PRU2ETH0_MRCLK: R165.2(P2) U1.A13(MCASP1_AXR13/PR2_MII_MR0_CLK)
AM57XX_PRU2ETH0_RXD0: R171.2(P2) U1.C15(MCASP2_AXR2/PR2_MII0_RXD0)
AM57XX_PRU2ETH0_RXD1: R173.2(P2) U1.A18(MCASP2_FSX/PR2_MII0_RXD1)
AM57XX_PRU2ETH0_RXD2: R174.2(P2) U1.A19(MCASP2_ACLKX/PR2_MII0_RXD2)
AM57XX_PRU2ETH0_RXD3: R175.2(P2) U1.F14(MCASP1_AXR15/PR2_MII0_RXD3)
AM57XX_PRU2ETH0_RXDV: R166.2(P2) R197.2(P2) U1.G14(MCASP1_AXR14/PR2_MII0_RXDV)
AM57XX_PRU2ETH0_RXER: R170.2(P2) U1.G12(MCASP1_AXR0/PR2_MII0_RXER)
AM57XX_PRU2ETH0_RXLINK: R188.2(P2) U1.A16(MCASP2_AXR3/PR2_MII0_RXLINK)
AM57XX_PRU2ETH0_TXCLK: R162.2(P2) U1.F12(MCASP1_AXR1/PR2_MII_MT0_CLK)
AM57XX_PRU2ETH0_TXD0: R163.2(P2) U1.E14(MCASP1_AXR12/PR2_MII0_TXD0)
AM57XX_PRU2ETH0_TXD1: R164.2(P2) U1.A12(MCASP1_AXR11/PR2_MII0_TXD1)
AM57XX_PRU2ETH0_TXD2: R168.2(P2) U1.B13(MCASP1_AXR10/PR2_MII0_TXD2)
AM57XX_PRU2ETH0_TXD3: R169.2(P2) U1.A11(MCASP1_AXR9/PR2_MII0_TXD3)
AM57XX_PRU2ETH0_TXEN: R167.2(P2) R196.2(P2) U1.B12(MCASP1_AXR8/PR2_MII0_TXEN)
AM57XX_PRU2ETH1_COL: R220.2(P2) U1.D18(XREF_CLK0/PR2_MII1_COL) ; also on sheet 29
AM57XX_PRU2ETH1_CRS: R219.2(P2) U1.E17(XREF_CLK1/PR2_MII1_CRS) ; also on sheet 29
AM57XX_PRU2ETH1_MRCLK: R209.2(P2) U1.AC9(MMC3_DAT2/PR2_MII_MR1_CLK)
AM57XX_PRU2ETH1_RXD0: R213.2(P2) U1.AB5(MMC3_DAT7/PR2_MII1_RXD0)
AM57XX_PRU2ETH1_RXD1: R215.2(P2) U1.AB8(MMC3_DAT6/PR2_MII1_RXD1)
AM57XX_PRU2ETH1_RXD2: R216.2(P2) U1.AD6(MMC3_DAT5/PR2_MII1_RXD2)
AM57XX_PRU2ETH1_RXD3: R217.2(P2) U1.AC8(MMC3_DAT4/PR2_MII1_RXD3)
AM57XX_PRU2ETH1_RXDV: R211.2(P2) U1.AC3(MMC3_DAT3/PR2_MII1_RXDV)
AM57XX_PRU2ETH1_RXER: R212.2(P2) U1.B19(MCASP3_AXR0/PR2_MII1_RXER)
AM57XX_PRU2ETH1_TXCLK: R204.2(P2) U1.AC5(GPIO6_10/PR2_MII_MT1_CLK)
AM57XX_PRU2ETH1_TXD0: R206.2(P2) U1.AC6(MMC3_DAT1/PR2_MII1_TXD0)
AM57XX_PRU2ETH1_TXD1: R208.2(P2) U1.AC7(MMC3_DAT0/PR2_MII1_TXD1)
AM57XX_PRU2ETH1_TXD2: R210.2(P2) U1.AC4(MMC3_CMD/PR2_MII1_TXD2)
AM57XX_PRU2ETH1_TXD3: R207.2(P2) U1.AD4(MMC3_CLK/PR2_MII1_TXD3)
AM57XX_PRU2ETH1_TXEN: R205.2(P2) U1.AB4(GPIO6_11/PR2_MII1_TXEN)
AM57XX_PRU2ETH_MDCLK: R179.2(P2) R221.2(P2) U1.C14(MCASP1_ACLKX/PR2_MDIO_MDCLK)
AM57XX_PRU2ETH_MDDATA: R181.2(P2) R223.2(P2) U1.D14(MCASP1_FSX/PR2_MDIO_DATA)
AM57XX_RGMII1_RD0: R333.2(P2) U1.A4(VIN2A_D23/RGMII1_RXD0)
AM57XX_RGMII1_RD1: R334.2(P2) U1.B5(VIN2A_D22/RGMII1_RXD1)
AM57XX_RGMII1_RD2: R335.2(P2) U1.B4(VIN2A_D21/RGMII1_RXD2)
AM57XX_RGMII1_RD3: R336.2(P2) U1.B3(VIN2A_D20/RGMII1_RXD3)
AM57XX_RGMII1_RXCLK: R328.2(P2) U1.C5(VIN2A_D18/RGMII1_RXC)
AM57XX_RGMII1_RXCTL: R329.2(P2) U1.A3(VIN2A_D19/RGMII1_RXCTL)
AM57XX_RGMII1_TD0: R330.2(P2) U1.D6(VIN2A_D17/RGMII1_TXD0)
AM57XX_RGMII1_TD1: R331.2(P2) U1.B2(VIN2A_D16/RGMII1_TXD1)
AM57XX_RGMII1_TD2: R327.2(P2) U1.C4(VIN2A_D15/RGMII1_TXD2)
AM57XX_RGMII1_TD3: R332.2(P2) U1.C3(VIN2A_D14/RGMII1_TXD3)
AM57XX_RGMII1_TXCLK: R325.2(P2) U1.D5(VIN2A_D12/RGMII1_TXC)
AM57XX_RGMII1_TXCTL: R326.2(P2) U1.C2(VIN2A_D13/RGMII1_TXCTL)
AM57XX_VIN2A_DE0: R119.2(P2) ; also on sheet 29
AM57XX_VIN2A_HSYNC0: R118.2(P2) ; also on sheet 29
AM571X_PRU1ETH1_COL: R148.2(P2) U1.E2(VIN2A_D3/PR1_MII1_COL) ; also on sheet 29
AM571X_PRU1ETH1_TXD0: R125.2(P2) U1.F4(VIN2A_D5/PR1_MII1_TXD0) ; also on sheet 12 29
AM571X_PRU1ETH1_TXD1: R126.2(P2) U1.D2(VIN2A_D4/PR1_MII1_TXD1) ; also on sheet 29
AM571X_RGMII0_RD0: R289.2(P2) U1.W2(RGMII0_RXD0)
AM571X_RGMII0_RD1: R290.2(P2) U1.Y2(RGMII0_RXD1)
AM571X_RGMII0_RD2: R291.2(P2) U1.V3(RGMII0_RXD2)
AM571X_RGMII0_RD3: R292.2(P2) U1.V4(RGMII0_RXD3)
AM571X_RGMII0_RXCLK: R288.2(P2) U1.U5(RGMII0_RXC) ; also on sheet 29
AM571X_RGMII0_RXCTL: R285.2(P2) U1.V5(RGMII0_RXCTL)
AM571X_RGMII0_TD0: R282.2(P2) U1.U6(RGMII0_TXD0) ; also on sheet 29
AM571X_RGMII0_TD1: R287.2(P2) U1.V6(RGMII0_TXD1) ; also on sheet 29
AM571X_RGMII0_TD2: R283.2(P2) U1.U7(RGMII0_TXD2) ; also on sheet 29
AM571X_RGMII0_TD3: R284.2(P2) U1.V7(RGMII0_TXD3) ; also on sheet 29
AM571X_RGMII0_TXCLK: R281.2(P2) U1.W9(RGMII0_TXC) ; also on sheet 29
AM571X_RGMII0_TXCTL: R286.2(P2) U1.V9(RGMII0_TXCTL) ; also on sheet 29
AM571X_VIN2A_VSYNC0: R198.2(P2) ; also on sheet 29
AM572X_HDMI_DDC_SCL: R358.2(P2) ; also on sheet 5
AM572X_HDMI_DDC_SDA: R356.2(P2) ; also on sheet 5
ETH0_LDO_O: Q7.G(GATE) U21.43(LDO_O)
ETH0_MDC: R294.1(P1) U21.36(MDC)
ETH0_MDIO: R295.1(P1) U21.37(MDIO)
ETH0_RXCLK: R288.1(P1) R317.2(P2) U21.35(RX_CLK)
ETH0_RXD0: R289.1(P1) R299.2(P2) U21.32(RXD0)
ETH0_RXD1: R290.1(P1) R301.2(P2) U21.31(RXD1)
ETH0_RXD2: R291.1(P1) R306.2(P2) U21.28(RXD2)
ETH0_RXD3: R292.1(P1) R309.2(P2) U21.27(RXD3)
ETH0_RXDV: R285.1(P1) R304.2(P2) U21.33(RX_DV)
ETH0_TXCLK: R281.1(P1) U21.24(GTX_CLK)
ETH0_TXD0: R282.1(P1) U21.19(TXD0)
ETH0_TXD1: R287.1(P1) U21.20(TXD1)
ETH0_TXD2: R283.1(P1) U21.21(TXD2)
ETH0_TXD3: R284.1(P1) U21.22(TXD3)
ETH0_TXEN: R286.1(P1) U21.25(TX_EN)
ETH0GB_25MHzCLK: R315.2 U21.46(XI)
ETH1_LDO_O: Q8.G(GATE) U24.43(LDO_O)
ETH1_MDC: R338.1(P1) U24.36(MDC)
ETH1_MDIO: R339.1(P1) U24.37(MDIO)
ETH1_RESETn: C189.1 D4.2(Anode) R324.1(P1) U24.42(RESET_N) U26.4(Y)
ETH1_RXCLK: R328.1(P1) R361.2(P2) U24.35(RX_CLK)
ETH1_RXD0: R333.1(P1) R343.2(P2) U24.32(RXD0)
ETH1_RXD1: R334.1(P1) R345.2(P2) U24.31(RXD1)
ETH1_RXD2: R335.1(P1) R352.2(P2) U24.28(RXD2)
ETH1_RXD3: R336.1(P1) R353.2(P2) U24.27(RXD3)
ETH1_RXDV: R329.1(P1) R348.2(P2) U24.33(RX_DV)
ETH1_TXCLK: R325.1(P1) U24.24(GTX_CLK)
ETH1_TXD0: R330.1(P1) U24.19(TXD0)
ETH1_TXD1: R331.1(P1) U24.20(TXD1)
ETH1_TXD2: R327.1(P1) U24.21(TXD2)
ETH1_TXD3: R332.1(P1) U24.22(TXD3)
ETH1_TXEN: R326.1(P1) U24.25(TX_EN)
ETH1GB_25MHzCLK: R359.2 U24.46(XI)
ETH_MDIO_CLK: R294.2(P2) R338.2(P2) U1.V1(MDIO_MCLK) ; also on sheet 29
ETH_MDIO_DATA: R279.1(P1) R295.2(P2) R339.2(P2) U1.U4(MDIO_D) ; also on sheet 29
ETHER0_D0N: J10.10 U21.3(TXRXM_A)
ETHER0_D0P: J10.9 U21.2(TXRXP_A)
ETHER0_D1N: J10.8 U21.6(TXRXM_B)
ETHER0_D1P: J10.7 U21.5(TXRXP_B)
ETHER0_D2N: J10.6 U21.8(TXRXM_C)
ETHER0_D2P: J10.5 U21.7(TXRXP_C)
ETHER0_D3N: J10.4 U21.11(TXRXM_D)
ETHER0_D3P: J10.3 U21.10(TXRXP_D)
ETHER1_D0N: J12.10 U24.3(TXRXM_A)
ETHER1_D0P: J12.9 U24.2(TXRXP_A)
ETHER1_D1N: J12.8 U24.6(TXRXM_B)
ETHER1_D1P: J12.7 U24.5(TXRXP_B)
ETHER1_D2N: J12.6 U24.8(TXRXM_C)
ETHER1_D2P: J12.5 U24.7(TXRXP_C)
ETHER1_D3N: J12.4 U24.11(TXRXM_D)
ETHER1_D3P: J12.3 U24.10(TXRXP_D)
GB_ETH0_INTn: R297.1(P1) U21.38(INT_N_/_PME_N2) ; also on sheet 29
GB_ETH1_INTn: R342.1(P1) U24.38(INT_N_/_PME_N2) ; also on sheet 29
GBETH0_RESETn: C168.1 D3.2(Anode) R280.1(P1) U21.42(RESET_N) U22.4(Y)
GPIO_PCIE_RSTDRVn: U44.1(~{OE}) ; also on sheet 29
GPIO_PCIE_SWRSTn: U85.2(B) ; also on sheet 29
GPIO_PRU1_ETH_RESETn: R112.2(P2) R154.2(P2) ; also on sheet 29
GPIO_PRU2_ETH_RESETn: R195.2(P2) R234.2(P2) ; also on sheet 29
IND_I2C_SCL: R314.2(P2) R652.2(P2) ; also on sheet 4 9 10 11 18 29
IND_I2C_SDA: R312.2(P2) R653.2(P2) ; also on sheet 4 9 10 11 18 29
MMC_CD: J15.10(CD) R408.1(P1) R409.1(P1) U84.1
MMC_CLK: J15.5(CLOCK) R405.1(P1) U30.1(IO1)
MMC_CMD: J15.3(CMD) R398.1(P1) R404.1(P1) U30.7(IO5)
MMC_D0: J15.7(DAT0) R399.1(P1) R406.1(P1) U30.2(IO2)
MMC_D1: J15.8(DAT1) R400.1(P1) R407.1(P1) U30.3(IO3)
MMC_D2: J15.1(DAT2) R401.1(P1) R402.1(P1) U30.6(IO4)
MMC_D3: J15.2(CD/DAT3) R397.1(P1) R403.1(P1) U30.8(IO6)
PCI_CONN_REFN: C436.1 U45.5(OUT0N)
PCI_CONN_REFP: C437.1 U45.6(OUT0P)
PCIE_CRDPRESENT: R650.1(P1) ; also on sheet 29
PCIE_PERSTn: J52.A11 R545.1(P1) U44.4(Y)
PCIE_REFCLKN: C436.2 J52.A14 R580.2(P2)
PCIE_REFCLKP: C437.2 J52.A13 R580.1(P1)
PCIE_RESETn: R568.2(P2) U85.1(A) ; also on sheet 30
PCIE_SMB_CLK: J52.B5 R652.1(P1)
PCIE_SMB_DATA: J52.B6 R653.1(P1)
PCIE_TCK: J52.A5 R542.2(P2)
PCIE_TDI: J52.A6 R543.2(P2)
PCIE_TDO: J52.A7 TP20.1
PCIE_TMS: J52.A8 R544.2(P2)
PCIE_TRSTn: J52.B9 R539.1(P1)
PCIE_WAKEn: R655.1(P1) ; also on sheet 29
PCIECONN_PETn0: C477.2 J52.B15
PCIECONN_PETn1: C581.2 J52.B20
PCIECONN_PETp0: C478.2 J52.B14
PCIECONN_PETp1: C582.2 J52.B19
PHY0_LED_ACTn: R293.1 R321.2(P2) U21.17(LED1_/_PME_N1)
PHY0_LED_LINKn: R296.1 R319.2(P2) U21.15(LED2)
PHY1_LED_ACTn: R337.1 R364.2(P2) U24.17(LED1_/_PME_N1)
PHY1_LED_LINKn: R340.1 R363.2(P2) U24.15(LED2)
PHY_RESETn: U22.2(A) U26.2(A) U68.2(B) U69.2(B) U70.2(B) U71.2(B) ; also on sheet 30
PR1_MII0_COL: R95.2(P2) ; also on sheet 4 29
PR1_MII0_CRS: R94.2(P2) ; also on sheet 4
PR1_MII0_RXD0: R88.2(P2) ; also on sheet 4 29
PR1_MII0_RXD1: R90.2(P2) ; also on sheet 4 29
PR1_MII0_RXD2: R91.2(P2) ; also on sheet 4 29
PR1_MII0_RXD3: R92.2(P2) ; also on sheet 4 29
PR1_MII0_RXDV: R86.2(P2) ; also on sheet 4 29
PR1_MII0_RXER: R87.2(P2) ; also on sheet 4 29
PR1_MII0_RXLINK: R76.1(P1) R93.2(P2) U9.17(LED_LINK) ; also on sheet 4 29
PR1_MII0_TXD0: R81.2(P2) ; also on sheet 4 29
PR1_MII0_TXD1: R84.2(P2) ; also on sheet 4 29
PR1_MII0_TXD2: R85.2(P2) ; also on sheet 4 29
PR1_MII0_TXD3: R82.2(P2) ; also on sheet 4 29
PR1_MII0_TXEN: R80.2(P2) ; also on sheet 4 29
PR1_MII1_CRS: R139.2(P2) ; also on sheet 4 29
PR1_MII1_MR1_CLK: R129.2(P2) ; also on sheet 4 29
PR1_MII1_RXD0: R133.2(P2) ; also on sheet 4 29
PR1_MII1_RXD1: R135.2(P2) ; also on sheet 4 29
PR1_MII1_RXD2: R136.2(P2) ; also on sheet 4 29
PR1_MII1_RXD3: R137.2(P2) ; also on sheet 4 29
PR1_MII1_RXDV: R130.2(P2) ; also on sheet 4 29
PR1_MII1_RXER: R132.2(P2) ; also on sheet 4
PR1_MII1_RXLINK: R131.1(P1) R138.2(P2) U13.17(LED_LINK) ; also on sheet 4
PR1_MII_MR0_CLK: R83.2(P2) ; also on sheet 4 29
PR1_MII_MT0_CLK: R79.2(P2) ; also on sheet 4 29
PRU1ETH0_25MHzCLK: R310.2 U9.23(XI)
PRU1ETH0_COL: R95.1(P1) R104.2(P2) R106.2(P2) U9.29(COL)
PRU1ETH0_CRS: R94.1(P1) U9.27(CRS)
PRU1ETH0_INTn: U9.8(PWRDNn/INTn) ; also on sheet 29
PRU1ETH0_MDC: R96.1(P1) U9.20(MDC)
PRU1ETH0_MDIO: R98.1(P1) U9.19(MDIO)
PRU1ETH0_RESETn: U9.18(RESET_N) U68.4(Y)
PRU1ETH0_RXCLK: R83.1(P1) U9.25(RX_CLK)
PRU1ETH0_RXD0: R88.1(P1) R111.2(P2) U9.30(RXD_0)
PRU1ETH0_RXD1: R90.1(P1) R110.2(P2) U9.31(RXD_1)
PRU1ETH0_RXD2: R91.1(P1) R109.2(P2) U9.32(RXD_2)
PRU1ETH0_RXD3: R92.1(P1) R108.2(P2) U9.1(RXD_3)
PRU1ETH0_RXDV: R86.1(P1) U9.26(RX_DV)
PRU1ETH0_RXERR: R87.1(P1) U9.28(RX_ERR)
PRU1ETH0_TXCLK: R79.1(P1) U9.2(TX_CLK)
PRU1ETH0_TXD0: R81.1(P1) U9.4(TXD_0)
PRU1ETH0_TXD1: R84.1(P1) U9.5(TXD_1)
PRU1ETH0_TXD2: R85.1(P1) U9.6(TXD_2)
PRU1ETH0_TXD3: R82.1(P1) U9.7(TXD_3)
PRU1ETH0_TXEN: R80.1(P1) U9.3(TX_EN)
PRU1ETH1_25MHzCLK: R313.2 U13.23(XI)
PRU1ETH1_COL: R148.1(P1) R151.2(P2) R152.1(P1) U13.29(COL)
PRU1ETH1_CRS: R139.1(P1) U13.27(CRS)
PRU1ETH1_INTn: U13.8(PWRDNn/INTn) ; also on sheet 29
PRU1ETH1_MDC: R140.1(P1) U13.20(MDC)
PRU1ETH1_MDIO: R120.1(P1) R142.1(P1) U13.19(MDIO)
PRU1ETH1_RESETn: U13.18(RESET_N) U69.4(Y)
PRU1ETH1_RXCLK: R129.1(P1) U13.25(RX_CLK)
PRU1ETH1_RXD0: R133.1(P1) R158.2(P2) U13.30(RXD_0)
PRU1ETH1_RXD1: R135.1(P1) R157.2(P2) U13.31(RXD_1)
PRU1ETH1_RXD2: R136.1(P1) R156.2(P2) U13.32(RXD_2)
PRU1ETH1_RXD3: R137.1(P1) R155.2(P2) U13.1(RXD_3)
PRU1ETH1_RXDV: R130.1(P1) U13.26(RX_DV)
PRU1ETH1_RXERR: R132.1(P1) U13.28(RX_ERR)
PRU1ETH1_TXCLK: R123.1(P1) U13.2(TX_CLK)
PRU1ETH1_TXD0: R125.1(P1) U13.4(TXD_0)
PRU1ETH1_TXD1: R126.1(P1) U13.5(TXD_1)
PRU1ETH1_TXD2: R127.1(P1) U13.6(TXD_2)
PRU1ETH1_TXD3: R128.1(P1) U13.7(TXD_3)
PRU1ETH1_TXEN: R124.1(P1) U13.3(TX_EN)
PRU1ETHER0_RDN: J3.2 R99.2(P2) U9.9(RD-)
PRU1ETHER0_RDP: J3.1 R100.2(P2) U9.10(RD+)
PRU1ETHER0_TDN: J3.6 R101.2(P2) U9.11(TD-)
PRU1ETHER0_TDP: J3.5 R102.2(P2) U9.12(TD+)
PRU1ETHER1_RDN: J5.6 R143.2(P2) U13.9(RD-)
PRU1ETHER1_RDP: J5.5 R144.2(P2) U13.10(RD+)
PRU1ETHER1_TDN: J5.2 R145.2(P2) U13.11(TD-)
PRU1ETHER1_TDP: J5.1 R146.2(P2) U13.12(TD+)
PRU2ETH0_25MHzCLK: R354.2 U15.23(XI)
PRU2ETH0_COL: R178.1(P1) R187.2(P2) R188.1(P1) R189.2(P2) U15.29(COL)
PRU2ETH0_CRS: R177.1(P1) U15.27(CRS)
PRU2ETH0_INTn: U15.8(PWRDNn/INTn) ; also on sheet 29
PRU2ETH0_LINKLED: R159.1(P1) R176.2(P2) U15.17(LED_LINK)
PRU2ETH0_MDC: R179.1(P1) U15.20(MDC)
PRU2ETH0_MDIO: R181.1(P1) U15.19(MDIO)
PRU2ETH0_RESETn: U15.18(RESET_N) U70.4(Y)
PRU2ETH0_RXCLK: R165.1(P1) U15.25(RX_CLK)
PRU2ETH0_RXD0: R171.1(P1) R194.2(P2) U15.30(RXD_0)
PRU2ETH0_RXD1: R173.1(P1) R193.2(P2) U15.31(RXD_1)
PRU2ETH0_RXD2: R174.1(P1) R192.2(P2) U15.32(RXD_2)
PRU2ETH0_RXD3: R175.1(P1) R191.2(P2) U15.1(RXD_3)
PRU2ETH0_RXDV: R166.1(P1) U15.26(RX_DV)
PRU2ETH0_RXERR: R170.1(P1) U15.28(RX_ERR)
PRU2ETH0_TXCLK: R162.1(P1) U15.2(TX_CLK)
PRU2ETH0_TXD0: R163.1(P1) U15.4(TXD_0)
PRU2ETH0_TXD1: R164.1(P1) U15.5(TXD_1)
PRU2ETH0_TXD2: R168.1(P1) U15.6(TXD_2)
PRU2ETH0_TXD3: R169.1(P1) U15.7(TXD_3)
PRU2ETH0_TXEN: R167.1(P1) U15.3(TX_EN)
PRU2ETH1_25MHzCLK: R357.2 U17.23(XI)
PRU2ETH1_COL: R220.1(P1) R231.1(P1) R232.1(P1) U17.29(COL)
PRU2ETH1_CRS: R219.1(P1) U17.27(CRS)
PRU2ETH1_INTn: U17.8(PWRDNn/INTn) ; also on sheet 29
PRU2ETH1_LINKLED: R200.1(P1) R218.2(P2) U17.17(LED_LINK)
PRU2ETH1_MDC: R221.1(P1) U17.20(MDC)
PRU2ETH1_MDIO: R201.1(P1) R223.1(P1) U17.19(MDIO)
PRU2ETH1_RESETn: U17.18(RESET_N) U71.4(Y)
PRU2ETH1_RXCLK: R209.1(P1) U17.25(RX_CLK)
PRU2ETH1_RXD0: R213.1(P1) R238.2(P2) U17.30(RXD_0)
PRU2ETH1_RXD1: R215.1(P1) R237.2(P2) U17.31(RXD_1)
PRU2ETH1_RXD2: R216.1(P1) R236.2(P2) U17.32(RXD_2)
PRU2ETH1_RXD3: R217.1(P1) R235.2(P2) U17.1(RXD_3)
PRU2ETH1_RXDV: R117.2(P2) R211.1(P1) U17.26(RX_DV)
PRU2ETH1_RXERR: R212.1(P1) U17.28(RX_ERR)
PRU2ETH1_TXCLK: R204.1(P1) U17.2(TX_CLK)
PRU2ETH1_TXD0: R206.1(P1) U17.4(TXD_0)
PRU2ETH1_TXD1: R208.1(P1) U17.5(TXD_1)
PRU2ETH1_TXD2: R210.1(P1) U17.6(TXD_2)
PRU2ETH1_TXD3: R207.1(P1) U17.7(TXD_3)
PRU2ETH1_TXEN: R115.2(P2) R205.1(P1) U17.3(TX_EN)
PRU2ETHER0_RDN: J6.2 R182.2(P2) U15.9(RD-)
PRU2ETHER0_RDP: J6.1 R183.2(P2) U15.10(RD+)
PRU2ETHER0_TDN: J6.6 R184.2(P2) U15.11(TD-)
PRU2ETHER0_TDP: J6.5 R185.2(P2) U15.12(TD+)
PRU2ETHER1_RDN: J8.6 R224.2(P2) U17.9(RD-)
PRU2ETHER1_RDP: J8.5 R225.2(P2) U17.10(RD+)
PRU2ETHER1_TDN: J8.2 R226.2(P2) U17.11(TD-)
PRU2ETHER1_TDP: J8.1 R227.2(P2) U17.12(TD+)
RT2_MII0_EDIO_DATA0: J7.3 R198.1(P1)
RT2_MII0_EDIO_DATA1: J7.4 R199.1(P1)
RT2_MII0_RXDV: J7.2 R197.1(P1)
RT2_MII0_TXEN: J7.1 R196.1(P1)
RT2_MII1_EDIO_DATA0: J4.3 R118.1(P1)
RT2_MII1_EDIO_DATA1: J4.4 R119.1(P1)
RT2_MII1_RXDV: J4.2 R117.1(P1)
RT2_MII1_TXEN: J4.1 R115.1(P1)
SERDES_REF_CLKN: C438.1 U45.2(OUT1N)
SERDES_REF_CLKP: C439.1 U45.3(OUT1P)
VADD33_PRU1ETH0: C112.1 R97.2(P2) U9.14(AVDD33)
VADD33_PRU1ETH1: C118.1 R141.2(P2) U13.14(AVDD33)
VADD33_PRU2ETH0: C137.1 R180.2(P2) U15.14(AVDD33)
VADD33_PRU2ETH1: C142.1 R222.2(P2) U17.14(AVDD33)
VETH0_AVDDH: C153.1 C154.1 C157.1 FB1.2 Q7.S(SOURCE) U21.1(AVDDH) U21.12(AVDDH) U21.47(AVDDH)
VETH0_AVDDL: C161.1 C162.1 FB4.2 U21.4(AVDDL) U21.9(AVDDL)
VETH0_AVDDL_PLL: C163.1 C164.1 C165.1 FB2.2 U21.44(AVDDL_PLL)
VETH0_AVDDL_PMOS: C158.1 FB2.1 FB3.1 FB4.1 Q7.D1(DRAIN1) Q7.D2(DRAIN2)
VETH0_DVDDH: C155.1 C156.1 C171.1 D3.1(Cathode) R278.1(P1) R279.2(P2) R280.2(P2) R297.2(P2) R299.1(P1) R301.1(P1) R306.1(P1) R309.1(P1) U21.16(DVDDH) U21.34(DVDDH) U21.40(DVDDH) U22.5(VCC)
VETH0_DVDDL: C159.1 C160.1 FB3.2 U21.14(DVDDL) U21.18(DVDDL) U21.23(DVDDL) U21.26(DVDDL) U21.30(DVDDL) U21.39(DVDDL)
VETH1_AVDDH: C176.1 C177.1 C178.1 FB5.2 Q8.S(SOURCE) U24.1(AVDDH) U24.12(AVDDH) U24.47(AVDDH)
VETH1_AVDDL: C182.1 C183.1 FB8.2 U24.4(AVDDL) U24.9(AVDDL)
VETH1_AVDDL_PLL: C184.1 C185.1 C186.1 FB6.2 U24.44(AVDDL_PLL)
VETH1_AVDDL_PMOS: C179.1 FB6.1 FB7.1 FB8.1 Q8.D1(DRAIN1) Q8.D2(DRAIN2)
VETH1_DVDDH: C174.1 C175.1 C192.1 D4.1(Cathode) R322.1(P1) R324.2(P2) R342.2(P2) R343.1(P1) R345.1(P1) R352.1(P1) R353.1(P1) R364.1(P1) U24.16(DVDDH) U24.34(DVDDH) U24.40(DVDDH) U26.5(VCC)
VETH1_DVDDL: C180.1 C181.1 FB7.2 U24.14(DVDDL) U24.18(DVDDL) U24.23(DVDDL) U24.26(DVDDL) U24.30(DVDDL) U24.39(DVDDL)
VSDMMC: R397.2(P2) R398.2(P2) R399.2(P2) R400.2(P2) R401.2(P2) R408.2(P2) R644.2(P2) ; also on sheet 9 17 31
N12123192: J10.11 R293.2
N12123204: J10.14 R296.2
N12138943: R298.1 U21.48(ISET)
N12139138: TP16.1 U21.41(CLK125_NDO)
N12220066: C108.1 C109.1 C110.1 C111.1 U9.13(PFBIN1) U9.15(PFBOUT) U9.24(PFBIN2)
N12225140: J5.11 R122.1(P1)
N12225158: C123.1 C124.1 C125.1 C126.1 U13.13(PFBIN1) U13.15(PFBOUT) U13.24(PFBIN2)
N12225278: J5.10 R151.1(P1)
N12226470: J5.9 R134.1(P1)
N12226568: R153.1(P1) R154.1(P1) U69.1(A)
N15911835: R147.2(P2) U13.16(RBIAS)
N16700927: J5.12 R138.1(P1)
N16818596: J3.9 R89.1(P1)
N16818719: R107.1(P1) R112.1(P1) U68.1(A)
N16819128: R103.2(P2) U9.16(RBIAS)
N17074741: J3.10 R106.1(P1)
N17156111: C172.2 R305.2(P2) U23.1(Xin/CLK) Y3.2
N17156113: C173.2 R305.1(P1) R308.2(P2) Y3.1
N17156222: R308.1(P1) U23.14(XOUT)
N17156522: R310.1 U23.11(Y1)
N17156525: R313.1 U23.9(Y2)
N17156528: R315.1 U23.8(Y3)
N17156983: R314.1(P1) U23.12(S2/SCL)
N17156986: R312.1(P1) U23.13(S1/SDA)
N17569906: J12.11 R337.2
N17569909: J12.14 R340.2
N17569918: R341.1 U24.48(ISET)
N17569921: TP17.1 U24.41(CLK125_NDO)
N17570093: C193.2 R349.2(P2) U25.1(Xin/CLK) Y4.2
N17570094: C194.2 R349.1(P1) R351.2(P2) Y4.1
N17570107: R351.1(P1) U25.14(XOUT)
N17570112: R354.1 U25.11(Y1)
N17570113: R357.1 U25.9(Y2)
N17570114: R359.1 U25.8(Y3)
N17570122: R358.1(P1) U25.12(S2/SCL)
N17570123: R356.1(P1) U25.13(S1/SDA)
N17594977: C134.1 C135.1 C136.1 C138.1 U15.13(PFBIN1) U15.15(PFBOUT) U15.24(PFBIN2)
N17595008: J6.9 R172.1(P1)
N17595032: R190.1(P1) R195.1(P1) U70.1(A)
N17595048: R186.2(P2) U15.16(RBIAS)
N17595072: J6.10 R189.1(P1)
N17595076: J6.11 R161.1(P1)
N17595078: J6.12 R176.1(P1)
N17596821: J8.11 R203.1(P1)
N17596823: C147.1 C148.1 C149.1 C150.1 U17.13(PFBIN1) U17.15(PFBOUT) U17.24(PFBIN2)
N17596838: J8.10 R230.1(P1) R231.2(P2)
N17596847: R230.2(P2) U1.C17(MCASP3_AXR1/PR2_MII1_RXLINK)
N17596886: J8.9 R214.1(P1)
N17596899: R233.1(P1) R234.1(P1) U71.1(A)
N17596976: R228.2(P2) U17.16(RBIAS)
N17596979: J8.12 R218.1(P1)
N17863265: J3.11 R78.1(P1)
N17863276: J3.12 R93.1(P1)
N19258097: R546.1(P1) U45.7(OE)
N19258128: U45.21(XIN) Y7.3(CLK)
N19258198: R547.1(P1) Y7.1(OE)
N19258383: R548.1(P1) U45.11(OS0)
N19258403: R549.1(P1) R550.1(P1) U45.10(OS1)
N19258622: C305.1 U45.17(REG_CAP2)
N19258627: C306.1 U45.19(REG_CAP1)
N19415733: R568.1(P1) U45.12(RSTn)
N20301491: J52.A1 R649.1(P1) R650.2(P2)
N20338433: J52.B11 R654.1(P1) R655.2(P2)
N20537306: U44.2(A) U85.4(Y)

Not connected (* = marked no-connect by the designer): J3 7; J5 7; J6 7; J8 7; J10 2; J12 2; J52 A19* A25* A26* A29* A30* A32* B12* B17* B23* B24* B27* B28* B30*; U9 22(XO)*; U13 22(XO)*; U15 22(XO)*; U17 22(XO)*; U21 45(XO)*; U22 1(NC)*; U23 2(S0)* 4(Vctr)*; U24 45(XO)*; U25 2(S0)* 4(Vctr)*; U26 1(NC)*; U30 4(NC1)* 9(NC2)*; U45 8(NC8)* 13(NC13)* 15(NC15)* 23(OSCOUT) 24(NC24)* 25(NC25)* 26(NC26)* 27(NC27)* 28(NC28)* 29(NC29)* 30(NC30)* 31(NC31)* 32(NC32)*

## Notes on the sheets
sheet 21
- PR2_EDC_LATCH0 (ES2.0)
- PR1_EDC_LATCH0 (ES2.0)
- Note: MDIO Address = 0x01
sheet 22
- AM57XX_PR1_PROFI_TXEN
- PR1_EDC_SYNC0
- Note: MDIO Address = 0x01
sheet 23
- Note: MDIO Address = 0x00
sheet 24
- PR1_EDC_SYNC0 (ES2.0)
- PR2_EDC_SYNC0 (ES2.0)
- Note: MDIO Address = 0x00
sheet 25
- SD/MMC1 Connector
